VERSION 5.8 ;
BUSBITCHARS "[]" ;
DIVIDERCHAR "/" ;
UNITS
    DATABASE MICRONS 1000 ;
END UNITS

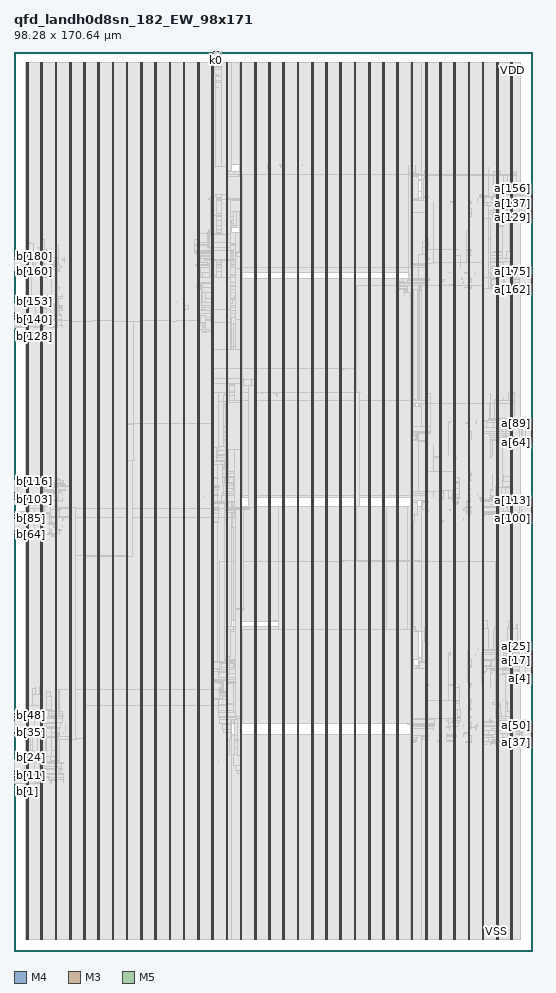
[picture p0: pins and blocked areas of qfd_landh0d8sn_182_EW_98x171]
MACRO qfd_landh0d8sn_182_EW_98x171
  FOREIGN qfd_landh0d8sn_182_EW_98x171 0 0 ;
  CLASS BLOCK ;
  SIZE 98.28 BY 170.64 ;
  PIN a[0]
    DIRECTION INPUT ;
    USE SIGNAL ;
    PORT
      LAYER M4 ;
        RECT  98.196 52.56 98.28 52.584 ;
    END
  END a[0]
  PIN a[100]
    DIRECTION INPUT ;
    USE SIGNAL ;
    PORT
      LAYER M4 ;
        RECT  98.196 81.936 98.28 81.96 ;
    END
  END a[100]
  PIN a[101]
    DIRECTION INPUT ;
    USE SIGNAL ;
    PORT
      LAYER M4 ;
        RECT  98.196 82.08 98.28 82.104 ;
    END
  END a[101]
  PIN a[102]
    DIRECTION INPUT ;
    USE SIGNAL ;
    PORT
      LAYER M4 ;
        RECT  98.196 82.224 98.28 82.248 ;
    END
  END a[102]
  PIN a[103]
    DIRECTION INPUT ;
    USE SIGNAL ;
    PORT
      LAYER M4 ;
        RECT  98.196 82.368 98.28 82.392 ;
    END
  END a[103]
  PIN a[104]
    DIRECTION INPUT ;
    USE SIGNAL ;
    PORT
      LAYER M4 ;
        RECT  98.196 82.512 98.28 82.536 ;
    END
  END a[104]
  PIN a[105]
    DIRECTION INPUT ;
    USE SIGNAL ;
    PORT
      LAYER M4 ;
        RECT  98.196 82.656 98.28 82.68 ;
    END
  END a[105]
  PIN a[106]
    DIRECTION INPUT ;
    USE SIGNAL ;
    PORT
      LAYER M4 ;
        RECT  98.196 82.8 98.28 82.824 ;
    END
  END a[106]
  PIN a[107]
    DIRECTION INPUT ;
    USE SIGNAL ;
    PORT
      LAYER M4 ;
        RECT  98.196 82.944 98.28 82.968 ;
    END
  END a[107]
  PIN a[108]
    DIRECTION INPUT ;
    USE SIGNAL ;
    PORT
      LAYER M4 ;
        RECT  98.196 83.088 98.28 83.112 ;
    END
  END a[108]
  PIN a[109]
    DIRECTION INPUT ;
    USE SIGNAL ;
    PORT
      LAYER M4 ;
        RECT  98.196 83.232 98.28 83.256 ;
    END
  END a[109]
  PIN a[10]
    DIRECTION INPUT ;
    USE SIGNAL ;
    PORT
      LAYER M4 ;
        RECT  98.196 54 98.28 54.024 ;
    END
  END a[10]
  PIN a[110]
    DIRECTION INPUT ;
    USE SIGNAL ;
    PORT
      LAYER M4 ;
        RECT  98.196 83.376 98.28 83.4 ;
    END
  END a[110]
  PIN a[111]
    DIRECTION INPUT ;
    USE SIGNAL ;
    PORT
      LAYER M4 ;
        RECT  98.196 83.52 98.28 83.544 ;
    END
  END a[111]
  PIN a[112]
    DIRECTION INPUT ;
    USE SIGNAL ;
    PORT
      LAYER M4 ;
        RECT  98.196 83.664 98.28 83.688 ;
    END
  END a[112]
  PIN a[113]
    DIRECTION INPUT ;
    USE SIGNAL ;
    PORT
      LAYER M4 ;
        RECT  98.196 83.808 98.28 83.832 ;
    END
  END a[113]
  PIN a[114]
    DIRECTION INPUT ;
    USE SIGNAL ;
    PORT
      LAYER M4 ;
        RECT  98.196 83.952 98.28 83.976 ;
    END
  END a[114]
  PIN a[115]
    DIRECTION INPUT ;
    USE SIGNAL ;
    PORT
      LAYER M4 ;
        RECT  98.196 84.096 98.28 84.12 ;
    END
  END a[115]
  PIN a[116]
    DIRECTION INPUT ;
    USE SIGNAL ;
    PORT
      LAYER M4 ;
        RECT  98.196 84.24 98.28 84.264 ;
    END
  END a[116]
  PIN a[117]
    DIRECTION INPUT ;
    USE SIGNAL ;
    PORT
      LAYER M4 ;
        RECT  98.196 84.384 98.28 84.408 ;
    END
  END a[117]
  PIN a[118]
    DIRECTION INPUT ;
    USE SIGNAL ;
    PORT
      LAYER M4 ;
        RECT  98.196 84.528 98.28 84.552 ;
    END
  END a[118]
  PIN a[119]
    DIRECTION INPUT ;
    USE SIGNAL ;
    PORT
      LAYER M4 ;
        RECT  98.196 84.672 98.28 84.696 ;
    END
  END a[119]
  PIN a[11]
    DIRECTION INPUT ;
    USE SIGNAL ;
    PORT
      LAYER M4 ;
        RECT  98.196 54.144 98.28 54.168 ;
    END
  END a[11]
  PIN a[120]
    DIRECTION INPUT ;
    USE SIGNAL ;
    PORT
      LAYER M4 ;
        RECT  98.196 84.816 98.28 84.84 ;
    END
  END a[120]
  PIN a[121]
    DIRECTION INPUT ;
    USE SIGNAL ;
    PORT
      LAYER M4 ;
        RECT  98.196 84.96 98.28 84.984 ;
    END
  END a[121]
  PIN a[122]
    DIRECTION INPUT ;
    USE SIGNAL ;
    PORT
      LAYER M4 ;
        RECT  98.196 85.104 98.28 85.128 ;
    END
  END a[122]
  PIN a[123]
    DIRECTION INPUT ;
    USE SIGNAL ;
    PORT
      LAYER M4 ;
        RECT  98.196 85.248 98.28 85.272 ;
    END
  END a[123]
  PIN a[124]
    DIRECTION INPUT ;
    USE SIGNAL ;
    PORT
      LAYER M4 ;
        RECT  98.196 85.392 98.28 85.416 ;
    END
  END a[124]
  PIN a[125]
    DIRECTION INPUT ;
    USE SIGNAL ;
    PORT
      LAYER M4 ;
        RECT  98.196 85.536 98.28 85.56 ;
    END
  END a[125]
  PIN a[126]
    DIRECTION INPUT ;
    USE SIGNAL ;
    PORT
      LAYER M4 ;
        RECT  98.196 85.68 98.28 85.704 ;
    END
  END a[126]
  PIN a[127]
    DIRECTION INPUT ;
    USE SIGNAL ;
    PORT
      LAYER M4 ;
        RECT  98.196 85.824 98.28 85.848 ;
    END
  END a[127]
  PIN a[128]
    DIRECTION INPUT ;
    USE SIGNAL ;
    PORT
      LAYER M4 ;
        RECT  98.196 138.96 98.28 138.984 ;
    END
  END a[128]
  PIN a[129]
    DIRECTION INPUT ;
    USE SIGNAL ;
    PORT
      LAYER M4 ;
        RECT  98.196 139.104 98.28 139.128 ;
    END
  END a[129]
  PIN a[12]
    DIRECTION INPUT ;
    USE SIGNAL ;
    PORT
      LAYER M4 ;
        RECT  98.196 54.288 98.28 54.312 ;
    END
  END a[12]
  PIN a[130]
    DIRECTION INPUT ;
    USE SIGNAL ;
    PORT
      LAYER M4 ;
        RECT  98.196 139.248 98.28 139.272 ;
    END
  END a[130]
  PIN a[131]
    DIRECTION INPUT ;
    USE SIGNAL ;
    PORT
      LAYER M4 ;
        RECT  98.196 139.392 98.28 139.416 ;
    END
  END a[131]
  PIN a[132]
    DIRECTION INPUT ;
    USE SIGNAL ;
    PORT
      LAYER M4 ;
        RECT  98.196 139.536 98.28 139.56 ;
    END
  END a[132]
  PIN a[133]
    DIRECTION INPUT ;
    USE SIGNAL ;
    PORT
      LAYER M4 ;
        RECT  98.196 139.68 98.28 139.704 ;
    END
  END a[133]
  PIN a[134]
    DIRECTION INPUT ;
    USE SIGNAL ;
    PORT
      LAYER M4 ;
        RECT  98.196 139.824 98.28 139.848 ;
    END
  END a[134]
  PIN a[135]
    DIRECTION INPUT ;
    USE SIGNAL ;
    PORT
      LAYER M4 ;
        RECT  98.196 139.968 98.28 139.992 ;
    END
  END a[135]
  PIN a[136]
    DIRECTION INPUT ;
    USE SIGNAL ;
    PORT
      LAYER M4 ;
        RECT  98.196 140.112 98.28 140.136 ;
    END
  END a[136]
  PIN a[137]
    DIRECTION INPUT ;
    USE SIGNAL ;
    PORT
      LAYER M4 ;
        RECT  98.196 140.256 98.28 140.28 ;
    END
  END a[137]
  PIN a[138]
    DIRECTION INPUT ;
    USE SIGNAL ;
    PORT
      LAYER M4 ;
        RECT  98.196 140.4 98.28 140.424 ;
    END
  END a[138]
  PIN a[139]
    DIRECTION INPUT ;
    USE SIGNAL ;
    PORT
      LAYER M4 ;
        RECT  98.196 140.544 98.28 140.568 ;
    END
  END a[139]
  PIN a[13]
    DIRECTION INPUT ;
    USE SIGNAL ;
    PORT
      LAYER M4 ;
        RECT  98.196 54.432 98.28 54.456 ;
    END
  END a[13]
  PIN a[140]
    DIRECTION INPUT ;
    USE SIGNAL ;
    PORT
      LAYER M4 ;
        RECT  98.196 140.688 98.28 140.712 ;
    END
  END a[140]
  PIN a[141]
    DIRECTION INPUT ;
    USE SIGNAL ;
    PORT
      LAYER M4 ;
        RECT  98.196 140.832 98.28 140.856 ;
    END
  END a[141]
  PIN a[142]
    DIRECTION INPUT ;
    USE SIGNAL ;
    PORT
      LAYER M4 ;
        RECT  98.196 140.976 98.28 141 ;
    END
  END a[142]
  PIN a[143]
    DIRECTION INPUT ;
    USE SIGNAL ;
    PORT
      LAYER M4 ;
        RECT  98.196 141.12 98.28 141.144 ;
    END
  END a[143]
  PIN a[144]
    DIRECTION INPUT ;
    USE SIGNAL ;
    PORT
      LAYER M4 ;
        RECT  98.196 141.264 98.28 141.288 ;
    END
  END a[144]
  PIN a[145]
    DIRECTION INPUT ;
    USE SIGNAL ;
    PORT
      LAYER M4 ;
        RECT  98.196 141.408 98.28 141.432 ;
    END
  END a[145]
  PIN a[146]
    DIRECTION INPUT ;
    USE SIGNAL ;
    PORT
      LAYER M4 ;
        RECT  98.196 141.552 98.28 141.576 ;
    END
  END a[146]
  PIN a[147]
    DIRECTION INPUT ;
    USE SIGNAL ;
    PORT
      LAYER M4 ;
        RECT  98.196 141.696 98.28 141.72 ;
    END
  END a[147]
  PIN a[148]
    DIRECTION INPUT ;
    USE SIGNAL ;
    PORT
      LAYER M4 ;
        RECT  98.196 141.84 98.28 141.864 ;
    END
  END a[148]
  PIN a[149]
    DIRECTION INPUT ;
    USE SIGNAL ;
    PORT
      LAYER M4 ;
        RECT  98.196 141.984 98.28 142.008 ;
    END
  END a[149]
  PIN a[14]
    DIRECTION INPUT ;
    USE SIGNAL ;
    PORT
      LAYER M4 ;
        RECT  98.196 54.576 98.28 54.6 ;
    END
  END a[14]
  PIN a[150]
    DIRECTION INPUT ;
    USE SIGNAL ;
    PORT
      LAYER M4 ;
        RECT  98.196 142.128 98.28 142.152 ;
    END
  END a[150]
  PIN a[151]
    DIRECTION INPUT ;
    USE SIGNAL ;
    PORT
      LAYER M4 ;
        RECT  98.196 142.272 98.28 142.296 ;
    END
  END a[151]
  PIN a[152]
    DIRECTION INPUT ;
    USE SIGNAL ;
    PORT
      LAYER M4 ;
        RECT  98.196 142.416 98.28 142.44 ;
    END
  END a[152]
  PIN a[153]
    DIRECTION INPUT ;
    USE SIGNAL ;
    PORT
      LAYER M4 ;
        RECT  98.196 142.56 98.28 142.584 ;
    END
  END a[153]
  PIN a[154]
    DIRECTION INPUT ;
    USE SIGNAL ;
    PORT
      LAYER M4 ;
        RECT  98.196 142.704 98.28 142.728 ;
    END
  END a[154]
  PIN a[155]
    DIRECTION INPUT ;
    USE SIGNAL ;
    PORT
      LAYER M4 ;
        RECT  98.196 142.848 98.28 142.872 ;
    END
  END a[155]
  PIN a[156]
    DIRECTION INPUT ;
    USE SIGNAL ;
    PORT
      LAYER M4 ;
        RECT  98.196 142.992 98.28 143.016 ;
    END
  END a[156]
  PIN a[157]
    DIRECTION INPUT ;
    USE SIGNAL ;
    PORT
      LAYER M4 ;
        RECT  98.196 143.136 98.28 143.16 ;
    END
  END a[157]
  PIN a[158]
    DIRECTION INPUT ;
    USE SIGNAL ;
    PORT
      LAYER M4 ;
        RECT  98.196 143.28 98.28 143.304 ;
    END
  END a[158]
  PIN a[159]
    DIRECTION INPUT ;
    USE SIGNAL ;
    PORT
      LAYER M4 ;
        RECT  98.196 143.424 98.28 143.448 ;
    END
  END a[159]
  PIN a[15]
    DIRECTION INPUT ;
    USE SIGNAL ;
    PORT
      LAYER M4 ;
        RECT  98.196 54.72 98.28 54.744 ;
    END
  END a[15]
  PIN a[160]
    DIRECTION INPUT ;
    USE SIGNAL ;
    PORT
      LAYER M4 ;
        RECT  98.196 125.136 98.28 125.16 ;
    END
  END a[160]
  PIN a[161]
    DIRECTION INPUT ;
    USE SIGNAL ;
    PORT
      LAYER M4 ;
        RECT  98.196 125.28 98.28 125.304 ;
    END
  END a[161]
  PIN a[162]
    DIRECTION INPUT ;
    USE SIGNAL ;
    PORT
      LAYER M4 ;
        RECT  98.196 125.424 98.28 125.448 ;
    END
  END a[162]
  PIN a[163]
    DIRECTION INPUT ;
    USE SIGNAL ;
    PORT
      LAYER M4 ;
        RECT  98.196 125.568 98.28 125.592 ;
    END
  END a[163]
  PIN a[164]
    DIRECTION INPUT ;
    USE SIGNAL ;
    PORT
      LAYER M4 ;
        RECT  98.196 125.712 98.28 125.736 ;
    END
  END a[164]
  PIN a[165]
    DIRECTION INPUT ;
    USE SIGNAL ;
    PORT
      LAYER M4 ;
        RECT  98.196 125.856 98.28 125.88 ;
    END
  END a[165]
  PIN a[166]
    DIRECTION INPUT ;
    USE SIGNAL ;
    PORT
      LAYER M4 ;
        RECT  98.196 126 98.28 126.024 ;
    END
  END a[166]
  PIN a[167]
    DIRECTION INPUT ;
    USE SIGNAL ;
    PORT
      LAYER M4 ;
        RECT  98.196 126.144 98.28 126.168 ;
    END
  END a[167]
  PIN a[168]
    DIRECTION INPUT ;
    USE SIGNAL ;
    PORT
      LAYER M4 ;
        RECT  98.196 126.288 98.28 126.312 ;
    END
  END a[168]
  PIN a[169]
    DIRECTION INPUT ;
    USE SIGNAL ;
    PORT
      LAYER M4 ;
        RECT  98.196 126.432 98.28 126.456 ;
    END
  END a[169]
  PIN a[16]
    DIRECTION INPUT ;
    USE SIGNAL ;
    PORT
      LAYER M4 ;
        RECT  98.196 54.864 98.28 54.888 ;
    END
  END a[16]
  PIN a[170]
    DIRECTION INPUT ;
    USE SIGNAL ;
    PORT
      LAYER M4 ;
        RECT  98.196 126.576 98.28 126.6 ;
    END
  END a[170]
  PIN a[171]
    DIRECTION INPUT ;
    USE SIGNAL ;
    PORT
      LAYER M4 ;
        RECT  98.196 126.72 98.28 126.744 ;
    END
  END a[171]
  PIN a[172]
    DIRECTION INPUT ;
    USE SIGNAL ;
    PORT
      LAYER M4 ;
        RECT  98.196 126.864 98.28 126.888 ;
    END
  END a[172]
  PIN a[173]
    DIRECTION INPUT ;
    USE SIGNAL ;
    PORT
      LAYER M4 ;
        RECT  98.196 127.008 98.28 127.032 ;
    END
  END a[173]
  PIN a[174]
    DIRECTION INPUT ;
    USE SIGNAL ;
    PORT
      LAYER M4 ;
        RECT  98.196 127.152 98.28 127.176 ;
    END
  END a[174]
  PIN a[175]
    DIRECTION INPUT ;
    USE SIGNAL ;
    PORT
      LAYER M4 ;
        RECT  98.196 127.296 98.28 127.32 ;
    END
  END a[175]
  PIN a[176]
    DIRECTION INPUT ;
    USE SIGNAL ;
    PORT
      LAYER M4 ;
        RECT  98.196 127.44 98.28 127.464 ;
    END
  END a[176]
  PIN a[177]
    DIRECTION INPUT ;
    USE SIGNAL ;
    PORT
      LAYER M4 ;
        RECT  98.196 127.584 98.28 127.608 ;
    END
  END a[177]
  PIN a[178]
    DIRECTION INPUT ;
    USE SIGNAL ;
    PORT
      LAYER M4 ;
        RECT  98.196 127.728 98.28 127.752 ;
    END
  END a[178]
  PIN a[179]
    DIRECTION INPUT ;
    USE SIGNAL ;
    PORT
      LAYER M4 ;
        RECT  98.196 127.872 98.28 127.896 ;
    END
  END a[179]
  PIN a[17]
    DIRECTION INPUT ;
    USE SIGNAL ;
    PORT
      LAYER M4 ;
        RECT  98.196 55.008 98.28 55.032 ;
    END
  END a[17]
  PIN a[180]
    DIRECTION INPUT ;
    USE SIGNAL ;
    PORT
      LAYER M4 ;
        RECT  98.196 128.016 98.28 128.04 ;
    END
  END a[180]
  PIN a[181]
    DIRECTION INPUT ;
    USE SIGNAL ;
    PORT
      LAYER M4 ;
        RECT  98.196 128.16 98.28 128.184 ;
    END
  END a[181]
  PIN a[18]
    DIRECTION INPUT ;
    USE SIGNAL ;
    PORT
      LAYER M4 ;
        RECT  98.196 55.152 98.28 55.176 ;
    END
  END a[18]
  PIN a[19]
    DIRECTION INPUT ;
    USE SIGNAL ;
    PORT
      LAYER M4 ;
        RECT  98.196 55.296 98.28 55.32 ;
    END
  END a[19]
  PIN a[1]
    DIRECTION INPUT ;
    USE SIGNAL ;
    PORT
      LAYER M4 ;
        RECT  98.196 52.704 98.28 52.728 ;
    END
  END a[1]
  PIN a[20]
    DIRECTION INPUT ;
    USE SIGNAL ;
    PORT
      LAYER M4 ;
        RECT  98.196 55.44 98.28 55.464 ;
    END
  END a[20]
  PIN a[21]
    DIRECTION INPUT ;
    USE SIGNAL ;
    PORT
      LAYER M4 ;
        RECT  98.196 55.584 98.28 55.608 ;
    END
  END a[21]
  PIN a[22]
    DIRECTION INPUT ;
    USE SIGNAL ;
    PORT
      LAYER M4 ;
        RECT  98.196 55.728 98.28 55.752 ;
    END
  END a[22]
  PIN a[23]
    DIRECTION INPUT ;
    USE SIGNAL ;
    PORT
      LAYER M4 ;
        RECT  98.196 55.872 98.28 55.896 ;
    END
  END a[23]
  PIN a[24]
    DIRECTION INPUT ;
    USE SIGNAL ;
    PORT
      LAYER M4 ;
        RECT  98.196 56.016 98.28 56.04 ;
    END
  END a[24]
  PIN a[25]
    DIRECTION INPUT ;
    USE SIGNAL ;
    PORT
      LAYER M4 ;
        RECT  98.196 56.16 98.28 56.184 ;
    END
  END a[25]
  PIN a[26]
    DIRECTION INPUT ;
    USE SIGNAL ;
    PORT
      LAYER M4 ;
        RECT  98.196 56.304 98.28 56.328 ;
    END
  END a[26]
  PIN a[27]
    DIRECTION INPUT ;
    USE SIGNAL ;
    PORT
      LAYER M4 ;
        RECT  98.196 56.448 98.28 56.472 ;
    END
  END a[27]
  PIN a[28]
    DIRECTION INPUT ;
    USE SIGNAL ;
    PORT
      LAYER M4 ;
        RECT  98.196 56.592 98.28 56.616 ;
    END
  END a[28]
  PIN a[29]
    DIRECTION INPUT ;
    USE SIGNAL ;
    PORT
      LAYER M4 ;
        RECT  98.196 56.736 98.28 56.76 ;
    END
  END a[29]
  PIN a[2]
    DIRECTION INPUT ;
    USE SIGNAL ;
    PORT
      LAYER M4 ;
        RECT  98.196 52.848 98.28 52.872 ;
    END
  END a[2]
  PIN a[30]
    DIRECTION INPUT ;
    USE SIGNAL ;
    PORT
      LAYER M4 ;
        RECT  98.196 56.88 98.28 56.904 ;
    END
  END a[30]
  PIN a[31]
    DIRECTION INPUT ;
    USE SIGNAL ;
    PORT
      LAYER M4 ;
        RECT  98.196 57.024 98.28 57.048 ;
    END
  END a[31]
  PIN a[32]
    DIRECTION INPUT ;
    USE SIGNAL ;
    PORT
      LAYER M4 ;
        RECT  98.196 38.736 98.28 38.76 ;
    END
  END a[32]
  PIN a[33]
    DIRECTION INPUT ;
    USE SIGNAL ;
    PORT
      LAYER M4 ;
        RECT  98.196 38.88 98.28 38.904 ;
    END
  END a[33]
  PIN a[34]
    DIRECTION INPUT ;
    USE SIGNAL ;
    PORT
      LAYER M4 ;
        RECT  98.196 39.024 98.28 39.048 ;
    END
  END a[34]
  PIN a[35]
    DIRECTION INPUT ;
    USE SIGNAL ;
    PORT
      LAYER M4 ;
        RECT  98.196 39.168 98.28 39.192 ;
    END
  END a[35]
  PIN a[36]
    DIRECTION INPUT ;
    USE SIGNAL ;
    PORT
      LAYER M4 ;
        RECT  98.196 39.312 98.28 39.336 ;
    END
  END a[36]
  PIN a[37]
    DIRECTION INPUT ;
    USE SIGNAL ;
    PORT
      LAYER M4 ;
        RECT  98.196 39.456 98.28 39.48 ;
    END
  END a[37]
  PIN a[38]
    DIRECTION INPUT ;
    USE SIGNAL ;
    PORT
      LAYER M4 ;
        RECT  98.196 39.6 98.28 39.624 ;
    END
  END a[38]
  PIN a[39]
    DIRECTION INPUT ;
    USE SIGNAL ;
    PORT
      LAYER M4 ;
        RECT  98.196 39.744 98.28 39.768 ;
    END
  END a[39]
  PIN a[3]
    DIRECTION INPUT ;
    USE SIGNAL ;
    PORT
      LAYER M4 ;
        RECT  98.196 52.992 98.28 53.016 ;
    END
  END a[3]
  PIN a[40]
    DIRECTION INPUT ;
    USE SIGNAL ;
    PORT
      LAYER M4 ;
        RECT  98.196 39.888 98.28 39.912 ;
    END
  END a[40]
  PIN a[41]
    DIRECTION INPUT ;
    USE SIGNAL ;
    PORT
      LAYER M4 ;
        RECT  98.196 40.032 98.28 40.056 ;
    END
  END a[41]
  PIN a[42]
    DIRECTION INPUT ;
    USE SIGNAL ;
    PORT
      LAYER M4 ;
        RECT  98.196 40.176 98.28 40.2 ;
    END
  END a[42]
  PIN a[43]
    DIRECTION INPUT ;
    USE SIGNAL ;
    PORT
      LAYER M4 ;
        RECT  98.196 40.32 98.28 40.344 ;
    END
  END a[43]
  PIN a[44]
    DIRECTION INPUT ;
    USE SIGNAL ;
    PORT
      LAYER M4 ;
        RECT  98.196 40.464 98.28 40.488 ;
    END
  END a[44]
  PIN a[45]
    DIRECTION INPUT ;
    USE SIGNAL ;
    PORT
      LAYER M4 ;
        RECT  98.196 40.608 98.28 40.632 ;
    END
  END a[45]
  PIN a[46]
    DIRECTION INPUT ;
    USE SIGNAL ;
    PORT
      LAYER M4 ;
        RECT  98.196 40.752 98.28 40.776 ;
    END
  END a[46]
  PIN a[47]
    DIRECTION INPUT ;
    USE SIGNAL ;
    PORT
      LAYER M4 ;
        RECT  98.196 40.896 98.28 40.92 ;
    END
  END a[47]
  PIN a[48]
    DIRECTION INPUT ;
    USE SIGNAL ;
    PORT
      LAYER M4 ;
        RECT  98.196 41.04 98.28 41.064 ;
    END
  END a[48]
  PIN a[49]
    DIRECTION INPUT ;
    USE SIGNAL ;
    PORT
      LAYER M4 ;
        RECT  98.196 41.184 98.28 41.208 ;
    END
  END a[49]
  PIN a[4]
    DIRECTION INPUT ;
    USE SIGNAL ;
    PORT
      LAYER M4 ;
        RECT  98.196 53.136 98.28 53.16 ;
    END
  END a[4]
  PIN a[50]
    DIRECTION INPUT ;
    USE SIGNAL ;
    PORT
      LAYER M4 ;
        RECT  98.196 41.328 98.28 41.352 ;
    END
  END a[50]
  PIN a[51]
    DIRECTION INPUT ;
    USE SIGNAL ;
    PORT
      LAYER M4 ;
        RECT  98.196 41.472 98.28 41.496 ;
    END
  END a[51]
  PIN a[52]
    DIRECTION INPUT ;
    USE SIGNAL ;
    PORT
      LAYER M4 ;
        RECT  98.196 41.616 98.28 41.64 ;
    END
  END a[52]
  PIN a[53]
    DIRECTION INPUT ;
    USE SIGNAL ;
    PORT
      LAYER M4 ;
        RECT  98.196 41.76 98.28 41.784 ;
    END
  END a[53]
  PIN a[54]
    DIRECTION INPUT ;
    USE SIGNAL ;
    PORT
      LAYER M4 ;
        RECT  98.196 41.904 98.28 41.928 ;
    END
  END a[54]
  PIN a[55]
    DIRECTION INPUT ;
    USE SIGNAL ;
    PORT
      LAYER M4 ;
        RECT  98.196 42.048 98.28 42.072 ;
    END
  END a[55]
  PIN a[56]
    DIRECTION INPUT ;
    USE SIGNAL ;
    PORT
      LAYER M4 ;
        RECT  98.196 42.192 98.28 42.216 ;
    END
  END a[56]
  PIN a[57]
    DIRECTION INPUT ;
    USE SIGNAL ;
    PORT
      LAYER M4 ;
        RECT  98.196 42.336 98.28 42.36 ;
    END
  END a[57]
  PIN a[58]
    DIRECTION INPUT ;
    USE SIGNAL ;
    PORT
      LAYER M4 ;
        RECT  98.196 42.48 98.28 42.504 ;
    END
  END a[58]
  PIN a[59]
    DIRECTION INPUT ;
    USE SIGNAL ;
    PORT
      LAYER M4 ;
        RECT  98.196 42.624 98.28 42.648 ;
    END
  END a[59]
  PIN a[5]
    DIRECTION INPUT ;
    USE SIGNAL ;
    PORT
      LAYER M4 ;
        RECT  98.196 53.28 98.28 53.304 ;
    END
  END a[5]
  PIN a[60]
    DIRECTION INPUT ;
    USE SIGNAL ;
    PORT
      LAYER M4 ;
        RECT  98.196 42.768 98.28 42.792 ;
    END
  END a[60]
  PIN a[61]
    DIRECTION INPUT ;
    USE SIGNAL ;
    PORT
      LAYER M4 ;
        RECT  98.196 42.912 98.28 42.936 ;
    END
  END a[61]
  PIN a[62]
    DIRECTION INPUT ;
    USE SIGNAL ;
    PORT
      LAYER M4 ;
        RECT  98.196 43.056 98.28 43.08 ;
    END
  END a[62]
  PIN a[63]
    DIRECTION INPUT ;
    USE SIGNAL ;
    PORT
      LAYER M4 ;
        RECT  98.196 43.2 98.28 43.224 ;
    END
  END a[63]
  PIN a[64]
    DIRECTION INPUT ;
    USE SIGNAL ;
    PORT
      LAYER M4 ;
        RECT  98.196 96.336 98.28 96.36 ;
    END
  END a[64]
  PIN a[65]
    DIRECTION INPUT ;
    USE SIGNAL ;
    PORT
      LAYER M4 ;
        RECT  98.196 96.48 98.28 96.504 ;
    END
  END a[65]
  PIN a[66]
    DIRECTION INPUT ;
    USE SIGNAL ;
    PORT
      LAYER M4 ;
        RECT  98.196 96.624 98.28 96.648 ;
    END
  END a[66]
  PIN a[67]
    DIRECTION INPUT ;
    USE SIGNAL ;
    PORT
      LAYER M4 ;
        RECT  98.196 96.768 98.28 96.792 ;
    END
  END a[67]
  PIN a[68]
    DIRECTION INPUT ;
    USE SIGNAL ;
    PORT
      LAYER M4 ;
        RECT  98.196 96.912 98.28 96.936 ;
    END
  END a[68]
  PIN a[69]
    DIRECTION INPUT ;
    USE SIGNAL ;
    PORT
      LAYER M4 ;
        RECT  98.196 97.056 98.28 97.08 ;
    END
  END a[69]
  PIN a[6]
    DIRECTION INPUT ;
    USE SIGNAL ;
    PORT
      LAYER M4 ;
        RECT  98.196 53.424 98.28 53.448 ;
    END
  END a[6]
  PIN a[70]
    DIRECTION INPUT ;
    USE SIGNAL ;
    PORT
      LAYER M4 ;
        RECT  98.196 97.2 98.28 97.224 ;
    END
  END a[70]
  PIN a[71]
    DIRECTION INPUT ;
    USE SIGNAL ;
    PORT
      LAYER M4 ;
        RECT  98.196 97.344 98.28 97.368 ;
    END
  END a[71]
  PIN a[72]
    DIRECTION INPUT ;
    USE SIGNAL ;
    PORT
      LAYER M4 ;
        RECT  98.196 97.488 98.28 97.512 ;
    END
  END a[72]
  PIN a[73]
    DIRECTION INPUT ;
    USE SIGNAL ;
    PORT
      LAYER M4 ;
        RECT  98.196 97.632 98.28 97.656 ;
    END
  END a[73]
  PIN a[74]
    DIRECTION INPUT ;
    USE SIGNAL ;
    PORT
      LAYER M4 ;
        RECT  98.196 97.776 98.28 97.8 ;
    END
  END a[74]
  PIN a[75]
    DIRECTION INPUT ;
    USE SIGNAL ;
    PORT
      LAYER M4 ;
        RECT  98.196 97.92 98.28 97.944 ;
    END
  END a[75]
  PIN a[76]
    DIRECTION INPUT ;
    USE SIGNAL ;
    PORT
      LAYER M4 ;
        RECT  98.196 98.064 98.28 98.088 ;
    END
  END a[76]
  PIN a[77]
    DIRECTION INPUT ;
    USE SIGNAL ;
    PORT
      LAYER M4 ;
        RECT  98.196 98.208 98.28 98.232 ;
    END
  END a[77]
  PIN a[78]
    DIRECTION INPUT ;
    USE SIGNAL ;
    PORT
      LAYER M4 ;
        RECT  98.196 98.352 98.28 98.376 ;
    END
  END a[78]
  PIN a[79]
    DIRECTION INPUT ;
    USE SIGNAL ;
    PORT
      LAYER M4 ;
        RECT  98.196 98.496 98.28 98.52 ;
    END
  END a[79]
  PIN a[7]
    DIRECTION INPUT ;
    USE SIGNAL ;
    PORT
      LAYER M4 ;
        RECT  98.196 53.568 98.28 53.592 ;
    END
  END a[7]
  PIN a[80]
    DIRECTION INPUT ;
    USE SIGNAL ;
    PORT
      LAYER M4 ;
        RECT  98.196 98.64 98.28 98.664 ;
    END
  END a[80]
  PIN a[81]
    DIRECTION INPUT ;
    USE SIGNAL ;
    PORT
      LAYER M4 ;
        RECT  98.196 98.784 98.28 98.808 ;
    END
  END a[81]
  PIN a[82]
    DIRECTION INPUT ;
    USE SIGNAL ;
    PORT
      LAYER M4 ;
        RECT  98.196 98.928 98.28 98.952 ;
    END
  END a[82]
  PIN a[83]
    DIRECTION INPUT ;
    USE SIGNAL ;
    PORT
      LAYER M4 ;
        RECT  98.196 99.072 98.28 99.096 ;
    END
  END a[83]
  PIN a[84]
    DIRECTION INPUT ;
    USE SIGNAL ;
    PORT
      LAYER M4 ;
        RECT  98.196 99.216 98.28 99.24 ;
    END
  END a[84]
  PIN a[85]
    DIRECTION INPUT ;
    USE SIGNAL ;
    PORT
      LAYER M4 ;
        RECT  98.196 99.36 98.28 99.384 ;
    END
  END a[85]
  PIN a[86]
    DIRECTION INPUT ;
    USE SIGNAL ;
    PORT
      LAYER M4 ;
        RECT  98.196 99.504 98.28 99.528 ;
    END
  END a[86]
  PIN a[87]
    DIRECTION INPUT ;
    USE SIGNAL ;
    PORT
      LAYER M4 ;
        RECT  98.196 99.648 98.28 99.672 ;
    END
  END a[87]
  PIN a[88]
    DIRECTION INPUT ;
    USE SIGNAL ;
    PORT
      LAYER M4 ;
        RECT  98.196 99.792 98.28 99.816 ;
    END
  END a[88]
  PIN a[89]
    DIRECTION INPUT ;
    USE SIGNAL ;
    PORT
      LAYER M4 ;
        RECT  98.196 99.936 98.28 99.96 ;
    END
  END a[89]
  PIN a[8]
    DIRECTION INPUT ;
    USE SIGNAL ;
    PORT
      LAYER M4 ;
        RECT  98.196 53.712 98.28 53.736 ;
    END
  END a[8]
  PIN a[90]
    DIRECTION INPUT ;
    USE SIGNAL ;
    PORT
      LAYER M4 ;
        RECT  98.196 100.08 98.28 100.104 ;
    END
  END a[90]
  PIN a[91]
    DIRECTION INPUT ;
    USE SIGNAL ;
    PORT
      LAYER M4 ;
        RECT  98.196 100.224 98.28 100.248 ;
    END
  END a[91]
  PIN a[92]
    DIRECTION INPUT ;
    USE SIGNAL ;
    PORT
      LAYER M4 ;
        RECT  98.196 100.368 98.28 100.392 ;
    END
  END a[92]
  PIN a[93]
    DIRECTION INPUT ;
    USE SIGNAL ;
    PORT
      LAYER M4 ;
        RECT  98.196 100.512 98.28 100.536 ;
    END
  END a[93]
  PIN a[94]
    DIRECTION INPUT ;
    USE SIGNAL ;
    PORT
      LAYER M4 ;
        RECT  98.196 100.656 98.28 100.68 ;
    END
  END a[94]
  PIN a[95]
    DIRECTION INPUT ;
    USE SIGNAL ;
    PORT
      LAYER M4 ;
        RECT  98.196 100.8 98.28 100.824 ;
    END
  END a[95]
  PIN a[96]
    DIRECTION INPUT ;
    USE SIGNAL ;
    PORT
      LAYER M4 ;
        RECT  98.196 81.36 98.28 81.384 ;
    END
  END a[96]
  PIN a[97]
    DIRECTION INPUT ;
    USE SIGNAL ;
    PORT
      LAYER M4 ;
        RECT  98.196 81.504 98.28 81.528 ;
    END
  END a[97]
  PIN a[98]
    DIRECTION INPUT ;
    USE SIGNAL ;
    PORT
      LAYER M4 ;
        RECT  98.196 81.648 98.28 81.672 ;
    END
  END a[98]
  PIN a[99]
    DIRECTION INPUT ;
    USE SIGNAL ;
    PORT
      LAYER M4 ;
        RECT  98.196 81.792 98.28 81.816 ;
    END
  END a[99]
  PIN a[9]
    DIRECTION INPUT ;
    USE SIGNAL ;
    PORT
      LAYER M4 ;
        RECT  98.196 53.856 98.28 53.88 ;
    END
  END a[9]
  PIN b[0]
    DIRECTION OUTPUT ;
    USE SIGNAL ;
    PORT
      LAYER M4 ;
        RECT  0 31.68 0.084 31.704 ;
    END
  END b[0]
  PIN b[100]
    DIRECTION OUTPUT ;
    USE SIGNAL ;
    PORT
      LAYER M4 ;
        RECT  0 85.248 0.084 85.272 ;
    END
  END b[100]
  PIN b[101]
    DIRECTION OUTPUT ;
    USE SIGNAL ;
    PORT
      LAYER M4 ;
        RECT  0 85.392 0.084 85.416 ;
    END
  END b[101]
  PIN b[102]
    DIRECTION OUTPUT ;
    USE SIGNAL ;
    PORT
      LAYER M4 ;
        RECT  0 85.536 0.084 85.56 ;
    END
  END b[102]
  PIN b[103]
    DIRECTION OUTPUT ;
    USE SIGNAL ;
    PORT
      LAYER M4 ;
        RECT  0 85.68 0.084 85.704 ;
    END
  END b[103]
  PIN b[104]
    DIRECTION OUTPUT ;
    USE SIGNAL ;
    PORT
      LAYER M4 ;
        RECT  0 85.824 0.084 85.848 ;
    END
  END b[104]
  PIN b[105]
    DIRECTION OUTPUT ;
    USE SIGNAL ;
    PORT
      LAYER M4 ;
        RECT  0 85.968 0.084 85.992 ;
    END
  END b[105]
  PIN b[106]
    DIRECTION OUTPUT ;
    USE SIGNAL ;
    PORT
      LAYER M4 ;
        RECT  0 86.112 0.084 86.136 ;
    END
  END b[106]
  PIN b[107]
    DIRECTION OUTPUT ;
    USE SIGNAL ;
    PORT
      LAYER M4 ;
        RECT  0 86.256 0.084 86.28 ;
    END
  END b[107]
  PIN b[108]
    DIRECTION OUTPUT ;
    USE SIGNAL ;
    PORT
      LAYER M4 ;
        RECT  0 86.4 0.084 86.424 ;
    END
  END b[108]
  PIN b[109]
    DIRECTION OUTPUT ;
    USE SIGNAL ;
    PORT
      LAYER M4 ;
        RECT  0 86.544 0.084 86.568 ;
    END
  END b[109]
  PIN b[10]
    DIRECTION OUTPUT ;
    USE SIGNAL ;
    PORT
      LAYER M4 ;
        RECT  0 33.12 0.084 33.144 ;
    END
  END b[10]
  PIN b[110]
    DIRECTION OUTPUT ;
    USE SIGNAL ;
    PORT
      LAYER M4 ;
        RECT  0 86.688 0.084 86.712 ;
    END
  END b[110]
  PIN b[111]
    DIRECTION OUTPUT ;
    USE SIGNAL ;
    PORT
      LAYER M4 ;
        RECT  0 86.832 0.084 86.856 ;
    END
  END b[111]
  PIN b[112]
    DIRECTION OUTPUT ;
    USE SIGNAL ;
    PORT
      LAYER M4 ;
        RECT  0 86.976 0.084 87 ;
    END
  END b[112]
  PIN b[113]
    DIRECTION OUTPUT ;
    USE SIGNAL ;
    PORT
      LAYER M4 ;
        RECT  0 87.12 0.084 87.144 ;
    END
  END b[113]
  PIN b[114]
    DIRECTION OUTPUT ;
    USE SIGNAL ;
    PORT
      LAYER M4 ;
        RECT  0 87.264 0.084 87.288 ;
    END
  END b[114]
  PIN b[115]
    DIRECTION OUTPUT ;
    USE SIGNAL ;
    PORT
      LAYER M4 ;
        RECT  0 87.408 0.084 87.432 ;
    END
  END b[115]
  PIN b[116]
    DIRECTION OUTPUT ;
    USE SIGNAL ;
    PORT
      LAYER M4 ;
        RECT  0 87.552 0.084 87.576 ;
    END
  END b[116]
  PIN b[117]
    DIRECTION OUTPUT ;
    USE SIGNAL ;
    PORT
      LAYER M4 ;
        RECT  0 87.696 0.084 87.72 ;
    END
  END b[117]
  PIN b[118]
    DIRECTION OUTPUT ;
    USE SIGNAL ;
    PORT
      LAYER M4 ;
        RECT  0 87.84 0.084 87.864 ;
    END
  END b[118]
  PIN b[119]
    DIRECTION OUTPUT ;
    USE SIGNAL ;
    PORT
      LAYER M4 ;
        RECT  0 87.984 0.084 88.008 ;
    END
  END b[119]
  PIN b[11]
    DIRECTION OUTPUT ;
    USE SIGNAL ;
    PORT
      LAYER M4 ;
        RECT  0 33.264 0.084 33.288 ;
    END
  END b[11]
  PIN b[120]
    DIRECTION OUTPUT ;
    USE SIGNAL ;
    PORT
      LAYER M4 ;
        RECT  0 88.128 0.084 88.152 ;
    END
  END b[120]
  PIN b[121]
    DIRECTION OUTPUT ;
    USE SIGNAL ;
    PORT
      LAYER M4 ;
        RECT  0 88.272 0.084 88.296 ;
    END
  END b[121]
  PIN b[122]
    DIRECTION OUTPUT ;
    USE SIGNAL ;
    PORT
      LAYER M4 ;
        RECT  0 88.416 0.084 88.44 ;
    END
  END b[122]
  PIN b[123]
    DIRECTION OUTPUT ;
    USE SIGNAL ;
    PORT
      LAYER M4 ;
        RECT  0 88.56 0.084 88.584 ;
    END
  END b[123]
  PIN b[124]
    DIRECTION OUTPUT ;
    USE SIGNAL ;
    PORT
      LAYER M4 ;
        RECT  0 88.704 0.084 88.728 ;
    END
  END b[124]
  PIN b[125]
    DIRECTION OUTPUT ;
    USE SIGNAL ;
    PORT
      LAYER M4 ;
        RECT  0 88.848 0.084 88.872 ;
    END
  END b[125]
  PIN b[126]
    DIRECTION OUTPUT ;
    USE SIGNAL ;
    PORT
      LAYER M4 ;
        RECT  0 88.992 0.084 89.016 ;
    END
  END b[126]
  PIN b[127]
    DIRECTION OUTPUT ;
    USE SIGNAL ;
    PORT
      LAYER M4 ;
        RECT  0 89.136 0.084 89.16 ;
    END
  END b[127]
  PIN b[128]
    DIRECTION OUTPUT ;
    USE SIGNAL ;
    PORT
      LAYER M4 ;
        RECT  0 118.08 0.084 118.104 ;
    END
  END b[128]
  PIN b[129]
    DIRECTION OUTPUT ;
    USE SIGNAL ;
    PORT
      LAYER M4 ;
        RECT  0 118.224 0.084 118.248 ;
    END
  END b[129]
  PIN b[12]
    DIRECTION OUTPUT ;
    USE SIGNAL ;
    PORT
      LAYER M4 ;
        RECT  0 33.408 0.084 33.432 ;
    END
  END b[12]
  PIN b[130]
    DIRECTION OUTPUT ;
    USE SIGNAL ;
    PORT
      LAYER M4 ;
        RECT  0 118.368 0.084 118.392 ;
    END
  END b[130]
  PIN b[131]
    DIRECTION OUTPUT ;
    USE SIGNAL ;
    PORT
      LAYER M4 ;
        RECT  0 118.512 0.084 118.536 ;
    END
  END b[131]
  PIN b[132]
    DIRECTION OUTPUT ;
    USE SIGNAL ;
    PORT
      LAYER M4 ;
        RECT  0 118.656 0.084 118.68 ;
    END
  END b[132]
  PIN b[133]
    DIRECTION OUTPUT ;
    USE SIGNAL ;
    PORT
      LAYER M4 ;
        RECT  0 118.8 0.084 118.824 ;
    END
  END b[133]
  PIN b[134]
    DIRECTION OUTPUT ;
    USE SIGNAL ;
    PORT
      LAYER M4 ;
        RECT  0 118.944 0.084 118.968 ;
    END
  END b[134]
  PIN b[135]
    DIRECTION OUTPUT ;
    USE SIGNAL ;
    PORT
      LAYER M4 ;
        RECT  0 119.088 0.084 119.112 ;
    END
  END b[135]
  PIN b[136]
    DIRECTION OUTPUT ;
    USE SIGNAL ;
    PORT
      LAYER M4 ;
        RECT  0 119.232 0.084 119.256 ;
    END
  END b[136]
  PIN b[137]
    DIRECTION OUTPUT ;
    USE SIGNAL ;
    PORT
      LAYER M4 ;
        RECT  0 119.376 0.084 119.4 ;
    END
  END b[137]
  PIN b[138]
    DIRECTION OUTPUT ;
    USE SIGNAL ;
    PORT
      LAYER M4 ;
        RECT  0 119.52 0.084 119.544 ;
    END
  END b[138]
  PIN b[139]
    DIRECTION OUTPUT ;
    USE SIGNAL ;
    PORT
      LAYER M4 ;
        RECT  0 119.664 0.084 119.688 ;
    END
  END b[139]
  PIN b[13]
    DIRECTION OUTPUT ;
    USE SIGNAL ;
    PORT
      LAYER M4 ;
        RECT  0 33.552 0.084 33.576 ;
    END
  END b[13]
  PIN b[140]
    DIRECTION OUTPUT ;
    USE SIGNAL ;
    PORT
      LAYER M4 ;
        RECT  0 119.808 0.084 119.832 ;
    END
  END b[140]
  PIN b[141]
    DIRECTION OUTPUT ;
    USE SIGNAL ;
    PORT
      LAYER M4 ;
        RECT  0 119.952 0.084 119.976 ;
    END
  END b[141]
  PIN b[142]
    DIRECTION OUTPUT ;
    USE SIGNAL ;
    PORT
      LAYER M4 ;
        RECT  0 120.096 0.084 120.12 ;
    END
  END b[142]
  PIN b[143]
    DIRECTION OUTPUT ;
    USE SIGNAL ;
    PORT
      LAYER M4 ;
        RECT  0 120.24 0.084 120.264 ;
    END
  END b[143]
  PIN b[144]
    DIRECTION OUTPUT ;
    USE SIGNAL ;
    PORT
      LAYER M4 ;
        RECT  0 120.384 0.084 120.408 ;
    END
  END b[144]
  PIN b[145]
    DIRECTION OUTPUT ;
    USE SIGNAL ;
    PORT
      LAYER M4 ;
        RECT  0 120.528 0.084 120.552 ;
    END
  END b[145]
  PIN b[146]
    DIRECTION OUTPUT ;
    USE SIGNAL ;
    PORT
      LAYER M4 ;
        RECT  0 120.672 0.084 120.696 ;
    END
  END b[146]
  PIN b[147]
    DIRECTION OUTPUT ;
    USE SIGNAL ;
    PORT
      LAYER M4 ;
        RECT  0 120.816 0.084 120.84 ;
    END
  END b[147]
  PIN b[148]
    DIRECTION OUTPUT ;
    USE SIGNAL ;
    PORT
      LAYER M4 ;
        RECT  0 120.96 0.084 120.984 ;
    END
  END b[148]
  PIN b[149]
    DIRECTION OUTPUT ;
    USE SIGNAL ;
    PORT
      LAYER M4 ;
        RECT  0 121.104 0.084 121.128 ;
    END
  END b[149]
  PIN b[14]
    DIRECTION OUTPUT ;
    USE SIGNAL ;
    PORT
      LAYER M4 ;
        RECT  0 33.696 0.084 33.72 ;
    END
  END b[14]
  PIN b[150]
    DIRECTION OUTPUT ;
    USE SIGNAL ;
    PORT
      LAYER M4 ;
        RECT  0 121.248 0.084 121.272 ;
    END
  END b[150]
  PIN b[151]
    DIRECTION OUTPUT ;
    USE SIGNAL ;
    PORT
      LAYER M4 ;
        RECT  0 121.392 0.084 121.416 ;
    END
  END b[151]
  PIN b[152]
    DIRECTION OUTPUT ;
    USE SIGNAL ;
    PORT
      LAYER M4 ;
        RECT  0 121.536 0.084 121.56 ;
    END
  END b[152]
  PIN b[153]
    DIRECTION OUTPUT ;
    USE SIGNAL ;
    PORT
      LAYER M4 ;
        RECT  0 121.68 0.084 121.704 ;
    END
  END b[153]
  PIN b[154]
    DIRECTION OUTPUT ;
    USE SIGNAL ;
    PORT
      LAYER M4 ;
        RECT  0 121.824 0.084 121.848 ;
    END
  END b[154]
  PIN b[155]
    DIRECTION OUTPUT ;
    USE SIGNAL ;
    PORT
      LAYER M4 ;
        RECT  0 121.968 0.084 121.992 ;
    END
  END b[155]
  PIN b[156]
    DIRECTION OUTPUT ;
    USE SIGNAL ;
    PORT
      LAYER M4 ;
        RECT  0 122.112 0.084 122.136 ;
    END
  END b[156]
  PIN b[157]
    DIRECTION OUTPUT ;
    USE SIGNAL ;
    PORT
      LAYER M4 ;
        RECT  0 122.256 0.084 122.28 ;
    END
  END b[157]
  PIN b[158]
    DIRECTION OUTPUT ;
    USE SIGNAL ;
    PORT
      LAYER M4 ;
        RECT  0 122.4 0.084 122.424 ;
    END
  END b[158]
  PIN b[159]
    DIRECTION OUTPUT ;
    USE SIGNAL ;
    PORT
      LAYER M4 ;
        RECT  0 122.544 0.084 122.568 ;
    END
  END b[159]
  PIN b[15]
    DIRECTION OUTPUT ;
    USE SIGNAL ;
    PORT
      LAYER M4 ;
        RECT  0 33.84 0.084 33.864 ;
    END
  END b[15]
  PIN b[160]
    DIRECTION OUTPUT ;
    USE SIGNAL ;
    PORT
      LAYER M4 ;
        RECT  0 128.736 0.084 128.76 ;
    END
  END b[160]
  PIN b[161]
    DIRECTION OUTPUT ;
    USE SIGNAL ;
    PORT
      LAYER M4 ;
        RECT  0 128.88 0.084 128.904 ;
    END
  END b[161]
  PIN b[162]
    DIRECTION OUTPUT ;
    USE SIGNAL ;
    PORT
      LAYER M4 ;
        RECT  0 129.024 0.084 129.048 ;
    END
  END b[162]
  PIN b[163]
    DIRECTION OUTPUT ;
    USE SIGNAL ;
    PORT
      LAYER M4 ;
        RECT  0 129.168 0.084 129.192 ;
    END
  END b[163]
  PIN b[164]
    DIRECTION OUTPUT ;
    USE SIGNAL ;
    PORT
      LAYER M4 ;
        RECT  0 129.312 0.084 129.336 ;
    END
  END b[164]
  PIN b[165]
    DIRECTION OUTPUT ;
    USE SIGNAL ;
    PORT
      LAYER M4 ;
        RECT  0 129.456 0.084 129.48 ;
    END
  END b[165]
  PIN b[166]
    DIRECTION OUTPUT ;
    USE SIGNAL ;
    PORT
      LAYER M4 ;
        RECT  0 129.6 0.084 129.624 ;
    END
  END b[166]
  PIN b[167]
    DIRECTION OUTPUT ;
    USE SIGNAL ;
    PORT
      LAYER M4 ;
        RECT  0 129.744 0.084 129.768 ;
    END
  END b[167]
  PIN b[168]
    DIRECTION OUTPUT ;
    USE SIGNAL ;
    PORT
      LAYER M4 ;
        RECT  0 129.888 0.084 129.912 ;
    END
  END b[168]
  PIN b[169]
    DIRECTION OUTPUT ;
    USE SIGNAL ;
    PORT
      LAYER M4 ;
        RECT  0 130.032 0.084 130.056 ;
    END
  END b[169]
  PIN b[16]
    DIRECTION OUTPUT ;
    USE SIGNAL ;
    PORT
      LAYER M4 ;
        RECT  0 33.984 0.084 34.008 ;
    END
  END b[16]
  PIN b[170]
    DIRECTION OUTPUT ;
    USE SIGNAL ;
    PORT
      LAYER M4 ;
        RECT  0 130.176 0.084 130.2 ;
    END
  END b[170]
  PIN b[171]
    DIRECTION OUTPUT ;
    USE SIGNAL ;
    PORT
      LAYER M4 ;
        RECT  0 130.32 0.084 130.344 ;
    END
  END b[171]
  PIN b[172]
    DIRECTION OUTPUT ;
    USE SIGNAL ;
    PORT
      LAYER M4 ;
        RECT  0 130.464 0.084 130.488 ;
    END
  END b[172]
  PIN b[173]
    DIRECTION OUTPUT ;
    USE SIGNAL ;
    PORT
      LAYER M4 ;
        RECT  0 130.608 0.084 130.632 ;
    END
  END b[173]
  PIN b[174]
    DIRECTION OUTPUT ;
    USE SIGNAL ;
    PORT
      LAYER M4 ;
        RECT  0 130.752 0.084 130.776 ;
    END
  END b[174]
  PIN b[175]
    DIRECTION OUTPUT ;
    USE SIGNAL ;
    PORT
      LAYER M4 ;
        RECT  0 130.896 0.084 130.92 ;
    END
  END b[175]
  PIN b[176]
    DIRECTION OUTPUT ;
    USE SIGNAL ;
    PORT
      LAYER M4 ;
        RECT  0 131.04 0.084 131.064 ;
    END
  END b[176]
  PIN b[177]
    DIRECTION OUTPUT ;
    USE SIGNAL ;
    PORT
      LAYER M4 ;
        RECT  0 131.184 0.084 131.208 ;
    END
  END b[177]
  PIN b[178]
    DIRECTION OUTPUT ;
    USE SIGNAL ;
    PORT
      LAYER M4 ;
        RECT  0 131.328 0.084 131.352 ;
    END
  END b[178]
  PIN b[179]
    DIRECTION OUTPUT ;
    USE SIGNAL ;
    PORT
      LAYER M4 ;
        RECT  0 131.472 0.084 131.496 ;
    END
  END b[179]
  PIN b[17]
    DIRECTION OUTPUT ;
    USE SIGNAL ;
    PORT
      LAYER M4 ;
        RECT  0 34.128 0.084 34.152 ;
    END
  END b[17]
  PIN b[180]
    DIRECTION OUTPUT ;
    USE SIGNAL ;
    PORT
      LAYER M4 ;
        RECT  0 131.616 0.084 131.64 ;
    END
  END b[180]
  PIN b[181]
    DIRECTION OUTPUT ;
    USE SIGNAL ;
    PORT
      LAYER M4 ;
        RECT  0 131.76 0.084 131.784 ;
    END
  END b[181]
  PIN b[18]
    DIRECTION OUTPUT ;
    USE SIGNAL ;
    PORT
      LAYER M4 ;
        RECT  0 34.272 0.084 34.296 ;
    END
  END b[18]
  PIN b[19]
    DIRECTION OUTPUT ;
    USE SIGNAL ;
    PORT
      LAYER M4 ;
        RECT  0 34.416 0.084 34.44 ;
    END
  END b[19]
  PIN b[1]
    DIRECTION OUTPUT ;
    USE SIGNAL ;
    PORT
      LAYER M4 ;
        RECT  0 31.824 0.084 31.848 ;
    END
  END b[1]
  PIN b[20]
    DIRECTION OUTPUT ;
    USE SIGNAL ;
    PORT
      LAYER M4 ;
        RECT  0 34.56 0.084 34.584 ;
    END
  END b[20]
  PIN b[21]
    DIRECTION OUTPUT ;
    USE SIGNAL ;
    PORT
      LAYER M4 ;
        RECT  0 34.704 0.084 34.728 ;
    END
  END b[21]
  PIN b[22]
    DIRECTION OUTPUT ;
    USE SIGNAL ;
    PORT
      LAYER M4 ;
        RECT  0 34.848 0.084 34.872 ;
    END
  END b[22]
  PIN b[23]
    DIRECTION OUTPUT ;
    USE SIGNAL ;
    PORT
      LAYER M4 ;
        RECT  0 34.992 0.084 35.016 ;
    END
  END b[23]
  PIN b[24]
    DIRECTION OUTPUT ;
    USE SIGNAL ;
    PORT
      LAYER M4 ;
        RECT  0 35.136 0.084 35.16 ;
    END
  END b[24]
  PIN b[25]
    DIRECTION OUTPUT ;
    USE SIGNAL ;
    PORT
      LAYER M4 ;
        RECT  0 35.28 0.084 35.304 ;
    END
  END b[25]
  PIN b[26]
    DIRECTION OUTPUT ;
    USE SIGNAL ;
    PORT
      LAYER M4 ;
        RECT  0 35.424 0.084 35.448 ;
    END
  END b[26]
  PIN b[27]
    DIRECTION OUTPUT ;
    USE SIGNAL ;
    PORT
      LAYER M4 ;
        RECT  0 35.568 0.084 35.592 ;
    END
  END b[27]
  PIN b[28]
    DIRECTION OUTPUT ;
    USE SIGNAL ;
    PORT
      LAYER M4 ;
        RECT  0 35.712 0.084 35.736 ;
    END
  END b[28]
  PIN b[29]
    DIRECTION OUTPUT ;
    USE SIGNAL ;
    PORT
      LAYER M4 ;
        RECT  0 35.856 0.084 35.88 ;
    END
  END b[29]
  PIN b[2]
    DIRECTION OUTPUT ;
    USE SIGNAL ;
    PORT
      LAYER M4 ;
        RECT  0 31.968 0.084 31.992 ;
    END
  END b[2]
  PIN b[30]
    DIRECTION OUTPUT ;
    USE SIGNAL ;
    PORT
      LAYER M4 ;
        RECT  0 36 0.084 36.024 ;
    END
  END b[30]
  PIN b[31]
    DIRECTION OUTPUT ;
    USE SIGNAL ;
    PORT
      LAYER M4 ;
        RECT  0 36.144 0.084 36.168 ;
    END
  END b[31]
  PIN b[32]
    DIRECTION OUTPUT ;
    USE SIGNAL ;
    PORT
      LAYER M4 ;
        RECT  0 40.896 0.084 40.92 ;
    END
  END b[32]
  PIN b[33]
    DIRECTION OUTPUT ;
    USE SIGNAL ;
    PORT
      LAYER M4 ;
        RECT  0 41.04 0.084 41.064 ;
    END
  END b[33]
  PIN b[34]
    DIRECTION OUTPUT ;
    USE SIGNAL ;
    PORT
      LAYER M4 ;
        RECT  0 41.184 0.084 41.208 ;
    END
  END b[34]
  PIN b[35]
    DIRECTION OUTPUT ;
    USE SIGNAL ;
    PORT
      LAYER M4 ;
        RECT  0 41.328 0.084 41.352 ;
    END
  END b[35]
  PIN b[36]
    DIRECTION OUTPUT ;
    USE SIGNAL ;
    PORT
      LAYER M4 ;
        RECT  0 41.472 0.084 41.496 ;
    END
  END b[36]
  PIN b[37]
    DIRECTION OUTPUT ;
    USE SIGNAL ;
    PORT
      LAYER M4 ;
        RECT  0 41.616 0.084 41.64 ;
    END
  END b[37]
  PIN b[38]
    DIRECTION OUTPUT ;
    USE SIGNAL ;
    PORT
      LAYER M4 ;
        RECT  0 41.76 0.084 41.784 ;
    END
  END b[38]
  PIN b[39]
    DIRECTION OUTPUT ;
    USE SIGNAL ;
    PORT
      LAYER M4 ;
        RECT  0 41.904 0.084 41.928 ;
    END
  END b[39]
  PIN b[3]
    DIRECTION OUTPUT ;
    USE SIGNAL ;
    PORT
      LAYER M4 ;
        RECT  0 32.112 0.084 32.136 ;
    END
  END b[3]
  PIN b[40]
    DIRECTION OUTPUT ;
    USE SIGNAL ;
    PORT
      LAYER M4 ;
        RECT  0 42.048 0.084 42.072 ;
    END
  END b[40]
  PIN b[41]
    DIRECTION OUTPUT ;
    USE SIGNAL ;
    PORT
      LAYER M4 ;
        RECT  0 42.192 0.084 42.216 ;
    END
  END b[41]
  PIN b[42]
    DIRECTION OUTPUT ;
    USE SIGNAL ;
    PORT
      LAYER M4 ;
        RECT  0 42.336 0.084 42.36 ;
    END
  END b[42]
  PIN b[43]
    DIRECTION OUTPUT ;
    USE SIGNAL ;
    PORT
      LAYER M4 ;
        RECT  0 42.48 0.084 42.504 ;
    END
  END b[43]
  PIN b[44]
    DIRECTION OUTPUT ;
    USE SIGNAL ;
    PORT
      LAYER M4 ;
        RECT  0 42.624 0.084 42.648 ;
    END
  END b[44]
  PIN b[45]
    DIRECTION OUTPUT ;
    USE SIGNAL ;
    PORT
      LAYER M4 ;
        RECT  0 42.768 0.084 42.792 ;
    END
  END b[45]
  PIN b[46]
    DIRECTION OUTPUT ;
    USE SIGNAL ;
    PORT
      LAYER M4 ;
        RECT  0 42.912 0.084 42.936 ;
    END
  END b[46]
  PIN b[47]
    DIRECTION OUTPUT ;
    USE SIGNAL ;
    PORT
      LAYER M4 ;
        RECT  0 43.056 0.084 43.08 ;
    END
  END b[47]
  PIN b[48]
    DIRECTION OUTPUT ;
    USE SIGNAL ;
    PORT
      LAYER M4 ;
        RECT  0 43.2 0.084 43.224 ;
    END
  END b[48]
  PIN b[49]
    DIRECTION OUTPUT ;
    USE SIGNAL ;
    PORT
      LAYER M4 ;
        RECT  0 43.344 0.084 43.368 ;
    END
  END b[49]
  PIN b[4]
    DIRECTION OUTPUT ;
    USE SIGNAL ;
    PORT
      LAYER M4 ;
        RECT  0 32.256 0.084 32.28 ;
    END
  END b[4]
  PIN b[50]
    DIRECTION OUTPUT ;
    USE SIGNAL ;
    PORT
      LAYER M4 ;
        RECT  0 43.488 0.084 43.512 ;
    END
  END b[50]
  PIN b[51]
    DIRECTION OUTPUT ;
    USE SIGNAL ;
    PORT
      LAYER M4 ;
        RECT  0 43.632 0.084 43.656 ;
    END
  END b[51]
  PIN b[52]
    DIRECTION OUTPUT ;
    USE SIGNAL ;
    PORT
      LAYER M4 ;
        RECT  0 43.776 0.084 43.8 ;
    END
  END b[52]
  PIN b[53]
    DIRECTION OUTPUT ;
    USE SIGNAL ;
    PORT
      LAYER M4 ;
        RECT  0 43.92 0.084 43.944 ;
    END
  END b[53]
  PIN b[54]
    DIRECTION OUTPUT ;
    USE SIGNAL ;
    PORT
      LAYER M4 ;
        RECT  0 44.064 0.084 44.088 ;
    END
  END b[54]
  PIN b[55]
    DIRECTION OUTPUT ;
    USE SIGNAL ;
    PORT
      LAYER M4 ;
        RECT  0 44.208 0.084 44.232 ;
    END
  END b[55]
  PIN b[56]
    DIRECTION OUTPUT ;
    USE SIGNAL ;
    PORT
      LAYER M4 ;
        RECT  0 44.352 0.084 44.376 ;
    END
  END b[56]
  PIN b[57]
    DIRECTION OUTPUT ;
    USE SIGNAL ;
    PORT
      LAYER M4 ;
        RECT  0 44.496 0.084 44.52 ;
    END
  END b[57]
  PIN b[58]
    DIRECTION OUTPUT ;
    USE SIGNAL ;
    PORT
      LAYER M4 ;
        RECT  0 44.64 0.084 44.664 ;
    END
  END b[58]
  PIN b[59]
    DIRECTION OUTPUT ;
    USE SIGNAL ;
    PORT
      LAYER M4 ;
        RECT  0 44.784 0.084 44.808 ;
    END
  END b[59]
  PIN b[5]
    DIRECTION OUTPUT ;
    USE SIGNAL ;
    PORT
      LAYER M4 ;
        RECT  0 32.4 0.084 32.424 ;
    END
  END b[5]
  PIN b[60]
    DIRECTION OUTPUT ;
    USE SIGNAL ;
    PORT
      LAYER M4 ;
        RECT  0 44.928 0.084 44.952 ;
    END
  END b[60]
  PIN b[61]
    DIRECTION OUTPUT ;
    USE SIGNAL ;
    PORT
      LAYER M4 ;
        RECT  0 45.072 0.084 45.096 ;
    END
  END b[61]
  PIN b[62]
    DIRECTION OUTPUT ;
    USE SIGNAL ;
    PORT
      LAYER M4 ;
        RECT  0 45.216 0.084 45.24 ;
    END
  END b[62]
  PIN b[63]
    DIRECTION OUTPUT ;
    USE SIGNAL ;
    PORT
      LAYER M4 ;
        RECT  0 45.36 0.084 45.384 ;
    END
  END b[63]
  PIN b[64]
    DIRECTION OUTPUT ;
    USE SIGNAL ;
    PORT
      LAYER M4 ;
        RECT  0 78.912 0.084 78.936 ;
    END
  END b[64]
  PIN b[65]
    DIRECTION OUTPUT ;
    USE SIGNAL ;
    PORT
      LAYER M4 ;
        RECT  0 79.056 0.084 79.08 ;
    END
  END b[65]
  PIN b[66]
    DIRECTION OUTPUT ;
    USE SIGNAL ;
    PORT
      LAYER M4 ;
        RECT  0 79.2 0.084 79.224 ;
    END
  END b[66]
  PIN b[67]
    DIRECTION OUTPUT ;
    USE SIGNAL ;
    PORT
      LAYER M4 ;
        RECT  0 79.344 0.084 79.368 ;
    END
  END b[67]
  PIN b[68]
    DIRECTION OUTPUT ;
    USE SIGNAL ;
    PORT
      LAYER M4 ;
        RECT  0 79.488 0.084 79.512 ;
    END
  END b[68]
  PIN b[69]
    DIRECTION OUTPUT ;
    USE SIGNAL ;
    PORT
      LAYER M4 ;
        RECT  0 79.632 0.084 79.656 ;
    END
  END b[69]
  PIN b[6]
    DIRECTION OUTPUT ;
    USE SIGNAL ;
    PORT
      LAYER M4 ;
        RECT  0 32.544 0.084 32.568 ;
    END
  END b[6]
  PIN b[70]
    DIRECTION OUTPUT ;
    USE SIGNAL ;
    PORT
      LAYER M4 ;
        RECT  0 79.776 0.084 79.8 ;
    END
  END b[70]
  PIN b[71]
    DIRECTION OUTPUT ;
    USE SIGNAL ;
    PORT
      LAYER M4 ;
        RECT  0 79.92 0.084 79.944 ;
    END
  END b[71]
  PIN b[72]
    DIRECTION OUTPUT ;
    USE SIGNAL ;
    PORT
      LAYER M4 ;
        RECT  0 80.064 0.084 80.088 ;
    END
  END b[72]
  PIN b[73]
    DIRECTION OUTPUT ;
    USE SIGNAL ;
    PORT
      LAYER M4 ;
        RECT  0 80.208 0.084 80.232 ;
    END
  END b[73]
  PIN b[74]
    DIRECTION OUTPUT ;
    USE SIGNAL ;
    PORT
      LAYER M4 ;
        RECT  0 80.352 0.084 80.376 ;
    END
  END b[74]
  PIN b[75]
    DIRECTION OUTPUT ;
    USE SIGNAL ;
    PORT
      LAYER M4 ;
        RECT  0 80.496 0.084 80.52 ;
    END
  END b[75]
  PIN b[76]
    DIRECTION OUTPUT ;
    USE SIGNAL ;
    PORT
      LAYER M4 ;
        RECT  0 80.64 0.084 80.664 ;
    END
  END b[76]
  PIN b[77]
    DIRECTION OUTPUT ;
    USE SIGNAL ;
    PORT
      LAYER M4 ;
        RECT  0 80.784 0.084 80.808 ;
    END
  END b[77]
  PIN b[78]
    DIRECTION OUTPUT ;
    USE SIGNAL ;
    PORT
      LAYER M4 ;
        RECT  0 80.928 0.084 80.952 ;
    END
  END b[78]
  PIN b[79]
    DIRECTION OUTPUT ;
    USE SIGNAL ;
    PORT
      LAYER M4 ;
        RECT  0 81.072 0.084 81.096 ;
    END
  END b[79]
  PIN b[7]
    DIRECTION OUTPUT ;
    USE SIGNAL ;
    PORT
      LAYER M4 ;
        RECT  0 32.688 0.084 32.712 ;
    END
  END b[7]
  PIN b[80]
    DIRECTION OUTPUT ;
    USE SIGNAL ;
    PORT
      LAYER M4 ;
        RECT  0 81.216 0.084 81.24 ;
    END
  END b[80]
  PIN b[81]
    DIRECTION OUTPUT ;
    USE SIGNAL ;
    PORT
      LAYER M4 ;
        RECT  0 81.36 0.084 81.384 ;
    END
  END b[81]
  PIN b[82]
    DIRECTION OUTPUT ;
    USE SIGNAL ;
    PORT
      LAYER M4 ;
        RECT  0 81.504 0.084 81.528 ;
    END
  END b[82]
  PIN b[83]
    DIRECTION OUTPUT ;
    USE SIGNAL ;
    PORT
      LAYER M4 ;
        RECT  0 81.648 0.084 81.672 ;
    END
  END b[83]
  PIN b[84]
    DIRECTION OUTPUT ;
    USE SIGNAL ;
    PORT
      LAYER M4 ;
        RECT  0 81.792 0.084 81.816 ;
    END
  END b[84]
  PIN b[85]
    DIRECTION OUTPUT ;
    USE SIGNAL ;
    PORT
      LAYER M4 ;
        RECT  0 81.936 0.084 81.96 ;
    END
  END b[85]
  PIN b[86]
    DIRECTION OUTPUT ;
    USE SIGNAL ;
    PORT
      LAYER M4 ;
        RECT  0 82.08 0.084 82.104 ;
    END
  END b[86]
  PIN b[87]
    DIRECTION OUTPUT ;
    USE SIGNAL ;
    PORT
      LAYER M4 ;
        RECT  0 82.224 0.084 82.248 ;
    END
  END b[87]
  PIN b[88]
    DIRECTION OUTPUT ;
    USE SIGNAL ;
    PORT
      LAYER M4 ;
        RECT  0 82.368 0.084 82.392 ;
    END
  END b[88]
  PIN b[89]
    DIRECTION OUTPUT ;
    USE SIGNAL ;
    PORT
      LAYER M4 ;
        RECT  0 82.512 0.084 82.536 ;
    END
  END b[89]
  PIN b[8]
    DIRECTION OUTPUT ;
    USE SIGNAL ;
    PORT
      LAYER M4 ;
        RECT  0 32.832 0.084 32.856 ;
    END
  END b[8]
  PIN b[90]
    DIRECTION OUTPUT ;
    USE SIGNAL ;
    PORT
      LAYER M4 ;
        RECT  0 82.656 0.084 82.68 ;
    END
  END b[90]
  PIN b[91]
    DIRECTION OUTPUT ;
    USE SIGNAL ;
    PORT
      LAYER M4 ;
        RECT  0 82.8 0.084 82.824 ;
    END
  END b[91]
  PIN b[92]
    DIRECTION OUTPUT ;
    USE SIGNAL ;
    PORT
      LAYER M4 ;
        RECT  0 82.944 0.084 82.968 ;
    END
  END b[92]
  PIN b[93]
    DIRECTION OUTPUT ;
    USE SIGNAL ;
    PORT
      LAYER M4 ;
        RECT  0 83.088 0.084 83.112 ;
    END
  END b[93]
  PIN b[94]
    DIRECTION OUTPUT ;
    USE SIGNAL ;
    PORT
      LAYER M4 ;
        RECT  0 83.232 0.084 83.256 ;
    END
  END b[94]
  PIN b[95]
    DIRECTION OUTPUT ;
    USE SIGNAL ;
    PORT
      LAYER M4 ;
        RECT  0 83.376 0.084 83.4 ;
    END
  END b[95]
  PIN b[96]
    DIRECTION OUTPUT ;
    USE SIGNAL ;
    PORT
      LAYER M4 ;
        RECT  0 84.672 0.084 84.696 ;
    END
  END b[96]
  PIN b[97]
    DIRECTION OUTPUT ;
    USE SIGNAL ;
    PORT
      LAYER M4 ;
        RECT  0 84.816 0.084 84.84 ;
    END
  END b[97]
  PIN b[98]
    DIRECTION OUTPUT ;
    USE SIGNAL ;
    PORT
      LAYER M4 ;
        RECT  0 84.96 0.084 84.984 ;
    END
  END b[98]
  PIN b[99]
    DIRECTION OUTPUT ;
    USE SIGNAL ;
    PORT
      LAYER M4 ;
        RECT  0 85.104 0.084 85.128 ;
    END
  END b[99]
  PIN b[9]
    DIRECTION OUTPUT ;
    USE SIGNAL ;
    PORT
      LAYER M4 ;
        RECT  0 32.976 0.084 33 ;
    END
  END b[9]
  PIN ck
    DIRECTION INPUT ;
    USE SIGNAL ;
    PORT
      LAYER M3 ;
        RECT  37.908 170.603 37.926 170.64 ;
    END
  END ck
  PIN ck_s
    DIRECTION INPUT ;
    USE SIGNAL ;
    PORT
      LAYER M3 ;
        RECT  38.016 170.603 38.034 170.64 ;
    END
  END ck_s
  PIN en
    DIRECTION INPUT ;
    USE SIGNAL ;
    PORT
      LAYER M3 ;
        RECT  38.124 170.603 38.142 170.64 ;
    END
  END en
  PIN fault
    DIRECTION OUTPUT ;
    USE SIGNAL ;
    PORT
      LAYER M3 ;
        RECT  38.232 170.603 38.25 170.64 ;
    END
  END fault
  PIN k0
    DIRECTION INPUT ;
    USE SIGNAL ;
    PORT
      LAYER M3 ;
        RECT  38.34 170.603 38.358 170.64 ;
    END
  END k0
  PIN k1
    DIRECTION INPUT ;
    USE SIGNAL ;
    PORT
      LAYER M3 ;
        RECT  38.448 170.603 38.466 170.64 ;
    END
  END k1
  PIN k2
    DIRECTION INPUT ;
    USE SIGNAL ;
    PORT
      LAYER M3 ;
        RECT  38.556 170.603 38.574 170.64 ;
    END
  END k2
  PIN k3
    DIRECTION INPUT ;
    USE SIGNAL ;
    PORT
      LAYER M3 ;
        RECT  38.664 170.603 38.682 170.64 ;
    END
  END k3
  PIN rs
    DIRECTION INPUT ;
    USE SIGNAL ;
    PORT
      LAYER M3 ;
        RECT  38.772 170.603 38.79 170.64 ;
    END
  END rs
  PIN tie_hi
    DIRECTION OUTPUT ;
    USE SIGNAL ;
    PORT
      LAYER M3 ;
        RECT  38.88 170.603 38.898 170.64 ;
    END
  END tie_hi
  PIN tie_lo
    DIRECTION OUTPUT ;
    USE SIGNAL ;
    PORT
      LAYER M3 ;
        RECT  38.988 170.603 39.006 170.64 ;
    END
  END tie_lo
  PIN VDD
    DIRECTION INOUT ;
    USE POWER ;
    PORT
      LAYER M5 ;
        RECT  94.392 2.151 94.512 168.489 ;
        RECT  91.692 2.151 91.812 168.489 ;
        RECT  88.992 2.151 89.112 168.489 ;
        RECT  86.292 2.151 86.412 168.489 ;
        RECT  83.592 2.151 83.712 168.489 ;
        RECT  80.892 2.151 81.012 168.489 ;
        RECT  78.192 2.151 78.312 168.489 ;
        RECT  75.492 2.151 75.612 168.489 ;
        RECT  72.792 2.151 72.912 168.489 ;
        RECT  70.092 2.151 70.212 168.489 ;
        RECT  67.392 2.151 67.512 168.489 ;
        RECT  64.692 2.151 64.812 168.489 ;
        RECT  61.992 2.151 62.112 168.489 ;
        RECT  59.292 2.151 59.412 168.489 ;
        RECT  56.592 2.151 56.712 168.489 ;
        RECT  53.892 2.151 54.012 168.489 ;
        RECT  51.192 2.151 51.312 168.489 ;
        RECT  48.492 2.151 48.612 168.489 ;
        RECT  45.792 2.151 45.912 168.489 ;
        RECT  43.092 2.151 43.212 168.489 ;
        RECT  40.392 2.151 40.512 168.489 ;
        RECT  37.692 2.151 37.812 168.489 ;
        RECT  34.992 2.151 35.112 168.489 ;
        RECT  32.292 2.151 32.412 168.489 ;
        RECT  29.592 2.151 29.712 168.489 ;
        RECT  26.892 2.151 27.012 168.489 ;
        RECT  24.192 2.151 24.312 168.489 ;
        RECT  21.492 2.151 21.612 168.489 ;
        RECT  18.792 2.151 18.912 168.489 ;
        RECT  16.092 2.151 16.212 168.489 ;
        RECT  13.392 2.151 13.512 168.489 ;
        RECT  10.692 2.151 10.812 168.489 ;
        RECT  7.992 2.151 8.112 168.489 ;
        RECT  5.292 2.151 5.412 168.489 ;
        RECT  2.592 2.151 2.712 168.489 ;
    END
  END VDD
  PIN VSS
    DIRECTION INOUT ;
    USE GROUND ;
    PORT
      LAYER M5 ;
        RECT  94.2 2.137 94.32 168.503 ;
        RECT  91.5 2.137 91.62 168.503 ;
        RECT  88.8 2.137 88.92 168.503 ;
        RECT  86.1 2.137 86.22 168.503 ;
        RECT  83.4 2.137 83.52 168.503 ;
        RECT  80.7 2.137 80.82 168.503 ;
        RECT  78 2.137 78.12 168.503 ;
        RECT  75.3 2.137 75.42 168.503 ;
        RECT  72.6 2.137 72.72 168.503 ;
        RECT  69.9 2.137 70.02 168.503 ;
        RECT  67.2 2.137 67.32 168.503 ;
        RECT  64.5 2.137 64.62 168.503 ;
        RECT  61.8 2.137 61.92 168.503 ;
        RECT  59.1 2.137 59.22 168.503 ;
        RECT  56.4 2.137 56.52 168.503 ;
        RECT  53.7 2.137 53.82 168.503 ;
        RECT  51 2.137 51.12 168.503 ;
        RECT  48.3 2.137 48.42 168.503 ;
        RECT  45.6 2.137 45.72 168.503 ;
        RECT  42.9 2.137 43.02 168.503 ;
        RECT  40.2 2.137 40.32 168.503 ;
        RECT  37.5 2.137 37.62 168.503 ;
        RECT  34.8 2.137 34.92 168.503 ;
        RECT  32.1 2.137 32.22 168.503 ;
        RECT  29.4 2.137 29.52 168.503 ;
        RECT  26.7 2.137 26.82 168.503 ;
        RECT  24 2.137 24.12 168.503 ;
        RECT  21.3 2.137 21.42 168.503 ;
        RECT  18.6 2.137 18.72 168.503 ;
        RECT  15.9 2.137 16.02 168.503 ;
        RECT  13.2 2.137 13.32 168.503 ;
        RECT  10.5 2.137 10.62 168.503 ;
        RECT  7.8 2.137 7.92 168.503 ;
        RECT  5.1 2.137 5.22 168.503 ;
        RECT  2.4 2.137 2.52 168.503 ;
    END
  END VSS
  OBS
    LAYER RVTN ;
     RECT  2.16 2.16 96.12 2.295 ;
     RECT  2.16 2.565 96.12 2.835 ;
     RECT  2.16 3.105 96.12 3.375 ;
     RECT  2.16 3.645 96.12 3.915 ;
     RECT  2.16 4.185 96.12 4.455 ;
     RECT  2.16 4.725 96.12 4.995 ;
     RECT  2.16 5.265 96.12 5.535 ;
     RECT  2.16 5.805 96.12 6.075 ;
     RECT  2.16 6.345 96.12 6.615 ;
     RECT  2.16 6.885 96.12 7.155 ;
     RECT  2.16 7.425 96.12 7.695 ;
     RECT  2.16 7.965 96.12 8.235 ;
     RECT  2.16 8.505 96.12 8.775 ;
     RECT  2.16 9.045 96.12 9.315 ;
     RECT  2.16 9.585 96.12 9.855 ;
     RECT  2.16 10.125 96.12 10.395 ;
     RECT  2.16 10.665 96.12 10.935 ;
     RECT  2.16 11.205 96.12 11.475 ;
     RECT  2.16 11.745 96.12 12.015 ;
     RECT  2.16 12.285 96.12 12.555 ;
     RECT  2.16 12.825 96.12 13.095 ;
     RECT  2.16 13.365 96.12 13.635 ;
     RECT  2.16 13.905 96.12 14.175 ;
     RECT  2.16 14.445 96.12 14.715 ;
     RECT  2.16 14.985 96.12 15.255 ;
     RECT  2.16 15.525 96.12 15.795 ;
     RECT  2.16 16.065 96.12 16.335 ;
     RECT  2.16 16.605 96.12 16.875 ;
     RECT  2.16 17.145 96.12 17.415 ;
     RECT  2.16 17.685 96.12 17.955 ;
     RECT  2.16 18.225 96.12 18.495 ;
     RECT  2.16 18.765 96.12 19.035 ;
     RECT  2.16 19.305 96.12 19.575 ;
     RECT  2.16 19.845 96.12 20.115 ;
     RECT  2.16 20.385 96.12 20.655 ;
     RECT  2.16 20.925 96.12 21.195 ;
     RECT  2.16 21.465 96.12 21.735 ;
     RECT  2.16 22.005 96.12 22.275 ;
     RECT  2.16 22.545 96.12 22.815 ;
     RECT  2.16 23.085 96.12 23.355 ;
     RECT  2.16 23.625 96.12 23.895 ;
     RECT  2.16 24.165 96.12 24.435 ;
     RECT  2.16 24.705 96.12 24.975 ;
     RECT  2.16 25.245 96.12 25.515 ;
     RECT  2.16 25.785 96.12 26.055 ;
     RECT  2.16 26.325 96.12 26.595 ;
     RECT  2.16 26.865 96.12 27.135 ;
     RECT  2.16 27.405 96.12 27.675 ;
     RECT  2.16 27.945 96.12 28.215 ;
     RECT  2.16 28.485 96.12 28.755 ;
     RECT  2.16 29.025 96.12 29.295 ;
     RECT  2.16 29.565 96.12 29.835 ;
     RECT  2.16 30.105 96.12 30.375 ;
     RECT  2.16 30.645 96.12 30.915 ;
     RECT  2.16 31.185 96.12 31.455 ;
     RECT  2.16 31.725 96.12 31.995 ;
     RECT  2.16 32.265 96.12 32.535 ;
     RECT  2.16 32.805 96.12 33.075 ;
     RECT  2.16 33.345 96.12 33.615 ;
     RECT  2.16 33.885 96.12 34.155 ;
     RECT  2.16 34.425 96.12 34.695 ;
     RECT  2.16 34.965 96.12 35.235 ;
     RECT  2.16 35.505 96.12 35.775 ;
     RECT  2.16 36.045 96.12 36.315 ;
     RECT  2.16 36.585 96.12 36.855 ;
     RECT  2.16 37.125 96.12 37.395 ;
     RECT  2.16 37.665 96.12 37.935 ;
     RECT  2.16 38.205 96.12 38.475 ;
     RECT  2.16 38.745 96.12 39.015 ;
     RECT  2.16 39.285 96.12 39.555 ;
     RECT  2.16 39.825 96.12 40.095 ;
     RECT  2.16 40.365 96.12 40.635 ;
     RECT  2.16 40.905 96.12 41.04 ;
     RECT  2.16 41.04 41.148 41.175 ;
     RECT  77.22 41.04 96.12 41.175 ;
     RECT  2.16 41.445 41.148 41.715 ;
     RECT  77.22 41.445 96.12 41.715 ;
     RECT  2.16 41.985 41.148 42.255 ;
     RECT  77.22 41.985 96.12 42.255 ;
     RECT  2.16 42.525 41.148 42.795 ;
     RECT  77.22 42.525 96.12 42.795 ;
     RECT  2.16 43.065 41.148 43.335 ;
     RECT  77.22 43.065 96.12 43.335 ;
     RECT  2.16 43.605 41.148 43.875 ;
     RECT  77.22 43.605 96.12 43.875 ;
     RECT  2.16 44.145 41.148 44.415 ;
     RECT  77.22 44.145 96.12 44.415 ;
     RECT  2.16 44.685 41.148 44.955 ;
     RECT  77.22 44.685 96.12 44.955 ;
     RECT  2.16 45.225 41.148 45.495 ;
     RECT  77.22 45.225 96.12 45.495 ;
     RECT  2.16 45.765 41.148 46.035 ;
     RECT  77.22 45.765 96.12 46.035 ;
     RECT  2.16 46.305 41.148 46.575 ;
     RECT  77.22 46.305 96.12 46.575 ;
     RECT  2.16 46.845 41.148 47.115 ;
     RECT  77.22 46.845 96.12 47.115 ;
     RECT  2.16 47.385 41.148 47.655 ;
     RECT  77.22 47.385 96.12 47.655 ;
     RECT  2.16 47.925 41.148 48.195 ;
     RECT  77.22 47.925 96.12 48.195 ;
     RECT  2.16 48.465 41.148 48.735 ;
     RECT  77.22 48.465 96.12 48.735 ;
     RECT  2.16 49.005 41.148 49.275 ;
     RECT  77.22 49.005 96.12 49.275 ;
     RECT  2.16 49.545 41.148 49.815 ;
     RECT  77.22 49.545 96.12 49.815 ;
     RECT  2.16 50.085 41.148 50.355 ;
     RECT  77.22 50.085 96.12 50.355 ;
     RECT  2.16 50.625 41.148 50.895 ;
     RECT  77.22 50.625 96.12 50.895 ;
     RECT  2.16 51.165 41.148 51.435 ;
     RECT  77.22 51.165 96.12 51.435 ;
     RECT  2.16 51.705 41.148 51.975 ;
     RECT  77.22 51.705 96.12 51.975 ;
     RECT  2.16 52.245 41.148 52.515 ;
     RECT  77.22 52.245 96.12 52.515 ;
     RECT  2.16 52.785 41.148 53.055 ;
     RECT  77.22 52.785 96.12 53.055 ;
     RECT  2.16 53.325 41.148 53.595 ;
     RECT  77.22 53.325 96.12 53.595 ;
     RECT  2.16 53.865 41.148 54.135 ;
     RECT  77.22 53.865 96.12 54.135 ;
     RECT  2.16 54.405 41.148 54.675 ;
     RECT  77.22 54.405 96.12 54.675 ;
     RECT  2.16 54.945 41.148 55.215 ;
     RECT  77.22 54.945 96.12 55.215 ;
     RECT  2.16 55.485 41.148 55.755 ;
     RECT  77.22 55.485 96.12 55.755 ;
     RECT  2.16 56.025 41.148 56.295 ;
     RECT  77.22 56.025 96.12 56.295 ;
     RECT  2.16 56.565 41.148 56.835 ;
     RECT  77.22 56.565 96.12 56.835 ;
     RECT  2.16 57.105 41.148 57.375 ;
     RECT  77.22 57.105 96.12 57.375 ;
     RECT  2.16 57.645 41.148 57.915 ;
     RECT  77.22 57.645 96.12 57.915 ;
     RECT  2.16 58.185 41.148 58.455 ;
     RECT  77.22 58.185 96.12 58.455 ;
     RECT  2.16 58.725 41.148 58.995 ;
     RECT  77.22 58.725 96.12 58.995 ;
     RECT  2.16 59.265 41.148 59.535 ;
     RECT  77.22 59.265 96.12 59.535 ;
     RECT  2.16 59.805 41.148 60.075 ;
     RECT  77.22 59.805 96.12 60.075 ;
     RECT  2.16 60.345 41.148 60.615 ;
     RECT  77.22 60.345 96.12 60.615 ;
     RECT  2.16 60.885 41.148 61.155 ;
     RECT  77.22 60.885 96.12 61.155 ;
     RECT  2.16 61.425 41.148 61.695 ;
     RECT  77.22 61.425 96.12 61.695 ;
     RECT  2.16 61.965 41.148 62.235 ;
     RECT  77.22 61.965 96.12 62.235 ;
     RECT  2.16 62.505 41.148 62.64 ;
     RECT  77.22 62.505 96.12 62.64 ;
     RECT  2.16 62.64 96.12 62.775 ;
     RECT  2.16 63.045 96.12 63.315 ;
     RECT  2.16 63.585 96.12 63.855 ;
     RECT  2.16 64.125 96.12 64.395 ;
     RECT  2.16 64.665 96.12 64.935 ;
     RECT  2.16 65.205 96.12 65.475 ;
     RECT  2.16 65.745 96.12 66.015 ;
     RECT  2.16 66.285 96.12 66.555 ;
     RECT  2.16 66.825 96.12 67.095 ;
     RECT  2.16 67.365 96.12 67.635 ;
     RECT  2.16 67.905 96.12 68.175 ;
     RECT  2.16 68.445 96.12 68.715 ;
     RECT  2.16 68.985 96.12 69.255 ;
     RECT  2.16 69.525 96.12 69.795 ;
     RECT  2.16 70.065 96.12 70.335 ;
     RECT  2.16 70.605 96.12 70.875 ;
     RECT  2.16 71.145 96.12 71.415 ;
     RECT  2.16 71.685 96.12 71.955 ;
     RECT  2.16 72.225 96.12 72.495 ;
     RECT  2.16 72.765 96.12 73.035 ;
     RECT  2.16 73.305 96.12 73.575 ;
     RECT  2.16 73.845 96.12 74.115 ;
     RECT  2.16 74.385 96.12 74.655 ;
     RECT  2.16 74.925 96.12 75.195 ;
     RECT  2.16 75.465 96.12 75.735 ;
     RECT  2.16 76.005 96.12 76.275 ;
     RECT  2.16 76.545 96.12 76.815 ;
     RECT  2.16 77.085 96.12 77.355 ;
     RECT  2.16 77.625 96.12 77.895 ;
     RECT  2.16 78.165 96.12 78.435 ;
     RECT  2.16 78.705 96.12 78.975 ;
     RECT  2.16 79.245 96.12 79.515 ;
     RECT  2.16 79.785 96.12 80.055 ;
     RECT  2.16 80.325 96.12 80.595 ;
     RECT  2.16 80.865 96.12 81.135 ;
     RECT  2.16 81.405 96.12 81.675 ;
     RECT  2.16 81.945 96.12 82.215 ;
     RECT  2.16 82.485 96.12 82.755 ;
     RECT  2.16 83.025 96.12 83.295 ;
     RECT  2.16 83.565 96.12 83.835 ;
     RECT  2.16 84.105 96.12 84.24 ;
     RECT  2.16 84.24 41.148 84.375 ;
     RECT  77.22 84.24 96.12 84.375 ;
     RECT  2.16 84.645 41.148 84.915 ;
     RECT  77.22 84.645 96.12 84.915 ;
     RECT  2.16 85.185 41.148 85.455 ;
     RECT  77.22 85.185 96.12 85.455 ;
     RECT  2.16 85.725 41.148 85.995 ;
     RECT  77.22 85.725 96.12 85.995 ;
     RECT  2.16 86.265 41.148 86.535 ;
     RECT  77.22 86.265 96.12 86.535 ;
     RECT  2.16 86.805 41.148 87.075 ;
     RECT  77.22 86.805 96.12 87.075 ;
     RECT  2.16 87.345 41.148 87.615 ;
     RECT  77.22 87.345 96.12 87.615 ;
     RECT  2.16 87.885 41.148 88.155 ;
     RECT  77.22 87.885 96.12 88.155 ;
     RECT  2.16 88.425 41.148 88.695 ;
     RECT  77.22 88.425 96.12 88.695 ;
     RECT  2.16 88.965 41.148 89.235 ;
     RECT  77.22 88.965 96.12 89.235 ;
     RECT  2.16 89.505 41.148 89.775 ;
     RECT  77.22 89.505 96.12 89.775 ;
     RECT  2.16 90.045 41.148 90.315 ;
     RECT  77.22 90.045 96.12 90.315 ;
     RECT  2.16 90.585 41.148 90.855 ;
     RECT  77.22 90.585 96.12 90.855 ;
     RECT  2.16 91.125 41.148 91.395 ;
     RECT  77.22 91.125 96.12 91.395 ;
     RECT  2.16 91.665 41.148 91.935 ;
     RECT  77.22 91.665 96.12 91.935 ;
     RECT  2.16 92.205 41.148 92.475 ;
     RECT  77.22 92.205 96.12 92.475 ;
     RECT  2.16 92.745 41.148 93.015 ;
     RECT  77.22 92.745 96.12 93.015 ;
     RECT  2.16 93.285 41.148 93.555 ;
     RECT  77.22 93.285 96.12 93.555 ;
     RECT  2.16 93.825 41.148 94.095 ;
     RECT  77.22 93.825 96.12 94.095 ;
     RECT  2.16 94.365 41.148 94.635 ;
     RECT  77.22 94.365 96.12 94.635 ;
     RECT  2.16 94.905 41.148 95.175 ;
     RECT  77.22 94.905 96.12 95.175 ;
     RECT  2.16 95.445 41.148 95.715 ;
     RECT  77.22 95.445 96.12 95.715 ;
     RECT  2.16 95.985 41.148 96.255 ;
     RECT  77.22 95.985 96.12 96.255 ;
     RECT  2.16 96.525 41.148 96.795 ;
     RECT  77.22 96.525 96.12 96.795 ;
     RECT  2.16 97.065 41.148 97.335 ;
     RECT  77.22 97.065 96.12 97.335 ;
     RECT  2.16 97.605 41.148 97.875 ;
     RECT  77.22 97.605 96.12 97.875 ;
     RECT  2.16 98.145 41.148 98.415 ;
     RECT  77.22 98.145 96.12 98.415 ;
     RECT  2.16 98.685 41.148 98.955 ;
     RECT  77.22 98.685 96.12 98.955 ;
     RECT  2.16 99.225 41.148 99.495 ;
     RECT  77.22 99.225 96.12 99.495 ;
     RECT  2.16 99.765 41.148 100.035 ;
     RECT  77.22 99.765 96.12 100.035 ;
     RECT  2.16 100.305 41.148 100.575 ;
     RECT  77.22 100.305 96.12 100.575 ;
     RECT  2.16 100.845 41.148 101.115 ;
     RECT  77.22 100.845 96.12 101.115 ;
     RECT  2.16 101.385 41.148 101.655 ;
     RECT  77.22 101.385 96.12 101.655 ;
     RECT  2.16 101.925 41.148 102.195 ;
     RECT  77.22 101.925 96.12 102.195 ;
     RECT  2.16 102.465 41.148 102.735 ;
     RECT  77.22 102.465 96.12 102.735 ;
     RECT  2.16 103.005 41.148 103.275 ;
     RECT  77.22 103.005 96.12 103.275 ;
     RECT  2.16 103.545 41.148 103.815 ;
     RECT  77.22 103.545 96.12 103.815 ;
     RECT  2.16 104.085 41.148 104.355 ;
     RECT  77.22 104.085 96.12 104.355 ;
     RECT  2.16 104.625 41.148 104.895 ;
     RECT  77.22 104.625 96.12 104.895 ;
     RECT  2.16 105.165 41.148 105.435 ;
     RECT  77.22 105.165 96.12 105.435 ;
     RECT  2.16 105.705 41.148 105.84 ;
     RECT  77.22 105.705 96.12 105.84 ;
     RECT  2.16 105.84 96.12 105.975 ;
     RECT  2.16 106.245 96.12 106.515 ;
     RECT  2.16 106.785 96.12 107.055 ;
     RECT  2.16 107.325 96.12 107.595 ;
     RECT  2.16 107.865 96.12 108.135 ;
     RECT  2.16 108.405 96.12 108.675 ;
     RECT  2.16 108.945 96.12 109.215 ;
     RECT  2.16 109.485 96.12 109.755 ;
     RECT  2.16 110.025 96.12 110.295 ;
     RECT  2.16 110.565 96.12 110.835 ;
     RECT  2.16 111.105 96.12 111.375 ;
     RECT  2.16 111.645 96.12 111.915 ;
     RECT  2.16 112.185 96.12 112.455 ;
     RECT  2.16 112.725 96.12 112.995 ;
     RECT  2.16 113.265 96.12 113.535 ;
     RECT  2.16 113.805 96.12 114.075 ;
     RECT  2.16 114.345 96.12 114.615 ;
     RECT  2.16 114.885 96.12 115.155 ;
     RECT  2.16 115.425 96.12 115.695 ;
     RECT  2.16 115.965 96.12 116.235 ;
     RECT  2.16 116.505 96.12 116.775 ;
     RECT  2.16 117.045 96.12 117.315 ;
     RECT  2.16 117.585 96.12 117.855 ;
     RECT  2.16 118.125 96.12 118.395 ;
     RECT  2.16 118.665 96.12 118.935 ;
     RECT  2.16 119.205 96.12 119.475 ;
     RECT  2.16 119.745 96.12 120.015 ;
     RECT  2.16 120.285 96.12 120.555 ;
     RECT  2.16 120.825 96.12 121.095 ;
     RECT  2.16 121.365 96.12 121.635 ;
     RECT  2.16 121.905 96.12 122.175 ;
     RECT  2.16 122.445 96.12 122.715 ;
     RECT  2.16 122.985 96.12 123.255 ;
     RECT  2.16 123.525 96.12 123.795 ;
     RECT  2.16 124.065 96.12 124.335 ;
     RECT  2.16 124.605 96.12 124.875 ;
     RECT  2.16 125.145 96.12 125.415 ;
     RECT  2.16 125.685 96.12 125.955 ;
     RECT  2.16 126.225 96.12 126.495 ;
     RECT  2.16 126.765 96.12 127.035 ;
     RECT  2.16 127.305 96.12 127.44 ;
     RECT  2.16 127.44 41.148 127.575 ;
     RECT  77.22 127.44 96.12 127.575 ;
     RECT  2.16 127.845 41.148 128.115 ;
     RECT  77.22 127.845 96.12 128.115 ;
     RECT  2.16 128.385 41.148 128.655 ;
     RECT  77.22 128.385 96.12 128.655 ;
     RECT  2.16 128.925 41.148 129.195 ;
     RECT  77.22 128.925 96.12 129.195 ;
     RECT  2.16 129.465 41.148 129.735 ;
     RECT  77.22 129.465 96.12 129.735 ;
     RECT  2.16 130.005 41.148 130.275 ;
     RECT  77.22 130.005 96.12 130.275 ;
     RECT  2.16 130.545 41.148 130.815 ;
     RECT  77.22 130.545 96.12 130.815 ;
     RECT  2.16 131.085 41.148 131.355 ;
     RECT  77.22 131.085 96.12 131.355 ;
     RECT  2.16 131.625 41.148 131.895 ;
     RECT  77.22 131.625 96.12 131.895 ;
     RECT  2.16 132.165 41.148 132.435 ;
     RECT  77.22 132.165 96.12 132.435 ;
     RECT  2.16 132.705 41.148 132.975 ;
     RECT  77.22 132.705 96.12 132.975 ;
     RECT  2.16 133.245 41.148 133.515 ;
     RECT  77.22 133.245 96.12 133.515 ;
     RECT  2.16 133.785 41.148 134.055 ;
     RECT  77.22 133.785 96.12 134.055 ;
     RECT  2.16 134.325 41.148 134.595 ;
     RECT  77.22 134.325 96.12 134.595 ;
     RECT  2.16 134.865 41.148 135.135 ;
     RECT  77.22 134.865 96.12 135.135 ;
     RECT  2.16 135.405 41.148 135.675 ;
     RECT  77.22 135.405 96.12 135.675 ;
     RECT  2.16 135.945 41.148 136.215 ;
     RECT  77.22 135.945 96.12 136.215 ;
     RECT  2.16 136.485 41.148 136.755 ;
     RECT  77.22 136.485 96.12 136.755 ;
     RECT  2.16 137.025 41.148 137.295 ;
     RECT  77.22 137.025 96.12 137.295 ;
     RECT  2.16 137.565 41.148 137.835 ;
     RECT  77.22 137.565 96.12 137.835 ;
     RECT  2.16 138.105 41.148 138.375 ;
     RECT  77.22 138.105 96.12 138.375 ;
     RECT  2.16 138.645 41.148 138.915 ;
     RECT  77.22 138.645 96.12 138.915 ;
     RECT  2.16 139.185 41.148 139.455 ;
     RECT  77.22 139.185 96.12 139.455 ;
     RECT  2.16 139.725 41.148 139.995 ;
     RECT  77.22 139.725 96.12 139.995 ;
     RECT  2.16 140.265 41.148 140.535 ;
     RECT  77.22 140.265 96.12 140.535 ;
     RECT  2.16 140.805 41.148 141.075 ;
     RECT  77.22 140.805 96.12 141.075 ;
     RECT  2.16 141.345 41.148 141.615 ;
     RECT  77.22 141.345 96.12 141.615 ;
     RECT  2.16 141.885 41.148 142.155 ;
     RECT  77.22 141.885 96.12 142.155 ;
     RECT  2.16 142.425 41.148 142.695 ;
     RECT  77.22 142.425 96.12 142.695 ;
     RECT  2.16 142.965 41.148 143.235 ;
     RECT  77.22 142.965 96.12 143.235 ;
     RECT  2.16 143.505 41.148 143.775 ;
     RECT  77.22 143.505 96.12 143.775 ;
     RECT  2.16 144.045 41.148 144.315 ;
     RECT  77.22 144.045 96.12 144.315 ;
     RECT  2.16 144.585 41.148 144.855 ;
     RECT  77.22 144.585 96.12 144.855 ;
     RECT  2.16 145.125 41.148 145.395 ;
     RECT  77.22 145.125 96.12 145.395 ;
     RECT  2.16 145.665 41.148 145.935 ;
     RECT  77.22 145.665 96.12 145.935 ;
     RECT  2.16 146.205 41.148 146.475 ;
     RECT  77.22 146.205 96.12 146.475 ;
     RECT  2.16 146.745 41.148 147.015 ;
     RECT  77.22 146.745 96.12 147.015 ;
     RECT  2.16 147.285 41.148 147.555 ;
     RECT  77.22 147.285 96.12 147.555 ;
     RECT  2.16 147.825 41.148 148.095 ;
     RECT  77.22 147.825 96.12 148.095 ;
     RECT  2.16 148.365 41.148 148.635 ;
     RECT  77.22 148.365 96.12 148.635 ;
     RECT  2.16 148.905 41.148 149.04 ;
     RECT  77.22 148.905 96.12 149.04 ;
     RECT  2.16 149.04 96.12 149.175 ;
     RECT  2.16 149.445 96.12 149.715 ;
     RECT  2.16 149.985 96.12 150.255 ;
     RECT  2.16 150.525 96.12 150.795 ;
     RECT  2.16 151.065 96.12 151.335 ;
     RECT  2.16 151.605 96.12 151.875 ;
     RECT  2.16 152.145 96.12 152.415 ;
     RECT  2.16 152.685 96.12 152.955 ;
     RECT  2.16 153.225 96.12 153.495 ;
     RECT  2.16 153.765 96.12 154.035 ;
     RECT  2.16 154.305 96.12 154.575 ;
     RECT  2.16 154.845 96.12 155.115 ;
     RECT  2.16 155.385 96.12 155.655 ;
     RECT  2.16 155.925 96.12 156.195 ;
     RECT  2.16 156.465 96.12 156.735 ;
     RECT  2.16 157.005 96.12 157.275 ;
     RECT  2.16 157.545 96.12 157.815 ;
     RECT  2.16 158.085 96.12 158.355 ;
     RECT  2.16 158.625 96.12 158.895 ;
     RECT  2.16 159.165 96.12 159.435 ;
     RECT  2.16 159.705 96.12 159.975 ;
     RECT  2.16 160.245 96.12 160.515 ;
     RECT  2.16 160.785 96.12 161.055 ;
     RECT  2.16 161.325 96.12 161.595 ;
     RECT  2.16 161.865 96.12 162.135 ;
     RECT  2.16 162.405 96.12 162.675 ;
     RECT  2.16 162.945 96.12 163.215 ;
     RECT  2.16 163.485 96.12 163.755 ;
     RECT  2.16 164.025 96.12 164.295 ;
     RECT  2.16 164.565 96.12 164.835 ;
     RECT  2.16 165.105 96.12 165.375 ;
     RECT  2.16 165.645 96.12 165.915 ;
     RECT  2.16 166.185 96.12 166.455 ;
     RECT  2.16 166.725 96.12 166.995 ;
     RECT  2.16 167.265 96.12 167.535 ;
     RECT  2.16 167.805 96.12 168.075 ;
     RECT  2.16 168.345 96.12 168.48 ;
    LAYER RVTP ;
     RECT  2.16 2.295 96.12 2.565 ;
     RECT  2.16 2.835 96.12 3.105 ;
     RECT  2.16 3.375 96.12 3.645 ;
     RECT  2.16 3.915 96.12 4.185 ;
     RECT  2.16 4.455 96.12 4.725 ;
     RECT  2.16 4.995 96.12 5.265 ;
     RECT  2.16 5.535 96.12 5.805 ;
     RECT  2.16 6.075 96.12 6.345 ;
     RECT  2.16 6.615 96.12 6.885 ;
     RECT  2.16 7.155 96.12 7.425 ;
     RECT  2.16 7.695 96.12 7.965 ;
     RECT  2.16 8.235 96.12 8.505 ;
     RECT  2.16 8.775 96.12 9.045 ;
     RECT  2.16 9.315 96.12 9.585 ;
     RECT  2.16 9.855 96.12 10.125 ;
     RECT  2.16 10.395 96.12 10.665 ;
     RECT  2.16 10.935 96.12 11.205 ;
     RECT  2.16 11.475 96.12 11.745 ;
     RECT  2.16 12.015 96.12 12.285 ;
     RECT  2.16 12.555 96.12 12.825 ;
     RECT  2.16 13.095 96.12 13.365 ;
     RECT  2.16 13.635 96.12 13.905 ;
     RECT  2.16 14.175 96.12 14.445 ;
     RECT  2.16 14.715 96.12 14.985 ;
     RECT  2.16 15.255 96.12 15.525 ;
     RECT  2.16 15.795 96.12 16.065 ;
     RECT  2.16 16.335 96.12 16.605 ;
     RECT  2.16 16.875 96.12 17.145 ;
     RECT  2.16 17.415 96.12 17.685 ;
     RECT  2.16 17.955 96.12 18.225 ;
     RECT  2.16 18.495 96.12 18.765 ;
     RECT  2.16 19.035 96.12 19.305 ;
     RECT  2.16 19.575 96.12 19.845 ;
     RECT  2.16 20.115 96.12 20.385 ;
     RECT  2.16 20.655 96.12 20.925 ;
     RECT  2.16 21.195 96.12 21.465 ;
     RECT  2.16 21.735 96.12 22.005 ;
     RECT  2.16 22.275 96.12 22.545 ;
     RECT  2.16 22.815 96.12 23.085 ;
     RECT  2.16 23.355 96.12 23.625 ;
     RECT  2.16 23.895 96.12 24.165 ;
     RECT  2.16 24.435 96.12 24.705 ;
     RECT  2.16 24.975 96.12 25.245 ;
     RECT  2.16 25.515 96.12 25.785 ;
     RECT  2.16 26.055 96.12 26.325 ;
     RECT  2.16 26.595 96.12 26.865 ;
     RECT  2.16 27.135 96.12 27.405 ;
     RECT  2.16 27.675 96.12 27.945 ;
     RECT  2.16 28.215 96.12 28.485 ;
     RECT  2.16 28.755 96.12 29.025 ;
     RECT  2.16 29.295 96.12 29.565 ;
     RECT  2.16 29.835 96.12 30.105 ;
     RECT  2.16 30.375 96.12 30.645 ;
     RECT  2.16 30.915 96.12 31.185 ;
     RECT  2.16 31.455 96.12 31.725 ;
     RECT  2.16 31.995 96.12 32.265 ;
     RECT  2.16 32.535 96.12 32.805 ;
     RECT  2.16 33.075 96.12 33.345 ;
     RECT  2.16 33.615 96.12 33.885 ;
     RECT  2.16 34.155 96.12 34.425 ;
     RECT  2.16 34.695 96.12 34.965 ;
     RECT  2.16 35.235 96.12 35.505 ;
     RECT  2.16 35.775 96.12 36.045 ;
     RECT  2.16 36.315 96.12 36.585 ;
     RECT  2.16 36.855 96.12 37.125 ;
     RECT  2.16 37.395 96.12 37.665 ;
     RECT  2.16 37.935 96.12 38.205 ;
     RECT  2.16 38.475 96.12 38.745 ;
     RECT  2.16 39.015 96.12 39.285 ;
     RECT  2.16 39.555 96.12 39.825 ;
     RECT  2.16 40.095 96.12 40.365 ;
     RECT  2.16 40.635 96.12 40.905 ;
     RECT  2.16 41.175 41.148 41.445 ;
     RECT  77.22 41.175 96.12 41.445 ;
     RECT  2.16 41.715 41.148 41.985 ;
     RECT  77.22 41.715 96.12 41.985 ;
     RECT  2.16 42.255 41.148 42.525 ;
     RECT  77.22 42.255 96.12 42.525 ;
     RECT  2.16 42.795 41.148 43.065 ;
     RECT  77.22 42.795 96.12 43.065 ;
     RECT  2.16 43.335 41.148 43.605 ;
     RECT  77.22 43.335 96.12 43.605 ;
     RECT  2.16 43.875 41.148 44.145 ;
     RECT  77.22 43.875 96.12 44.145 ;
     RECT  2.16 44.415 41.148 44.685 ;
     RECT  77.22 44.415 96.12 44.685 ;
     RECT  2.16 44.955 41.148 45.225 ;
     RECT  77.22 44.955 96.12 45.225 ;
     RECT  2.16 45.495 41.148 45.765 ;
     RECT  77.22 45.495 96.12 45.765 ;
     RECT  2.16 46.035 41.148 46.305 ;
     RECT  77.22 46.035 96.12 46.305 ;
     RECT  2.16 46.575 41.148 46.845 ;
     RECT  77.22 46.575 96.12 46.845 ;
     RECT  2.16 47.115 41.148 47.385 ;
     RECT  77.22 47.115 96.12 47.385 ;
     RECT  2.16 47.655 41.148 47.925 ;
     RECT  77.22 47.655 96.12 47.925 ;
     RECT  2.16 48.195 41.148 48.465 ;
     RECT  77.22 48.195 96.12 48.465 ;
     RECT  2.16 48.735 41.148 49.005 ;
     RECT  77.22 48.735 96.12 49.005 ;
     RECT  2.16 49.275 41.148 49.545 ;
     RECT  77.22 49.275 96.12 49.545 ;
     RECT  2.16 49.815 41.148 50.085 ;
     RECT  77.22 49.815 96.12 50.085 ;
     RECT  2.16 50.355 41.148 50.625 ;
     RECT  77.22 50.355 96.12 50.625 ;
     RECT  2.16 50.895 41.148 51.165 ;
     RECT  77.22 50.895 96.12 51.165 ;
     RECT  2.16 51.435 41.148 51.705 ;
     RECT  77.22 51.435 96.12 51.705 ;
     RECT  2.16 51.975 41.148 52.245 ;
     RECT  77.22 51.975 96.12 52.245 ;
     RECT  2.16 52.515 41.148 52.785 ;
     RECT  77.22 52.515 96.12 52.785 ;
     RECT  2.16 53.055 41.148 53.325 ;
     RECT  77.22 53.055 96.12 53.325 ;
     RECT  2.16 53.595 41.148 53.865 ;
     RECT  77.22 53.595 96.12 53.865 ;
     RECT  2.16 54.135 41.148 54.405 ;
     RECT  77.22 54.135 96.12 54.405 ;
     RECT  2.16 54.675 41.148 54.945 ;
     RECT  77.22 54.675 96.12 54.945 ;
     RECT  2.16 55.215 41.148 55.485 ;
     RECT  77.22 55.215 96.12 55.485 ;
     RECT  2.16 55.755 41.148 56.025 ;
     RECT  77.22 55.755 96.12 56.025 ;
     RECT  2.16 56.295 41.148 56.565 ;
     RECT  77.22 56.295 96.12 56.565 ;
     RECT  2.16 56.835 41.148 57.105 ;
     RECT  77.22 56.835 96.12 57.105 ;
     RECT  2.16 57.375 41.148 57.645 ;
     RECT  77.22 57.375 96.12 57.645 ;
     RECT  2.16 57.915 41.148 58.185 ;
     RECT  77.22 57.915 96.12 58.185 ;
     RECT  2.16 58.455 41.148 58.725 ;
     RECT  77.22 58.455 96.12 58.725 ;
     RECT  2.16 58.995 41.148 59.265 ;
     RECT  77.22 58.995 96.12 59.265 ;
     RECT  2.16 59.535 41.148 59.805 ;
     RECT  77.22 59.535 96.12 59.805 ;
     RECT  2.16 60.075 41.148 60.345 ;
     RECT  77.22 60.075 96.12 60.345 ;
     RECT  2.16 60.615 41.148 60.885 ;
     RECT  77.22 60.615 96.12 60.885 ;
     RECT  2.16 61.155 41.148 61.425 ;
     RECT  77.22 61.155 96.12 61.425 ;
     RECT  2.16 61.695 41.148 61.965 ;
     RECT  77.22 61.695 96.12 61.965 ;
     RECT  2.16 62.235 41.148 62.505 ;
     RECT  77.22 62.235 96.12 62.505 ;
     RECT  2.16 62.775 96.12 63.045 ;
     RECT  2.16 63.315 96.12 63.585 ;
     RECT  2.16 63.855 96.12 64.125 ;
     RECT  2.16 64.395 96.12 64.665 ;
     RECT  2.16 64.935 96.12 65.205 ;
     RECT  2.16 65.475 96.12 65.745 ;
     RECT  2.16 66.015 96.12 66.285 ;
     RECT  2.16 66.555 96.12 66.825 ;
     RECT  2.16 67.095 96.12 67.365 ;
     RECT  2.16 67.635 96.12 67.905 ;
     RECT  2.16 68.175 96.12 68.445 ;
     RECT  2.16 68.715 96.12 68.985 ;
     RECT  2.16 69.255 96.12 69.525 ;
     RECT  2.16 69.795 96.12 70.065 ;
     RECT  2.16 70.335 96.12 70.605 ;
     RECT  2.16 70.875 96.12 71.145 ;
     RECT  2.16 71.415 96.12 71.685 ;
     RECT  2.16 71.955 96.12 72.225 ;
     RECT  2.16 72.495 96.12 72.765 ;
     RECT  2.16 73.035 96.12 73.305 ;
     RECT  2.16 73.575 96.12 73.845 ;
     RECT  2.16 74.115 96.12 74.385 ;
     RECT  2.16 74.655 96.12 74.925 ;
     RECT  2.16 75.195 96.12 75.465 ;
     RECT  2.16 75.735 96.12 76.005 ;
     RECT  2.16 76.275 96.12 76.545 ;
     RECT  2.16 76.815 96.12 77.085 ;
     RECT  2.16 77.355 96.12 77.625 ;
     RECT  2.16 77.895 96.12 78.165 ;
     RECT  2.16 78.435 96.12 78.705 ;
     RECT  2.16 78.975 96.12 79.245 ;
     RECT  2.16 79.515 96.12 79.785 ;
     RECT  2.16 80.055 96.12 80.325 ;
     RECT  2.16 80.595 96.12 80.865 ;
     RECT  2.16 81.135 96.12 81.405 ;
     RECT  2.16 81.675 96.12 81.945 ;
     RECT  2.16 82.215 96.12 82.485 ;
     RECT  2.16 82.755 96.12 83.025 ;
     RECT  2.16 83.295 96.12 83.565 ;
     RECT  2.16 83.835 96.12 84.105 ;
     RECT  2.16 84.375 41.148 84.645 ;
     RECT  77.22 84.375 96.12 84.645 ;
     RECT  2.16 84.915 41.148 85.185 ;
     RECT  77.22 84.915 96.12 85.185 ;
     RECT  2.16 85.455 41.148 85.725 ;
     RECT  77.22 85.455 96.12 85.725 ;
     RECT  2.16 85.995 41.148 86.265 ;
     RECT  77.22 85.995 96.12 86.265 ;
     RECT  2.16 86.535 41.148 86.805 ;
     RECT  77.22 86.535 96.12 86.805 ;
     RECT  2.16 87.075 41.148 87.345 ;
     RECT  77.22 87.075 96.12 87.345 ;
     RECT  2.16 87.615 41.148 87.885 ;
     RECT  77.22 87.615 96.12 87.885 ;
     RECT  2.16 88.155 41.148 88.425 ;
     RECT  77.22 88.155 96.12 88.425 ;
     RECT  2.16 88.695 41.148 88.965 ;
     RECT  77.22 88.695 96.12 88.965 ;
     RECT  2.16 89.235 41.148 89.505 ;
     RECT  77.22 89.235 96.12 89.505 ;
     RECT  2.16 89.775 41.148 90.045 ;
     RECT  77.22 89.775 96.12 90.045 ;
     RECT  2.16 90.315 41.148 90.585 ;
     RECT  77.22 90.315 96.12 90.585 ;
     RECT  2.16 90.855 41.148 91.125 ;
     RECT  77.22 90.855 96.12 91.125 ;
     RECT  2.16 91.395 41.148 91.665 ;
     RECT  77.22 91.395 96.12 91.665 ;
     RECT  2.16 91.935 41.148 92.205 ;
     RECT  77.22 91.935 96.12 92.205 ;
     RECT  2.16 92.475 41.148 92.745 ;
     RECT  77.22 92.475 96.12 92.745 ;
     RECT  2.16 93.015 41.148 93.285 ;
     RECT  77.22 93.015 96.12 93.285 ;
     RECT  2.16 93.555 41.148 93.825 ;
     RECT  77.22 93.555 96.12 93.825 ;
     RECT  2.16 94.095 41.148 94.365 ;
     RECT  77.22 94.095 96.12 94.365 ;
     RECT  2.16 94.635 41.148 94.905 ;
     RECT  77.22 94.635 96.12 94.905 ;
     RECT  2.16 95.175 41.148 95.445 ;
     RECT  77.22 95.175 96.12 95.445 ;
     RECT  2.16 95.715 41.148 95.985 ;
     RECT  77.22 95.715 96.12 95.985 ;
     RECT  2.16 96.255 41.148 96.525 ;
     RECT  77.22 96.255 96.12 96.525 ;
     RECT  2.16 96.795 41.148 97.065 ;
     RECT  77.22 96.795 96.12 97.065 ;
     RECT  2.16 97.335 41.148 97.605 ;
     RECT  77.22 97.335 96.12 97.605 ;
     RECT  2.16 97.875 41.148 98.145 ;
     RECT  77.22 97.875 96.12 98.145 ;
     RECT  2.16 98.415 41.148 98.685 ;
     RECT  77.22 98.415 96.12 98.685 ;
     RECT  2.16 98.955 41.148 99.225 ;
     RECT  77.22 98.955 96.12 99.225 ;
     RECT  2.16 99.495 41.148 99.765 ;
     RECT  77.22 99.495 96.12 99.765 ;
     RECT  2.16 100.035 41.148 100.305 ;
     RECT  77.22 100.035 96.12 100.305 ;
     RECT  2.16 100.575 41.148 100.845 ;
     RECT  77.22 100.575 96.12 100.845 ;
     RECT  2.16 101.115 41.148 101.385 ;
     RECT  77.22 101.115 96.12 101.385 ;
     RECT  2.16 101.655 41.148 101.925 ;
     RECT  77.22 101.655 96.12 101.925 ;
     RECT  2.16 102.195 41.148 102.465 ;
     RECT  77.22 102.195 96.12 102.465 ;
     RECT  2.16 102.735 41.148 103.005 ;
     RECT  77.22 102.735 96.12 103.005 ;
     RECT  2.16 103.275 41.148 103.545 ;
     RECT  77.22 103.275 96.12 103.545 ;
     RECT  2.16 103.815 41.148 104.085 ;
     RECT  77.22 103.815 96.12 104.085 ;
     RECT  2.16 104.355 41.148 104.625 ;
     RECT  77.22 104.355 96.12 104.625 ;
     RECT  2.16 104.895 41.148 105.165 ;
     RECT  77.22 104.895 96.12 105.165 ;
     RECT  2.16 105.435 41.148 105.705 ;
     RECT  77.22 105.435 96.12 105.705 ;
     RECT  2.16 105.975 96.12 106.245 ;
     RECT  2.16 106.515 96.12 106.785 ;
     RECT  2.16 107.055 96.12 107.325 ;
     RECT  2.16 107.595 96.12 107.865 ;
     RECT  2.16 108.135 96.12 108.405 ;
     RECT  2.16 108.675 96.12 108.945 ;
     RECT  2.16 109.215 96.12 109.485 ;
     RECT  2.16 109.755 96.12 110.025 ;
     RECT  2.16 110.295 96.12 110.565 ;
     RECT  2.16 110.835 96.12 111.105 ;
     RECT  2.16 111.375 96.12 111.645 ;
     RECT  2.16 111.915 96.12 112.185 ;
     RECT  2.16 112.455 96.12 112.725 ;
     RECT  2.16 112.995 96.12 113.265 ;
     RECT  2.16 113.535 96.12 113.805 ;
     RECT  2.16 114.075 96.12 114.345 ;
     RECT  2.16 114.615 96.12 114.885 ;
     RECT  2.16 115.155 96.12 115.425 ;
     RECT  2.16 115.695 96.12 115.965 ;
     RECT  2.16 116.235 96.12 116.505 ;
     RECT  2.16 116.775 96.12 117.045 ;
     RECT  2.16 117.315 96.12 117.585 ;
     RECT  2.16 117.855 96.12 118.125 ;
     RECT  2.16 118.395 96.12 118.665 ;
     RECT  2.16 118.935 96.12 119.205 ;
     RECT  2.16 119.475 96.12 119.745 ;
     RECT  2.16 120.015 96.12 120.285 ;
     RECT  2.16 120.555 96.12 120.825 ;
     RECT  2.16 121.095 96.12 121.365 ;
     RECT  2.16 121.635 96.12 121.905 ;
     RECT  2.16 122.175 96.12 122.445 ;
     RECT  2.16 122.715 96.12 122.985 ;
     RECT  2.16 123.255 96.12 123.525 ;
     RECT  2.16 123.795 96.12 124.065 ;
     RECT  2.16 124.335 96.12 124.605 ;
     RECT  2.16 124.875 96.12 125.145 ;
     RECT  2.16 125.415 96.12 125.685 ;
     RECT  2.16 125.955 96.12 126.225 ;
     RECT  2.16 126.495 96.12 126.765 ;
     RECT  2.16 127.035 96.12 127.305 ;
     RECT  2.16 127.575 41.148 127.845 ;
     RECT  77.22 127.575 96.12 127.845 ;
     RECT  2.16 128.115 41.148 128.385 ;
     RECT  77.22 128.115 96.12 128.385 ;
     RECT  2.16 128.655 41.148 128.925 ;
     RECT  77.22 128.655 96.12 128.925 ;
     RECT  2.16 129.195 41.148 129.465 ;
     RECT  77.22 129.195 96.12 129.465 ;
     RECT  2.16 129.735 41.148 130.005 ;
     RECT  77.22 129.735 96.12 130.005 ;
     RECT  2.16 130.275 41.148 130.545 ;
     RECT  77.22 130.275 96.12 130.545 ;
     RECT  2.16 130.815 41.148 131.085 ;
     RECT  77.22 130.815 96.12 131.085 ;
     RECT  2.16 131.355 41.148 131.625 ;
     RECT  77.22 131.355 96.12 131.625 ;
     RECT  2.16 131.895 41.148 132.165 ;
     RECT  77.22 131.895 96.12 132.165 ;
     RECT  2.16 132.435 41.148 132.705 ;
     RECT  77.22 132.435 96.12 132.705 ;
     RECT  2.16 132.975 41.148 133.245 ;
     RECT  77.22 132.975 96.12 133.245 ;
     RECT  2.16 133.515 41.148 133.785 ;
     RECT  77.22 133.515 96.12 133.785 ;
     RECT  2.16 134.055 41.148 134.325 ;
     RECT  77.22 134.055 96.12 134.325 ;
     RECT  2.16 134.595 41.148 134.865 ;
     RECT  77.22 134.595 96.12 134.865 ;
     RECT  2.16 135.135 41.148 135.405 ;
     RECT  77.22 135.135 96.12 135.405 ;
     RECT  2.16 135.675 41.148 135.945 ;
     RECT  77.22 135.675 96.12 135.945 ;
     RECT  2.16 136.215 41.148 136.485 ;
     RECT  77.22 136.215 96.12 136.485 ;
     RECT  2.16 136.755 41.148 137.025 ;
     RECT  77.22 136.755 96.12 137.025 ;
     RECT  2.16 137.295 41.148 137.565 ;
     RECT  77.22 137.295 96.12 137.565 ;
     RECT  2.16 137.835 41.148 138.105 ;
     RECT  77.22 137.835 96.12 138.105 ;
     RECT  2.16 138.375 41.148 138.645 ;
     RECT  77.22 138.375 96.12 138.645 ;
     RECT  2.16 138.915 41.148 139.185 ;
     RECT  77.22 138.915 96.12 139.185 ;
     RECT  2.16 139.455 41.148 139.725 ;
     RECT  77.22 139.455 96.12 139.725 ;
     RECT  2.16 139.995 41.148 140.265 ;
     RECT  77.22 139.995 96.12 140.265 ;
     RECT  2.16 140.535 41.148 140.805 ;
     RECT  77.22 140.535 96.12 140.805 ;
     RECT  2.16 141.075 41.148 141.345 ;
     RECT  77.22 141.075 96.12 141.345 ;
     RECT  2.16 141.615 41.148 141.885 ;
     RECT  77.22 141.615 96.12 141.885 ;
     RECT  2.16 142.155 41.148 142.425 ;
     RECT  77.22 142.155 96.12 142.425 ;
     RECT  2.16 142.695 41.148 142.965 ;
     RECT  77.22 142.695 96.12 142.965 ;
     RECT  2.16 143.235 41.148 143.505 ;
     RECT  77.22 143.235 96.12 143.505 ;
     RECT  2.16 143.775 41.148 144.045 ;
     RECT  77.22 143.775 96.12 144.045 ;
     RECT  2.16 144.315 41.148 144.585 ;
     RECT  77.22 144.315 96.12 144.585 ;
     RECT  2.16 144.855 41.148 145.125 ;
     RECT  77.22 144.855 96.12 145.125 ;
     RECT  2.16 145.395 41.148 145.665 ;
     RECT  77.22 145.395 96.12 145.665 ;
     RECT  2.16 145.935 41.148 146.205 ;
     RECT  77.22 145.935 96.12 146.205 ;
     RECT  2.16 146.475 41.148 146.745 ;
     RECT  77.22 146.475 96.12 146.745 ;
     RECT  2.16 147.015 41.148 147.285 ;
     RECT  77.22 147.015 96.12 147.285 ;
     RECT  2.16 147.555 41.148 147.825 ;
     RECT  77.22 147.555 96.12 147.825 ;
     RECT  2.16 148.095 41.148 148.365 ;
     RECT  77.22 148.095 96.12 148.365 ;
     RECT  2.16 148.635 41.148 148.905 ;
     RECT  77.22 148.635 96.12 148.905 ;
     RECT  2.16 149.175 96.12 149.445 ;
     RECT  2.16 149.715 96.12 149.985 ;
     RECT  2.16 150.255 96.12 150.525 ;
     RECT  2.16 150.795 96.12 151.065 ;
     RECT  2.16 151.335 96.12 151.605 ;
     RECT  2.16 151.875 96.12 152.145 ;
     RECT  2.16 152.415 96.12 152.685 ;
     RECT  2.16 152.955 96.12 153.225 ;
     RECT  2.16 153.495 96.12 153.765 ;
     RECT  2.16 154.035 96.12 154.305 ;
     RECT  2.16 154.575 96.12 154.845 ;
     RECT  2.16 155.115 96.12 155.385 ;
     RECT  2.16 155.655 96.12 155.925 ;
     RECT  2.16 156.195 96.12 156.465 ;
     RECT  2.16 156.735 96.12 157.005 ;
     RECT  2.16 157.275 96.12 157.545 ;
     RECT  2.16 157.815 96.12 158.085 ;
     RECT  2.16 158.355 96.12 158.625 ;
     RECT  2.16 158.895 96.12 159.165 ;
     RECT  2.16 159.435 96.12 159.705 ;
     RECT  2.16 159.975 96.12 160.245 ;
     RECT  2.16 160.515 96.12 160.785 ;
     RECT  2.16 161.055 96.12 161.325 ;
     RECT  2.16 161.595 96.12 161.865 ;
     RECT  2.16 162.135 96.12 162.405 ;
     RECT  2.16 162.675 96.12 162.945 ;
     RECT  2.16 163.215 96.12 163.485 ;
     RECT  2.16 163.755 96.12 164.025 ;
     RECT  2.16 164.295 96.12 164.565 ;
     RECT  2.16 164.835 96.12 165.105 ;
     RECT  2.16 165.375 96.12 165.645 ;
     RECT  2.16 165.915 96.12 166.185 ;
     RECT  2.16 166.455 96.12 166.725 ;
     RECT  2.16 166.995 96.12 167.265 ;
     RECT  2.16 167.535 96.12 167.805 ;
     RECT  2.16 168.075 96.12 168.345 ;
    LAYER M1 ;
     RECT  2.16 2.151 96.12 41.049 ;
     RECT  43.2 43.2 75.192 60.504 ;
     RECT  2.16 41.049 41.148 62.631 ;
     RECT  77.22 41.049 96.12 62.631 ;
     RECT  2.16 62.631 96.12 84.249 ;
     RECT  43.2 86.4 75.192 103.704 ;
     RECT  2.16 84.249 41.148 105.831 ;
     RECT  77.22 84.249 96.12 105.831 ;
     RECT  2.16 105.831 96.12 127.449 ;
     RECT  43.2 129.6 75.192 146.904 ;
     RECT  2.16 127.449 41.148 149.031 ;
     RECT  77.22 127.449 96.12 149.031 ;
     RECT  2.16 149.031 96.12 168.489 ;
    LAYER M2 ;
     RECT  0.103 82.566 0.175 82.584 ;
     RECT  0.103 83.376 0.175 83.394 ;
     RECT  0.175 82.566 0.203 83.394 ;
     RECT  0.103 31.806 0.211 31.824 ;
     RECT  0.103 32.886 0.211 33.444 ;
     RECT  0.203 82.566 0.275 83.286 ;
     RECT  0.103 42.066 0.535 42.084 ;
     RECT  0.103 43.308 0.535 43.866 ;
     RECT  0.103 80.838 0.535 81.504 ;
     RECT  0.275 82.566 0.535 82.584 ;
     RECT  0.103 85.266 0.535 85.554 ;
     RECT  0.103 86.706 0.535 87.714 ;
     RECT  0.103 129.366 0.535 130.536 ;
     RECT  0.535 129.366 2.155 131.004 ;
     RECT  0.211 31.806 2.16 33.444 ;
     RECT  0.535 34.506 2.16 35.064 ;
     RECT  0.103 35.856 2.16 36.306 ;
     RECT  0.103 40.986 2.16 41.004 ;
     RECT  0.535 42.066 2.16 44.946 ;
     RECT  0.103 79.056 2.16 79.614 ;
     RECT  0.535 80.838 2.16 82.584 ;
     RECT  0.535 84.726 2.16 87.714 ;
     RECT  2.083 88.776 2.16 88.794 ;
     RECT  0.103 118.206 2.16 118.224 ;
     RECT  0.103 119.016 2.16 120.204 ;
     RECT  0.103 121.176 2.16 122.274 ;
     RECT  2.155 129.366 2.16 131.616 ;
     RECT  37.831 170.586 37.903 170.604 ;
     RECT  37.903 170.514 38.219 170.604 ;
     RECT  2.16 2.151 41.148 168.489 ;
     RECT  41.148 94.032 41.243 98.874 ;
     RECT  41.148 57.276 41.351 57.474 ;
     RECT  41.148 85.464 41.351 90.072 ;
     RECT  41.243 94.032 41.387 98.64 ;
     RECT  41.148 102.636 41.387 102.654 ;
     RECT  41.148 128.628 41.423 129.384 ;
     RECT  41.351 85.698 41.495 90.072 ;
     RECT  41.495 85.698 41.531 88.92 ;
     RECT  41.387 94.032 41.531 98.514 ;
     RECT  41.531 94.032 41.567 97.524 ;
     RECT  41.148 141.318 41.567 142.344 ;
     RECT  41.148 47.052 41.603 56.214 ;
     RECT  41.148 43.146 41.639 45.828 ;
     RECT  41.603 47.052 41.639 55.044 ;
     RECT  41.148 133.29 41.639 134.01 ;
     RECT  41.639 44.352 41.675 45.756 ;
     RECT  41.639 47.052 41.675 47.07 ;
     RECT  41.148 130.32 41.819 132.426 ;
     RECT  41.639 47.862 41.891 55.044 ;
     RECT  41.819 130.32 41.891 130.878 ;
     RECT  41.148 137.106 41.891 140.454 ;
     RECT  41.148 147.222 41.899 147.888 ;
     RECT  41.639 133.29 41.927 133.74 ;
     RECT  41.567 141.318 41.927 142.254 ;
     RECT  41.423 128.628 41.963 129.294 ;
     RECT  41.148 143.406 41.999 143.604 ;
     RECT  41.567 94.032 42.143 97.164 ;
     RECT  41.891 47.862 42.179 54.504 ;
     RECT  41.531 85.698 42.179 87.606 ;
     RECT  41.531 88.398 42.179 88.92 ;
     RECT  41.999 143.406 42.179 143.424 ;
     RECT  41.675 45.234 42.215 45.252 ;
     RECT  42.179 47.862 42.215 53.244 ;
     RECT  41.891 137.106 42.215 139.176 ;
     RECT  42.215 48.636 42.251 48.654 ;
     RECT  42.215 50.022 42.251 50.454 ;
     RECT  42.143 94.032 42.251 95.004 ;
     RECT  41.819 131.832 42.251 132.426 ;
     RECT  42.215 137.106 42.251 137.664 ;
     RECT  42.179 85.698 42.359 86.634 ;
     RECT  41.495 89.748 42.359 90.072 ;
     RECT  41.603 55.926 42.431 56.214 ;
     RECT  42.359 86.04 42.467 86.634 ;
     RECT  42.251 94.986 42.467 95.004 ;
     RECT  41.639 43.146 42.511 43.164 ;
     RECT  42.511 42.732 42.647 43.164 ;
     RECT  41.148 103.752 42.655 104.922 ;
     RECT  41.148 105.831 42.655 127.449 ;
     RECT  41.963 128.736 42.655 129.294 ;
     RECT  41.899 147.06 42.691 147.888 ;
     RECT  41.148 149.031 42.691 168.489 ;
     RECT  41.148 62.631 42.727 84.249 ;
     RECT  41.148 135.072 42.763 135.666 ;
     RECT  42.179 54.486 43.015 54.504 ;
     RECT  42.655 103.752 43.015 127.449 ;
     RECT  43.015 54.486 43.051 54.738 ;
     RECT  42.647 43.146 43.2 43.164 ;
     RECT  41.675 44.352 43.2 44.37 ;
     RECT  42.215 47.862 43.2 47.88 ;
     RECT  42.251 50.436 43.2 50.454 ;
     RECT  42.215 51.444 43.2 53.244 ;
     RECT  43.051 54.486 43.2 54.819 ;
     RECT  42.431 55.998 43.2 56.214 ;
     RECT  41.351 57.276 43.2 57.294 ;
     RECT  41.148 60.552 43.2 61.614 ;
     RECT  42.467 86.04 43.2 86.058 ;
     RECT  42.179 88.902 43.2 88.92 ;
     RECT  42.359 89.748 43.2 89.838 ;
     RECT  43.015 90.63 43.2 90.648 ;
     RECT  41.148 92.826 43.2 92.844 ;
     RECT  42.251 94.032 43.2 94.05 ;
     RECT  42.143 96.156 43.2 97.164 ;
     RECT  41.531 98.496 43.2 98.514 ;
     RECT  41.148 99.738 43.2 100.494 ;
     RECT  43.015 103.752 43.2 127.674 ;
     RECT  42.655 128.736 43.2 129.384 ;
     RECT  41.891 130.32 43.2 130.536 ;
     RECT  42.251 132.408 43.2 132.426 ;
     RECT  41.927 133.29 43.2 133.308 ;
     RECT  42.763 134.532 43.2 135.666 ;
     RECT  42.251 137.106 43.2 137.124 ;
     RECT  42.215 138.618 43.2 139.176 ;
     RECT  41.891 140.166 43.2 140.454 ;
     RECT  41.927 141.318 43.2 141.912 ;
     RECT  42.691 147.06 43.2 168.489 ;
     RECT  43.2 86.04 43.259 127.674 ;
     RECT  43.2 43.146 50.071 61.614 ;
     RECT  42.727 62.478 50.071 84.249 ;
     RECT  50.071 43.146 70.699 84.249 ;
     RECT  70.699 43.074 74.659 84.249 ;
     RECT  74.659 43.002 75.192 84.249 ;
     RECT  43.259 86.04 75.192 127.449 ;
     RECT  43.2 128.736 75.192 168.489 ;
     RECT  41.148 2.151 75.235 41.049 ;
     RECT  75.192 103.752 75.235 127.449 ;
     RECT  75.235 103.752 75.271 127.53 ;
     RECT  75.235 2.151 75.335 41.13 ;
     RECT  75.192 47.898 75.335 50.004 ;
     RECT  75.192 96.876 75.335 97.866 ;
     RECT  75.192 43.002 75.407 43.164 ;
     RECT  75.192 58.698 75.407 58.716 ;
     RECT  75.192 146.448 75.407 168.489 ;
     RECT  75.192 60.552 75.451 84.249 ;
     RECT  75.451 60.552 75.487 84.294 ;
     RECT  75.192 86.04 75.515 88.686 ;
     RECT  75.192 131.94 75.515 131.958 ;
     RECT  75.192 130.788 75.551 130.806 ;
     RECT  75.192 45.198 75.587 45.828 ;
     RECT  75.192 128.736 75.631 129.42 ;
     RECT  75.271 103.752 75.667 127.602 ;
     RECT  75.631 128.592 75.667 129.42 ;
     RECT  75.487 60.552 75.703 84.942 ;
     RECT  75.703 60.552 75.803 85.014 ;
     RECT  75.335 97.074 76.063 97.866 ;
     RECT  76.063 55.188 76.099 55.206 ;
     RECT  76.063 97.074 76.099 98.406 ;
     RECT  75.515 86.04 76.135 87.84 ;
     RECT  76.099 141.894 76.135 141.912 ;
     RECT  76.063 142.866 76.135 142.884 ;
     RECT  76.135 85.932 76.315 87.84 ;
     RECT  75.407 43.146 76.351 43.164 ;
     RECT  75.192 44.19 76.387 44.208 ;
     RECT  75.335 48.276 76.387 50.004 ;
     RECT  75.192 52.83 76.387 54.126 ;
     RECT  76.315 85.392 76.387 87.84 ;
     RECT  75.515 88.668 76.387 88.686 ;
     RECT  76.351 92.25 76.387 92.268 ;
     RECT  75.192 93.564 76.387 94.59 ;
     RECT  76.099 97.074 76.387 98.874 ;
     RECT  76.099 131.292 76.387 131.31 ;
     RECT  75.192 133.956 76.387 137.358 ;
     RECT  76.387 92.25 76.423 95.904 ;
     RECT  76.387 96.732 76.423 98.874 ;
     RECT  75.667 103.752 76.423 129.42 ;
     RECT  76.351 89.856 76.531 89.874 ;
     RECT  76.387 48.276 76.639 54.126 ;
     RECT  76.099 55.188 76.639 55.71 ;
     RECT  76.423 103.752 76.639 129.762 ;
     RECT  76.351 42.462 76.747 43.164 ;
     RECT  76.639 103.212 76.819 129.924 ;
     RECT  76.063 46.512 76.891 46.53 ;
     RECT  76.387 85.392 76.891 88.686 ;
     RECT  76.747 42.462 76.927 43.29 ;
     RECT  76.387 44.19 76.927 44.784 ;
     RECT  76.315 91.476 76.927 91.494 ;
     RECT  76.423 92.25 76.927 98.874 ;
     RECT  76.819 103.212 76.927 130.464 ;
     RECT  76.387 131.292 76.927 131.544 ;
     RECT  76.387 133.056 76.963 133.074 ;
     RECT  75.335 2.151 77.22 41.049 ;
     RECT  76.927 42.462 77.22 44.784 ;
     RECT  76.891 46.512 77.22 46.674 ;
     RECT  76.639 48.276 77.22 55.71 ;
     RECT  75.803 60.552 77.22 84.249 ;
     RECT  76.891 85.356 77.22 88.686 ;
     RECT  76.531 89.82 77.22 89.874 ;
     RECT  76.927 91.476 77.22 98.874 ;
     RECT  76.711 100.746 77.22 100.764 ;
     RECT  76.927 103.212 77.22 131.544 ;
     RECT  76.963 132.516 77.22 133.074 ;
     RECT  76.387 133.956 77.22 138.87 ;
     RECT  75.192 139.932 77.22 141.066 ;
     RECT  76.135 141.894 77.22 142.884 ;
     RECT  75.192 143.946 77.22 143.964 ;
     RECT  76.063 146.178 77.22 146.196 ;
     RECT  75.407 146.952 77.22 168.489 ;
     RECT  77.22 2.151 96.12 168.489 ;
     RECT  96.12 38.556 96.323 43.866 ;
     RECT  96.12 138.996 96.323 143.802 ;
     RECT  96.323 38.556 96.359 40.662 ;
     RECT  96.12 81.216 96.359 85.752 ;
     RECT  96.323 138.996 96.359 141.138 ;
     RECT  96.359 139.158 96.395 139.554 ;
     RECT  96.359 39.024 96.935 40.662 ;
     RECT  96.323 41.418 96.935 43.866 ;
     RECT  96.12 52.596 96.935 57.132 ;
     RECT  96.359 81.648 96.935 85.752 ;
     RECT  96.12 97.038 96.935 100.836 ;
     RECT  96.12 126.468 96.935 128.646 ;
     RECT  96.395 139.158 96.935 139.482 ;
     RECT  96.359 140.472 96.935 141.138 ;
     RECT  96.323 141.894 96.935 143.802 ;
     RECT  96.935 41.418 96.971 43.596 ;
     RECT  96.935 52.596 96.971 54.702 ;
     RECT  96.935 97.038 96.971 97.326 ;
     RECT  96.935 127.818 96.971 128.646 ;
     RECT  96.935 39.024 97.511 39.042 ;
     RECT  96.935 39.906 97.511 40.662 ;
     RECT  96.971 41.454 97.511 43.596 ;
     RECT  96.971 52.596 97.511 53.154 ;
     RECT  96.971 54.216 97.511 54.702 ;
     RECT  96.935 55.458 97.511 56.898 ;
     RECT  96.935 81.648 97.511 83.052 ;
     RECT  96.935 84.114 97.511 84.474 ;
     RECT  96.935 85.734 97.511 85.752 ;
     RECT  96.971 97.038 97.511 97.056 ;
     RECT  96.935 98.226 97.511 100.836 ;
     RECT  96.12 125.154 97.511 125.676 ;
     RECT  96.935 126.468 97.511 127.026 ;
     RECT  96.971 127.818 97.511 128.484 ;
     RECT  96.935 139.464 97.511 139.482 ;
     RECT  96.935 140.616 97.511 141.138 ;
     RECT  96.935 141.894 97.511 142.992 ;
     RECT  96.935 143.784 97.511 143.802 ;
     RECT  97.511 42.03 97.547 42.516 ;
     RECT  97.511 43.578 97.547 43.596 ;
     RECT  97.511 82.296 97.547 82.314 ;
     RECT  97.511 84.456 97.547 84.474 ;
     RECT  97.511 99.036 97.547 100.134 ;
     RECT  97.511 127.818 97.547 127.944 ;
     RECT  97.511 140.886 97.547 140.904 ;
     RECT  97.511 141.966 97.547 141.984 ;
     RECT  97.511 142.776 97.547 142.794 ;
     RECT  97.547 127.818 98.195 127.836 ;
     RECT  98.167 83.502 98.267 83.52 ;
     RECT  97.547 99.036 98.267 99.054 ;
    LAYER M3 ;
     RECT  2.415 2.143 2.505 2.413 ;
     RECT  5.115 2.143 5.205 2.413 ;
     RECT  7.815 2.143 7.905 2.413 ;
     RECT  10.515 2.143 10.605 2.413 ;
     RECT  13.215 2.143 13.305 2.413 ;
     RECT  15.915 2.143 16.005 2.413 ;
     RECT  18.615 2.143 18.705 2.413 ;
     RECT  21.315 2.143 21.405 2.413 ;
     RECT  24.015 2.143 24.105 2.413 ;
     RECT  26.715 2.143 26.805 2.413 ;
     RECT  29.415 2.143 29.505 2.413 ;
     RECT  32.115 2.143 32.205 2.413 ;
     RECT  34.815 2.143 34.905 2.413 ;
     RECT  37.515 2.143 37.605 2.413 ;
     RECT  40.215 2.143 40.305 2.413 ;
     RECT  42.915 2.143 43.005 2.413 ;
     RECT  45.615 2.143 45.705 2.413 ;
     RECT  48.315 2.143 48.405 2.413 ;
     RECT  51.015 2.143 51.105 2.413 ;
     RECT  53.715 2.143 53.805 2.413 ;
     RECT  56.415 2.143 56.505 2.413 ;
     RECT  59.115 2.143 59.205 2.413 ;
     RECT  61.815 2.143 61.905 2.413 ;
     RECT  64.515 2.143 64.605 2.413 ;
     RECT  67.215 2.143 67.305 2.413 ;
     RECT  69.915 2.143 70.005 2.413 ;
     RECT  72.615 2.143 72.705 2.413 ;
     RECT  75.315 2.143 75.405 2.413 ;
     RECT  78.015 2.143 78.105 2.413 ;
     RECT  80.715 2.143 80.805 2.413 ;
     RECT  83.415 2.143 83.505 2.413 ;
     RECT  86.115 2.143 86.205 2.413 ;
     RECT  88.815 2.143 88.905 2.413 ;
     RECT  91.515 2.143 91.605 2.413 ;
     RECT  94.215 2.143 94.305 2.413 ;
     RECT  2.415 2.413 2.697 31.723 ;
     RECT  3.888 31.723 3.906 31.801 ;
     RECT  5.115 2.413 5.397 31.801 ;
     RECT  0.108 31.675 0.126 31.829 ;
     RECT  2.088 31.723 2.697 31.853 ;
     RECT  2.304 31.853 2.697 31.891 ;
     RECT  3.636 31.801 5.397 31.891 ;
     RECT  7.02 31.801 7.038 31.891 ;
     RECT  0.144 32.107 0.162 32.251 ;
     RECT  6.948 31.891 7.038 32.305 ;
     RECT  6.768 32.305 7.038 32.341 ;
     RECT  7.815 2.413 8.097 32.341 ;
     RECT  0.144 32.251 0.234 32.369 ;
     RECT  3.636 31.891 5.454 32.431 ;
     RECT  2.304 31.891 2.862 32.459 ;
     RECT  6.768 32.341 8.097 32.467 ;
     RECT  9.396 31.891 9.414 32.467 ;
     RECT  2.415 32.459 2.862 32.491 ;
     RECT  3.636 32.431 5.598 32.491 ;
     RECT  6.768 32.467 9.414 32.611 ;
     RECT  0.144 32.369 0.162 32.717 ;
     RECT  2.415 32.491 5.598 32.809 ;
     RECT  6.552 32.611 9.414 32.809 ;
     RECT  2.415 32.809 9.414 33.421 ;
     RECT  0.108 32.827 0.126 33.449 ;
     RECT  42.915 2.413 43.197 33.583 ;
     RECT  2.415 33.421 9.45 33.611 ;
     RECT  0.144 33.691 0.198 34.109 ;
     RECT  42.336 33.583 43.197 34.159 ;
     RECT  2.415 33.611 8.73 34.501 ;
     RECT  2.415 34.501 9.126 34.619 ;
     RECT  0.54 34.501 0.558 34.843 ;
     RECT  0.144 34.843 0.558 34.973 ;
     RECT  0.54 34.973 0.558 35.165 ;
     RECT  42.012 34.159 43.197 35.203 ;
     RECT  10.515 2.413 10.797 35.509 ;
     RECT  2.415 34.619 9.09 35.545 ;
     RECT  2.415 35.545 9.342 35.563 ;
     RECT  2.304 35.563 9.342 35.609 ;
     RECT  10.515 35.509 10.854 35.609 ;
     RECT  2.415 35.609 9.342 35.735 ;
     RECT  2.415 35.735 8.874 35.771 ;
     RECT  38.772 35.707 38.79 35.843 ;
     RECT  2.415 35.771 8.694 35.879 ;
     RECT  0.108 35.707 0.162 35.969 ;
     RECT  6.84 35.879 8.694 36.113 ;
     RECT  2.415 35.879 6.102 36.239 ;
     RECT  10.515 35.609 10.818 36.275 ;
     RECT  0.108 35.969 0.126 36.311 ;
     RECT  38.808 36.283 38.826 36.383 ;
     RECT  4.536 36.239 6.102 36.907 ;
     RECT  6.948 36.113 8.694 36.941 ;
     RECT  4.536 36.907 6.174 37.193 ;
     RECT  41.616 35.203 43.197 37.193 ;
     RECT  40.215 2.413 40.497 37.327 ;
     RECT  2.415 36.239 3.726 38.003 ;
     RECT  7.02 36.941 8.694 38.039 ;
     RECT  41.724 37.193 43.197 38.309 ;
     RECT  95.796 38.371 95.814 38.551 ;
     RECT  95.796 38.551 96.354 38.713 ;
     RECT  94.215 2.413 94.497 38.821 ;
     RECT  91.515 2.413 91.797 38.947 ;
     RECT  88.815 2.413 89.097 39.091 ;
     RECT  91.515 38.947 91.89 39.091 ;
     RECT  94.215 38.821 94.698 39.091 ;
     RECT  2.415 38.003 3.51 39.119 ;
     RECT  75.315 2.413 75.597 39.181 ;
     RECT  92.664 39.181 92.682 39.307 ;
     RECT  93.636 39.091 94.698 39.307 ;
     RECT  95.76 38.713 96.354 39.307 ;
     RECT  97.488 38.875 97.506 39.307 ;
     RECT  90.396 39.019 90.414 39.325 ;
     RECT  91.224 39.091 91.89 39.325 ;
     RECT  95.76 39.307 97.506 39.389 ;
     RECT  90.396 39.325 91.89 39.451 ;
     RECT  92.664 39.307 94.698 39.451 ;
     RECT  86.115 2.413 86.397 39.523 ;
     RECT  85.572 39.523 86.397 39.559 ;
     RECT  75.276 39.181 75.597 39.595 ;
     RECT  83.415 2.413 83.697 39.631 ;
     RECT  88.815 39.091 89.622 39.631 ;
     RECT  90.396 39.451 94.698 39.631 ;
     RECT  85.572 39.559 86.706 39.659 ;
     RECT  75.276 39.595 76.194 39.721 ;
     RECT  88.815 39.631 94.698 39.749 ;
     RECT  80.715 2.413 80.997 39.757 ;
     RECT  82.764 39.631 83.697 39.757 ;
     RECT  85.572 39.659 86.67 39.785 ;
     RECT  82.152 39.757 83.697 39.829 ;
     RECT  90.648 39.749 94.698 39.829 ;
     RECT  41.832 38.309 43.197 39.901 ;
     RECT  75.276 39.721 76.374 39.901 ;
     RECT  90.648 39.829 95.202 39.917 ;
     RECT  80.352 39.757 80.997 39.929 ;
     RECT  41.724 39.901 43.197 40.019 ;
     RECT  75.132 39.901 76.374 40.019 ;
     RECT  10.515 36.275 10.797 40.099 ;
     RECT  13.215 2.413 13.497 40.099 ;
     RECT  10.515 40.099 10.854 40.123 ;
     RECT  40.215 37.327 40.878 40.135 ;
     RECT  90.648 39.917 94.698 40.163 ;
     RECT  10.515 40.123 11.43 40.165 ;
     RECT  78.015 2.413 78.297 40.171 ;
     RECT  13.215 40.099 13.554 40.199 ;
     RECT  10.515 40.165 11.826 40.289 ;
     RECT  11.808 40.289 11.826 40.349 ;
     RECT  96.3 39.389 97.506 40.441 ;
     RECT  75.204 40.019 76.374 40.531 ;
     RECT  3.492 39.119 3.51 40.555 ;
     RECT  4.536 37.193 6.102 40.555 ;
     RECT  88.815 39.749 89.91 40.603 ;
     RECT  90.648 40.163 94.554 40.603 ;
     RECT  77.364 40.171 78.297 40.711 ;
     RECT  82.08 39.829 83.697 40.711 ;
     RECT  7.02 38.039 8.658 40.739 ;
     RECT  41.832 40.019 43.197 40.787 ;
     RECT  45.615 2.413 45.897 40.787 ;
     RECT  48.315 2.413 48.597 40.787 ;
     RECT  51.015 2.413 51.297 40.787 ;
     RECT  53.715 2.413 53.997 40.787 ;
     RECT  56.415 2.413 56.697 40.787 ;
     RECT  59.115 2.413 59.397 40.787 ;
     RECT  61.815 2.413 62.097 40.787 ;
     RECT  64.515 2.413 64.797 40.787 ;
     RECT  67.215 2.413 67.497 40.787 ;
     RECT  69.915 2.413 70.197 40.787 ;
     RECT  72.615 2.413 72.897 40.787 ;
     RECT  75.204 40.531 76.41 40.801 ;
     RECT  77.364 40.711 78.678 40.829 ;
     RECT  82.08 40.711 83.826 40.829 ;
     RECT  85.248 40.711 85.266 40.865 ;
     RECT  75.132 40.801 76.41 40.909 ;
     RECT  77.364 40.829 78.297 40.909 ;
     RECT  75.132 40.909 78.297 40.937 ;
     RECT  86.115 39.785 86.67 40.937 ;
     RECT  2.415 39.119 2.697 40.945 ;
     RECT  3.492 40.555 6.102 40.945 ;
     RECT  88.815 40.603 94.554 40.973 ;
     RECT  95.76 40.441 97.506 40.981 ;
     RECT  0.108 40.891 0.126 41.009 ;
     RECT  82.08 40.829 83.697 41.009 ;
     RECT  88.815 40.973 94.497 41.009 ;
     RECT  2.415 40.945 6.102 41.035 ;
     RECT  45.615 40.787 45.705 41.057 ;
     RECT  48.315 40.787 48.405 41.057 ;
     RECT  51.015 40.787 51.105 41.057 ;
     RECT  53.715 40.787 53.805 41.057 ;
     RECT  56.415 40.787 56.505 41.057 ;
     RECT  59.115 40.787 59.205 41.057 ;
     RECT  61.815 40.787 61.905 41.057 ;
     RECT  64.515 40.787 64.605 41.057 ;
     RECT  67.215 40.787 67.305 41.057 ;
     RECT  69.915 40.787 70.005 41.057 ;
     RECT  72.615 40.787 72.705 41.057 ;
     RECT  2.304 41.035 6.102 41.099 ;
     RECT  82.08 41.009 82.17 41.099 ;
     RECT  82.152 41.099 82.17 41.171 ;
     RECT  95.364 40.981 97.506 41.207 ;
     RECT  85.32 41.107 85.338 41.215 ;
     RECT  86.115 40.937 86.397 41.215 ;
     RECT  85.32 41.215 86.397 41.243 ;
     RECT  9.36 41.251 9.378 41.369 ;
     RECT  40.215 40.135 41.022 41.449 ;
     RECT  96.912 41.207 97.506 41.467 ;
     RECT  85.392 41.243 86.397 41.477 ;
     RECT  7.02 40.739 8.622 41.521 ;
     RECT  96.912 41.467 97.578 41.597 ;
     RECT  2.415 41.099 6.102 41.611 ;
     RECT  95.364 41.207 95.922 41.648 ;
     RECT  0.144 41.323 0.162 41.741 ;
     RECT  96.912 41.597 97.542 41.747 ;
     RECT  91.224 41.009 94.497 41.749 ;
     RECT  95.364 41.648 95.454 41.749 ;
     RECT  91.224 41.749 95.454 41.755 ;
     RECT  88.815 41.009 90.054 41.791 ;
     RECT  90.864 41.755 95.454 41.791 ;
     RECT  10.515 40.289 10.797 41.989 ;
     RECT  39.636 41.449 41.022 41.989 ;
     RECT  0.108 42.043 0.126 42.089 ;
     RECT  10.515 41.989 10.854 42.089 ;
     RECT  7.02 41.521 8.658 42.151 ;
     RECT  75.204 40.937 78.297 42.151 ;
     RECT  79.488 41.881 79.506 42.151 ;
     RECT  2.415 41.611 6.138 42.187 ;
     RECT  6.876 42.151 8.658 42.187 ;
     RECT  86.115 41.477 86.397 42.223 ;
     RECT  87.624 41.881 87.642 42.259 ;
     RECT  2.415 42.187 8.658 42.331 ;
     RECT  82.62 41.881 82.638 42.331 ;
     RECT  86.115 42.223 86.742 42.331 ;
     RECT  87.516 42.259 87.642 42.331 ;
     RECT  82.008 42.331 82.638 42.449 ;
     RECT  86.115 42.331 87.642 42.449 ;
     RECT  96.336 42.043 96.642 42.449 ;
     RECT  97.488 41.747 97.542 42.475 ;
     RECT  82.08 42.449 82.638 42.521 ;
     RECT  86.115 42.449 86.814 42.521 ;
     RECT  82.332 42.521 82.638 42.529 ;
     RECT  83.415 41.009 83.697 42.529 ;
     RECT  87.552 42.449 87.642 42.529 ;
     RECT  75.204 42.151 79.506 42.601 ;
     RECT  82.332 42.529 83.697 42.601 ;
     RECT  88.815 41.791 95.454 42.619 ;
     RECT  0.54 42.601 0.558 42.653 ;
     RECT  85.212 42.565 85.23 42.719 ;
     RECT  88.815 42.619 95.778 42.719 ;
     RECT  75.204 42.601 79.614 42.727 ;
     RECT  87.552 42.529 87.858 42.755 ;
     RECT  97.452 42.475 97.542 42.763 ;
     RECT  9.684 41.719 9.702 42.871 ;
     RECT  75.204 42.727 79.758 42.997 ;
     RECT  39.6 41.989 41.022 43.033 ;
     RECT  39.528 43.033 41.022 43.069 ;
     RECT  9.684 42.871 9.738 43.097 ;
     RECT  87.84 42.755 87.858 43.097 ;
     RECT  96.912 42.763 97.542 43.195 ;
     RECT  41.832 40.787 43.11 43.2 ;
     RECT  70.704 43.069 70.722 43.2 ;
     RECT  74.664 42.997 79.758 43.2 ;
     RECT  82.332 42.601 84.33 43.295 ;
     RECT  86.115 42.521 86.742 43.295 ;
     RECT  86.115 43.295 86.634 43.331 ;
     RECT  88.815 42.719 95.382 43.331 ;
     RECT  83.232 43.295 84.33 43.375 ;
     RECT  2.415 42.331 8.802 43.411 ;
     RECT  88.815 43.331 90.702 43.439 ;
     RECT  96.336 43.195 97.542 43.439 ;
     RECT  10.515 42.089 10.797 43.501 ;
     RECT  82.332 43.295 82.386 43.501 ;
     RECT  88.815 43.439 89.154 43.565 ;
     RECT  96.912 43.439 97.542 43.601 ;
     RECT  10.515 43.501 10.854 43.673 ;
     RECT  91.476 43.331 94.497 43.673 ;
     RECT  83.232 43.375 84.51 43.681 ;
     RECT  90.072 43.439 90.702 43.709 ;
     RECT  95.364 43.331 95.382 43.799 ;
     RECT  39.024 43.069 41.022 43.843 ;
     RECT  41.832 43.2 79.758 43.843 ;
     RECT  0.108 43.195 0.126 43.871 ;
     RECT  90.072 43.709 90.342 43.871 ;
     RECT  96.912 43.601 96.93 43.871 ;
     RECT  82.044 43.501 82.386 44.041 ;
     RECT  83.232 43.681 84.618 44.041 ;
     RECT  90.324 43.871 90.342 44.105 ;
     RECT  2.415 43.411 9.162 44.141 ;
     RECT  39.024 43.843 79.758 44.185 ;
     RECT  2.415 44.141 5.397 44.203 ;
     RECT  2.304 44.203 5.397 44.249 ;
     RECT  86.115 43.331 86.397 44.347 ;
     RECT  6.3 44.141 9.162 44.411 ;
     RECT  38.844 44.185 79.758 44.411 ;
     RECT  86.115 44.347 86.67 44.447 ;
     RECT  91.515 43.673 94.497 44.477 ;
     RECT  6.624 44.411 9.162 44.491 ;
     RECT  6.624 44.491 9.414 44.609 ;
     RECT  91.515 44.477 92.466 44.645 ;
     RECT  0.54 44.311 0.558 44.779 ;
     RECT  0.144 44.779 0.558 44.909 ;
     RECT  6.624 44.609 9.198 44.951 ;
     RECT  0.54 44.909 0.558 44.957 ;
     RECT  79.596 44.411 79.758 45.023 ;
     RECT  91.515 44.645 92.43 45.023 ;
     RECT  79.74 45.023 79.758 45.245 ;
     RECT  38.844 44.411 78.297 45.301 ;
     RECT  2.415 44.249 5.397 45.355 ;
     RECT  2.304 45.355 5.397 45.419 ;
     RECT  6.624 44.951 9.162 45.419 ;
     RECT  93.276 44.477 94.497 45.491 ;
     RECT  38.844 45.301 78.642 45.661 ;
     RECT  2.415 45.419 5.397 45.688 ;
     RECT  6.624 45.419 8.622 45.688 ;
     RECT  2.415 45.688 8.622 45.689 ;
     RECT  38.772 45.661 78.642 45.691 ;
     RECT  2.415 45.689 7.074 45.725 ;
     RECT  82.044 44.041 84.618 45.725 ;
     RECT  82.044 45.725 82.602 45.773 ;
     RECT  86.115 44.447 86.397 45.841 ;
     RECT  80.715 39.929 80.997 45.979 ;
     RECT  86.115 45.841 86.67 45.995 ;
     RECT  86.115 45.995 86.634 46.067 ;
     RECT  82.332 45.773 82.602 46.301 ;
     RECT  91.515 45.023 92.322 46.381 ;
     RECT  2.415 45.725 5.397 46.499 ;
     RECT  91.368 46.381 92.322 46.571 ;
     RECT  80.715 45.979 81.522 46.603 ;
     RECT  82.332 46.301 82.35 46.603 ;
     RECT  80.715 46.603 82.35 46.679 ;
     RECT  38.772 45.691 78.678 46.688 ;
     RECT  77.544 46.688 78.678 46.769 ;
     RECT  93.276 45.491 93.474 46.769 ;
     RECT  91.368 46.571 92.07 46.777 ;
     RECT  34.815 2.413 35.097 46.813 ;
     RECT  77.58 46.769 78.678 46.877 ;
     RECT  34.776 46.813 35.097 46.913 ;
     RECT  81.756 46.679 82.35 46.949 ;
     RECT  77.58 46.877 78.642 46.973 ;
     RECT  83.376 45.725 84.546 47.011 ;
     RECT  90.684 46.777 92.07 47.039 ;
     RECT  86.115 46.067 86.562 47.047 ;
     RECT  90.684 47.039 91.797 47.075 ;
     RECT  86.115 47.047 86.706 47.147 ;
     RECT  82.332 46.949 82.35 47.281 ;
     RECT  83.232 47.011 84.546 47.281 ;
     RECT  93.456 46.769 93.474 47.309 ;
     RECT  91.224 47.075 91.797 47.345 ;
     RECT  77.904 46.973 78.642 47.357 ;
     RECT  82.332 47.281 84.546 47.579 ;
     RECT  92.628 47.461 92.646 47.615 ;
     RECT  38.772 46.688 76.734 47.645 ;
     RECT  86.115 47.147 86.67 47.687 ;
     RECT  38.772 47.645 41.85 47.789 ;
     RECT  6.228 45.725 7.074 48.227 ;
     RECT  34.815 46.913 35.097 48.271 ;
     RECT  38.952 47.789 41.85 48.433 ;
     RECT  42.768 47.645 76.734 48.433 ;
     RECT  77.904 47.357 78.297 48.433 ;
     RECT  3.42 46.499 5.397 48.659 ;
     RECT  34.776 48.271 35.097 48.803 ;
     RECT  77.616 48.433 78.297 48.811 ;
     RECT  38.952 48.433 76.734 48.901 ;
     RECT  38.88 48.901 76.734 49.085 ;
     RECT  6.228 48.227 6.858 49.109 ;
     RECT  38.88 49.085 42.246 49.243 ;
     RECT  38.772 49.243 42.246 49.277 ;
     RECT  77.544 48.811 78.297 49.277 ;
     RECT  7.815 45.689 8.622 49.343 ;
     RECT  6.228 49.109 6.246 49.379 ;
     RECT  38.772 49.277 42.21 49.379 ;
     RECT  38.88 49.379 42.21 49.613 ;
     RECT  7.815 49.343 8.406 49.649 ;
     RECT  34.815 48.803 35.097 49.711 ;
     RECT  3.42 48.659 4.122 49.739 ;
     RECT  38.952 49.613 42.21 49.919 ;
     RECT  77.616 49.277 78.297 49.949 ;
     RECT  4.104 49.739 4.122 50.009 ;
     RECT  83.376 47.579 84.546 50.009 ;
     RECT  39.384 49.919 42.21 50.017 ;
     RECT  86.115 47.687 86.397 50.017 ;
     RECT  91.515 47.345 91.797 50.017 ;
     RECT  34.776 49.711 35.097 50.153 ;
     RECT  4.86 48.659 5.397 50.189 ;
     RECT  43.2 49.085 76.734 50.237 ;
     RECT  77.652 49.949 78.297 50.323 ;
     RECT  80.715 46.679 80.997 50.323 ;
     RECT  80.712 50.323 80.997 50.395 ;
     RECT  82.332 47.579 82.35 50.395 ;
     RECT  83.376 50.009 83.697 50.395 ;
     RECT  77.652 50.323 78.75 50.423 ;
     RECT  39.384 50.017 42.246 50.431 ;
     RECT  43.2 50.237 75.192 50.431 ;
     RECT  76.392 50.237 76.734 50.549 ;
     RECT  77.652 50.423 78.678 50.549 ;
     RECT  82.332 50.395 83.697 50.549 ;
     RECT  84.528 50.009 84.546 50.549 ;
     RECT  86.115 50.017 86.634 50.557 ;
     RECT  88.815 43.565 89.097 50.593 ;
     RECT  86.115 50.557 86.706 50.657 ;
     RECT  39.384 50.431 75.192 50.665 ;
     RECT  77.652 50.549 78.297 50.779 ;
     RECT  91.332 50.017 91.797 50.819 ;
     RECT  86.115 50.657 86.397 50.899 ;
     RECT  37.515 2.413 37.797 50.935 ;
     RECT  38.844 50.665 75.192 50.935 ;
     RECT  37.515 50.935 75.192 51.005 ;
     RECT  77.58 50.779 78.297 51.293 ;
     RECT  37.515 51.005 42.246 51.431 ;
     RECT  38.772 51.431 42.246 51.781 ;
     RECT  43.056 51.005 75.192 51.781 ;
     RECT  77.616 51.293 78.297 52.285 ;
     RECT  77.544 52.285 78.297 52.411 ;
     RECT  94.215 45.491 94.497 52.411 ;
     RECT  93.096 52.363 93.114 52.459 ;
     RECT  77.4 52.411 78.297 52.475 ;
     RECT  95.76 52.411 95.778 52.483 ;
     RECT  94.215 52.411 94.626 52.555 ;
     RECT  90.324 50.053 90.342 52.591 ;
     RECT  93.96 52.555 94.626 52.591 ;
     RECT  82.332 50.549 82.386 52.619 ;
     RECT  92.664 52.459 93.114 52.681 ;
     RECT  93.924 52.591 94.626 52.681 ;
     RECT  38.772 51.781 75.192 52.825 ;
     RECT  88.596 50.593 89.097 52.861 ;
     RECT  38.772 52.825 75.51 52.987 ;
     RECT  95.364 52.483 95.778 52.987 ;
     RECT  76.392 50.549 76.41 53.015 ;
     RECT  88.596 52.861 89.442 53.021 ;
     RECT  95.364 52.987 95.922 53.131 ;
     RECT  90.324 52.591 90.666 53.221 ;
     RECT  91.404 50.819 91.797 53.221 ;
     RECT  92.664 52.681 94.626 53.221 ;
     RECT  95.364 53.131 96.318 53.221 ;
     RECT  77.508 52.475 78.297 53.275 ;
     RECT  38.592 52.987 75.51 53.293 ;
     RECT  97.488 52.591 97.506 53.309 ;
     RECT  92.664 53.221 96.318 53.321 ;
     RECT  90.324 53.221 91.797 53.329 ;
     RECT  92.664 53.321 95.814 53.329 ;
     RECT  90.324 53.329 95.814 53.519 ;
     RECT  90.324 53.519 91.926 53.557 ;
     RECT  38.592 53.293 75.582 53.693 ;
     RECT  39.276 53.693 75.582 53.789 ;
     RECT  86.076 50.899 86.397 53.797 ;
     RECT  92.88 53.519 95.814 53.825 ;
     RECT  42.408 53.789 75.582 53.869 ;
     RECT  86.076 53.797 86.67 53.941 ;
     RECT  90.252 53.557 91.926 53.969 ;
     RECT  88.596 53.021 89.097 53.995 ;
     RECT  90.252 53.969 90.486 53.995 ;
     RECT  88.596 53.995 90.486 54.059 ;
     RECT  42.408 53.869 75.618 54.067 ;
     RECT  86.076 53.941 86.706 54.095 ;
     RECT  90.252 54.059 90.486 54.095 ;
     RECT  96.912 53.563 96.966 54.139 ;
     RECT  93.06 53.825 95.814 54.283 ;
     RECT  96.912 54.139 97.506 54.283 ;
     RECT  93.06 54.283 97.506 54.437 ;
     RECT  39.276 53.789 41.598 54.445 ;
     RECT  91.224 53.969 91.926 54.571 ;
     RECT  93.06 54.437 95.814 54.571 ;
     RECT  76.968 53.275 78.297 54.607 ;
     RECT  37.515 51.431 37.797 54.715 ;
     RECT  37.515 54.715 37.962 54.751 ;
     RECT  38.7 54.445 41.598 54.751 ;
     RECT  96.912 54.437 97.506 54.779 ;
     RECT  37.515 54.751 41.598 54.869 ;
     RECT  76.644 54.607 78.297 54.869 ;
     RECT  37.515 54.869 38.718 54.905 ;
     RECT  90.252 54.095 90.45 54.985 ;
     RECT  91.224 54.571 95.814 54.985 ;
     RECT  39.96 54.869 41.598 55.021 ;
     RECT  42.408 54.067 75.69 55.021 ;
     RECT  88.596 54.059 89.097 55.021 ;
     RECT  90.252 54.985 95.814 55.139 ;
     RECT  88.596 55.021 89.37 55.147 ;
     RECT  90.252 55.139 91.998 55.147 ;
     RECT  88.596 55.147 91.998 55.181 ;
     RECT  39.96 55.021 75.69 55.183 ;
     RECT  76.644 54.869 76.662 55.183 ;
     RECT  86.076 54.095 86.67 55.211 ;
     RECT  92.88 55.139 95.814 55.291 ;
     RECT  92.88 55.291 96.354 55.469 ;
     RECT  96.3 55.469 96.354 55.723 ;
     RECT  97.488 54.779 97.506 55.723 ;
     RECT  82.368 52.619 82.386 55.957 ;
     RECT  80.64 50.395 80.997 55.985 ;
     RECT  96.3 55.723 97.506 56.057 ;
     RECT  88.596 55.181 91.797 56.191 ;
     RECT  87.408 56.101 87.426 56.219 ;
     RECT  82.368 55.957 82.674 56.489 ;
     RECT  92.88 55.469 95.382 56.489 ;
     RECT  82.656 56.489 82.674 56.669 ;
     RECT  88.596 56.191 91.854 56.669 ;
     RECT  92.916 56.489 95.382 56.759 ;
     RECT  92.988 56.759 95.382 56.875 ;
     RECT  88.815 56.669 91.854 56.903 ;
     RECT  96.912 56.057 97.506 56.903 ;
     RECT  92.988 56.875 95.778 56.939 ;
     RECT  86.076 55.211 86.397 57.029 ;
     RECT  92.988 56.939 95.382 57.065 ;
     RECT  96.912 56.903 96.93 57.137 ;
     RECT  88.815 56.903 91.797 57.209 ;
     RECT  88.02 57.181 88.038 57.299 ;
     RECT  77.436 54.869 78.297 58.649 ;
     RECT  39.96 55.183 76.662 60.504 ;
     RECT  39.96 60.504 43.146 60.575 ;
     RECT  70.704 60.504 70.794 60.647 ;
     RECT  74.736 60.504 76.662 60.647 ;
     RECT  90.9 57.209 91.797 60.683 ;
     RECT  74.808 60.647 76.662 60.719 ;
     RECT  70.704 60.647 70.722 60.917 ;
     RECT  74.808 60.719 76.194 60.917 ;
     RECT  93.6 57.065 95.382 61.115 ;
     RECT  42.444 60.575 43.146 61.151 ;
     RECT  42.516 61.151 43.146 61.187 ;
     RECT  93.6 61.115 94.497 61.187 ;
     RECT  88.815 57.209 89.982 61.223 ;
     RECT  75.204 60.917 76.194 61.259 ;
     RECT  77.796 58.649 78.297 61.421 ;
     RECT  39.96 60.575 41.598 61.457 ;
     RECT  75.204 61.259 76.122 61.457 ;
     RECT  41.292 61.457 41.598 61.619 ;
     RECT  91.044 60.683 91.797 61.619 ;
     RECT  95.364 61.115 95.382 61.889 ;
     RECT  50.076 61.861 50.094 62.473 ;
     RECT  42.732 61.187 43.146 62.501 ;
     RECT  50.076 62.473 50.202 62.509 ;
     RECT  93.78 61.187 94.497 62.537 ;
     RECT  49.248 62.509 50.202 62.581 ;
     RECT  88.815 61.223 89.766 62.609 ;
     RECT  49.176 62.581 50.202 62.699 ;
     RECT  42.915 62.501 43.146 62.893 ;
     RECT  45.615 62.623 45.705 62.893 ;
     RECT  48.315 62.623 48.405 62.893 ;
     RECT  51.015 62.623 51.105 62.893 ;
     RECT  53.715 62.623 53.805 62.893 ;
     RECT  56.415 62.623 56.505 62.893 ;
     RECT  59.115 62.623 59.205 62.893 ;
     RECT  61.815 62.623 61.905 62.893 ;
     RECT  64.515 62.623 64.605 62.893 ;
     RECT  67.215 62.623 67.305 62.893 ;
     RECT  69.915 62.623 70.005 62.893 ;
     RECT  72.615 62.623 72.705 62.893 ;
     RECT  75.204 61.457 75.474 62.893 ;
     RECT  75.204 62.893 75.597 63.275 ;
     RECT  42.915 62.893 43.197 64.561 ;
     RECT  42.915 64.561 43.542 64.859 ;
     RECT  42.915 64.859 43.326 64.877 ;
     RECT  42.915 64.877 43.254 64.973 ;
     RECT  76.824 73.741 76.842 73.771 ;
     RECT  61.815 62.893 62.097 73.915 ;
     RECT  69.915 62.893 70.197 73.915 ;
     RECT  46.764 73.819 46.782 73.949 ;
     RECT  54.72 73.819 54.738 73.949 ;
     RECT  76.824 73.771 77.13 73.949 ;
     RECT  61.815 73.915 62.73 74.093 ;
     RECT  69.915 73.915 70.722 74.093 ;
     RECT  76.824 73.949 76.842 74.309 ;
     RECT  13.215 40.199 13.497 74.821 ;
     RECT  13.104 74.821 13.497 74.875 ;
     RECT  13.104 74.875 13.662 74.921 ;
     RECT  7.815 49.649 8.097 78.637 ;
     RECT  42.915 64.973 43.197 78.637 ;
     RECT  5.115 50.189 5.397 78.745 ;
     RECT  7.2 78.637 8.097 78.745 ;
     RECT  4.032 78.709 4.05 78.781 ;
     RECT  5.115 78.745 5.706 78.781 ;
     RECT  4.032 78.781 5.706 78.871 ;
     RECT  7.128 78.745 8.097 78.907 ;
     RECT  42.624 78.637 43.197 78.943 ;
     RECT  0.108 78.907 0.126 78.955 ;
     RECT  3.852 78.871 5.706 78.979 ;
     RECT  3.744 78.979 5.706 79.015 ;
     RECT  7.056 78.907 8.097 79.051 ;
     RECT  41.544 61.619 41.598 79.051 ;
     RECT  42.588 78.943 43.197 79.051 ;
     RECT  0.108 78.955 0.198 79.085 ;
     RECT  6.552 79.051 8.097 79.141 ;
     RECT  3.636 79.015 5.706 79.169 ;
     RECT  6.552 79.141 8.586 79.169 ;
     RECT  4.104 79.169 5.706 79.285 ;
     RECT  0.108 79.085 0.162 79.373 ;
     RECT  4.104 79.285 5.778 79.439 ;
     RECT  6.552 79.169 7.074 79.439 ;
     RECT  2.415 46.499 2.697 79.555 ;
     RECT  0.108 79.373 0.126 79.619 ;
     RECT  7.815 79.169 8.586 79.789 ;
     RECT  4.104 79.439 5.706 79.805 ;
     RECT  2.415 79.555 2.79 79.915 ;
     RECT  6.768 79.439 7.074 79.979 ;
     RECT  7.815 79.789 9.054 79.979 ;
     RECT  4.104 79.805 5.598 80.059 ;
     RECT  6.768 79.979 6.786 80.159 ;
     RECT  7.815 79.979 8.262 80.221 ;
     RECT  41.544 79.051 43.197 80.293 ;
     RECT  3.636 80.059 5.598 80.299 ;
     RECT  9.108 80.365 9.198 80.519 ;
     RECT  9.108 80.519 9.126 80.591 ;
     RECT  2.304 79.915 2.79 80.671 ;
     RECT  3.6 80.299 5.598 80.671 ;
     RECT  6.732 80.671 6.75 80.905 ;
     RECT  7.524 80.221 8.262 80.905 ;
     RECT  2.304 80.671 5.598 80.969 ;
     RECT  6.732 80.905 8.262 81.031 ;
     RECT  2.415 80.969 5.598 81.067 ;
     RECT  6.48 81.031 8.262 81.131 ;
     RECT  37.515 54.905 38.502 81.175 ;
     RECT  95.76 81.031 95.778 81.211 ;
     RECT  2.415 81.067 5.706 81.239 ;
     RECT  80.715 55.985 80.997 81.301 ;
     RECT  6.588 81.131 8.262 81.329 ;
     RECT  94.215 62.537 94.497 81.355 ;
     RECT  95.76 81.211 96.354 81.355 ;
     RECT  10.515 43.673 10.797 81.409 ;
     RECT  94.215 81.355 96.354 81.445 ;
     RECT  6.732 81.329 7.074 81.473 ;
     RECT  37.515 81.175 38.826 81.473 ;
     RECT  75.315 63.275 75.597 81.481 ;
     RECT  0.108 80.635 0.126 81.499 ;
     RECT  0.108 81.499 0.162 81.509 ;
     RECT  10.515 81.409 10.854 81.509 ;
     RECT  91.515 61.619 91.797 81.571 ;
     RECT  92.664 81.481 92.682 81.571 ;
     RECT  93.492 81.445 96.354 81.571 ;
     RECT  2.415 81.239 5.67 81.599 ;
     RECT  80.715 81.301 81.522 81.599 ;
     RECT  39.96 61.457 40.497 81.607 ;
     RECT  91.476 81.571 91.797 81.607 ;
     RECT  92.664 81.571 96.354 81.607 ;
     RECT  91.476 81.607 96.354 81.671 ;
     RECT  9.288 81.643 9.306 81.715 ;
     RECT  39.96 81.607 40.554 81.779 ;
     RECT  0.144 81.509 0.162 81.787 ;
     RECT  9.288 81.715 9.342 81.869 ;
     RECT  9.288 81.869 9.306 81.941 ;
     RECT  93.996 81.671 96.354 81.977 ;
     RECT  85.284 81.715 85.302 82.013 ;
     RECT  90.648 81.643 90.666 82.013 ;
     RECT  91.476 81.671 93.222 82.021 ;
     RECT  0.144 81.787 0.558 82.049 ;
     RECT  3.672 81.599 5.67 82.049 ;
     RECT  3.816 82.049 5.67 82.111 ;
     RECT  13.215 74.921 13.497 82.111 ;
     RECT  21.315 2.413 21.597 82.111 ;
     RECT  13.104 82.111 13.497 82.157 ;
     RECT  21.204 82.111 21.597 82.157 ;
     RECT  0.144 82.049 0.162 82.205 ;
     RECT  6.768 81.473 7.074 82.219 ;
     RECT  7.815 81.329 8.262 82.219 ;
     RECT  9.18 82.111 9.198 82.219 ;
     RECT  97.488 81.499 97.506 82.219 ;
     RECT  14.832 82.123 14.85 82.253 ;
     RECT  22.824 82.123 22.842 82.253 ;
     RECT  30.78 82.123 30.798 82.253 ;
     RECT  3.816 82.111 5.886 82.255 ;
     RECT  6.768 82.219 9.198 82.255 ;
     RECT  88.815 62.609 89.097 82.291 ;
     RECT  97.488 82.219 97.542 82.319 ;
     RECT  6.732 82.255 9.198 82.409 ;
     RECT  83.415 50.549 83.697 82.417 ;
     RECT  2.415 81.599 2.697 82.489 ;
     RECT  97.488 82.319 97.506 82.507 ;
     RECT  75.315 81.481 76.014 82.525 ;
     RECT  91.008 82.021 93.222 82.561 ;
     RECT  93.996 81.977 95.778 82.561 ;
     RECT  0.108 82.363 0.126 82.589 ;
     RECT  83.415 82.417 83.754 82.589 ;
     RECT  2.415 82.489 3.042 82.651 ;
     RECT  86.115 57.029 86.397 82.651 ;
     RECT  88.815 82.291 89.19 82.723 ;
     RECT  90 82.525 90.018 82.723 ;
     RECT  88.815 82.723 90.018 82.759 ;
     RECT  91.008 82.561 95.778 82.759 ;
     RECT  3.816 82.255 5.922 82.795 ;
     RECT  6.732 82.409 6.93 82.795 ;
     RECT  75.096 82.525 76.014 82.831 ;
     RECT  86.115 82.651 86.562 82.831 ;
     RECT  2.304 82.651 3.042 82.921 ;
     RECT  3.816 82.795 6.93 82.921 ;
     RECT  88.815 82.759 95.778 82.939 ;
     RECT  2.304 82.921 6.93 82.973 ;
     RECT  88.815 82.939 95.922 82.985 ;
     RECT  37.515 81.473 38.79 83.029 ;
     RECT  96.912 82.507 97.506 83.057 ;
     RECT  39.96 81.779 40.497 83.101 ;
     RECT  41.508 80.293 43.197 83.101 ;
     RECT  78.015 61.421 78.297 83.101 ;
     RECT  2.304 82.973 3.294 83.129 ;
     RECT  4.212 82.973 6.93 83.219 ;
     RECT  88.815 82.985 95.814 83.219 ;
     RECT  85.788 82.831 86.562 83.227 ;
     RECT  2.415 83.129 3.294 83.255 ;
     RECT  0.18 83.227 0.198 83.263 ;
     RECT  0.18 83.263 0.27 83.309 ;
     RECT  85.788 83.227 86.67 83.327 ;
     RECT  88.815 83.219 95.274 83.357 ;
     RECT  0.18 83.309 0.198 83.371 ;
     RECT  0.108 83.371 0.198 83.399 ;
     RECT  4.212 83.219 5.778 83.399 ;
     RECT  92.88 83.357 95.274 83.399 ;
     RECT  0.108 83.399 0.126 83.408 ;
     RECT  78.015 83.101 78.678 83.497 ;
     RECT  98.244 83.467 98.262 83.497 ;
     RECT  4.932 83.399 5.778 83.525 ;
     RECT  98.172 83.497 98.262 83.525 ;
     RECT  98.172 83.525 98.19 83.549 ;
     RECT  78.015 83.497 78.75 83.597 ;
     RECT  7.815 82.409 8.694 83.605 ;
     RECT  37.515 83.029 38.826 83.605 ;
     RECT  85.788 83.327 86.634 83.605 ;
     RECT  39.96 83.101 43.197 83.611 ;
     RECT  78.015 83.597 78.297 83.641 ;
     RECT  6.516 83.219 6.93 83.669 ;
     RECT  82.656 83.533 82.674 83.669 ;
     RECT  7.815 83.605 8.73 83.731 ;
     RECT  6.516 83.669 6.606 83.759 ;
     RECT  39.96 83.611 43.614 83.759 ;
     RECT  37.515 83.605 38.898 83.795 ;
     RECT  39.96 83.759 43.29 83.795 ;
     RECT  7.776 83.731 8.73 83.803 ;
     RECT  96.912 83.057 96.93 83.803 ;
     RECT  2.415 83.255 2.79 83.837 ;
     RECT  85.284 83.605 86.634 83.867 ;
     RECT  45.615 62.893 45.897 83.987 ;
     RECT  48.315 62.893 48.597 83.987 ;
     RECT  51.015 62.893 51.297 83.987 ;
     RECT  53.715 62.893 53.997 83.987 ;
     RECT  56.415 62.893 56.697 83.987 ;
     RECT  59.115 62.893 59.397 83.987 ;
     RECT  61.815 74.093 62.097 83.987 ;
     RECT  67.215 62.893 67.497 83.987 ;
     RECT  69.915 74.093 70.197 83.987 ;
     RECT  72.615 62.893 72.897 83.987 ;
     RECT  4.932 83.525 5.397 84.029 ;
     RECT  7.776 83.803 8.766 84.029 ;
     RECT  37.515 83.795 38.826 84.029 ;
     RECT  39.96 83.795 43.218 84.029 ;
     RECT  44.784 84.073 44.802 84.125 ;
     RECT  88.815 83.357 91.926 84.139 ;
     RECT  88.815 84.139 91.998 84.145 ;
     RECT  92.88 83.399 95.202 84.145 ;
     RECT  64.515 62.893 64.797 84.181 ;
     RECT  85.572 83.867 86.634 84.181 ;
     RECT  96.912 83.803 97.542 84.209 ;
     RECT  64.515 84.181 64.998 84.221 ;
     RECT  88.815 84.145 95.778 84.235 ;
     RECT  45.615 83.987 45.705 84.257 ;
     RECT  48.315 83.987 48.405 84.257 ;
     RECT  51.015 83.987 51.105 84.257 ;
     RECT  53.715 83.987 53.805 84.257 ;
     RECT  56.415 83.987 56.505 84.257 ;
     RECT  59.115 83.987 59.205 84.257 ;
     RECT  61.815 83.987 61.905 84.257 ;
     RECT  64.515 84.221 64.674 84.257 ;
     RECT  67.215 83.987 67.305 84.257 ;
     RECT  69.915 83.987 70.005 84.257 ;
     RECT  72.615 83.987 72.705 84.257 ;
     RECT  7.776 84.029 8.262 84.271 ;
     RECT  7.704 84.271 8.262 84.299 ;
     RECT  85.572 84.181 86.67 84.299 ;
     RECT  88.815 84.235 96.354 84.299 ;
     RECT  7.704 84.299 8.226 84.317 ;
     RECT  85.716 84.299 86.67 84.335 ;
     RECT  41.508 84.029 43.218 84.365 ;
     RECT  64.656 84.257 64.674 84.365 ;
     RECT  97.524 84.209 97.542 84.479 ;
     RECT  2.415 83.837 2.697 84.721 ;
     RECT  83.415 82.589 83.697 84.721 ;
     RECT  0.54 84.667 0.558 84.749 ;
     RECT  2.415 84.721 3.078 84.811 ;
     RECT  3.996 84.541 4.014 84.811 ;
     RECT  5.115 84.029 5.397 84.811 ;
     RECT  37.515 84.029 38.79 84.811 ;
     RECT  39.96 84.029 40.626 84.811 ;
     RECT  83.415 84.721 84.078 84.811 ;
     RECT  83.376 84.811 84.078 84.847 ;
     RECT  2.304 84.811 3.078 84.848 ;
     RECT  3.996 84.811 5.397 84.848 ;
     RECT  5.04 84.848 5.397 84.907 ;
     RECT  5.04 84.907 5.49 84.941 ;
     RECT  83.376 84.847 84.258 84.947 ;
     RECT  75.096 82.831 76.41 84.989 ;
     RECT  37.515 84.811 40.626 84.991 ;
     RECT  41.508 84.365 43.074 84.991 ;
     RECT  95.724 84.299 96.354 84.991 ;
     RECT  77.364 83.641 78.297 85.081 ;
     RECT  2.415 84.848 3.078 85.109 ;
     RECT  3.996 84.848 4.266 85.109 ;
     RECT  7.815 84.317 8.226 85.117 ;
     RECT  85.716 84.335 86.397 85.117 ;
     RECT  85.716 85.117 86.634 85.145 ;
     RECT  7.776 85.117 8.226 85.153 ;
     RECT  77.364 85.081 78.678 85.181 ;
     RECT  7.632 85.153 8.226 85.225 ;
     RECT  0.18 85.099 0.198 85.243 ;
     RECT  37.515 84.991 43.074 85.253 ;
     RECT  95.724 84.991 96.93 85.253 ;
     RECT  3.996 85.109 4.23 85.261 ;
     RECT  6.804 84.721 6.822 85.261 ;
     RECT  83.376 84.947 84.222 85.261 ;
     RECT  88.815 84.299 94.662 85.261 ;
     RECT  7.632 85.225 8.37 85.351 ;
     RECT  9.18 85.261 9.198 85.351 ;
     RECT  75.132 84.989 76.41 85.351 ;
     RECT  77.364 85.181 78.297 85.351 ;
     RECT  88.452 85.261 94.662 85.351 ;
     RECT  3.852 85.261 4.23 85.379 ;
     RECT  86.004 85.145 86.634 85.379 ;
     RECT  6.804 85.261 6.858 85.387 ;
     RECT  7.632 85.351 9.198 85.451 ;
     RECT  80.715 81.599 80.997 85.459 ;
     RECT  6.552 85.387 6.858 85.531 ;
     RECT  7.632 85.451 8.226 85.531 ;
     RECT  96.336 85.253 96.93 85.531 ;
     RECT  88.452 85.351 94.842 85.559 ;
     RECT  0.108 85.243 0.198 85.568 ;
     RECT  6.552 85.531 8.226 85.685 ;
     RECT  96.336 85.531 97.506 85.709 ;
     RECT  96.912 85.709 97.506 85.721 ;
     RECT  86.115 85.379 86.634 85.757 ;
     RECT  97.488 85.721 97.506 85.757 ;
     RECT  80.715 85.459 81.306 85.801 ;
     RECT  82.332 85.621 82.35 85.801 ;
     RECT  83.232 85.261 84.222 85.801 ;
     RECT  88.452 85.559 89.097 85.801 ;
     RECT  90.216 85.559 94.842 85.819 ;
     RECT  9.18 85.451 9.198 85.829 ;
     RECT  4.14 85.379 4.23 85.891 ;
     RECT  5.115 84.941 5.49 85.891 ;
     RECT  82.332 85.801 84.474 85.919 ;
     RECT  88.272 85.801 89.097 85.919 ;
     RECT  90.216 85.819 95.202 85.919 ;
     RECT  2.415 85.109 2.934 85.955 ;
     RECT  80.715 85.801 81.414 86.035 ;
     RECT  90.216 85.919 94.497 86.045 ;
     RECT  4.14 85.891 5.49 86.071 ;
     RECT  4.14 86.071 5.67 86.161 ;
     RECT  4.068 86.161 5.67 86.203 ;
     RECT  6.84 85.685 8.226 86.203 ;
     RECT  90.36 86.045 94.497 86.225 ;
     RECT  91.515 86.225 94.497 86.261 ;
     RECT  93.204 86.261 94.497 86.297 ;
     RECT  34.815 50.153 35.097 86.305 ;
     RECT  39.348 85.253 43.074 86.333 ;
     RECT  90.36 86.225 90.702 86.333 ;
     RECT  37.515 85.253 38.502 86.341 ;
     RECT  2.415 85.955 2.862 86.369 ;
     RECT  4.068 86.203 5.706 86.369 ;
     RECT  35.928 85.927 35.946 86.369 ;
     RECT  39.6 86.333 43.074 86.4 ;
     RECT  75.132 85.351 78.297 86.4 ;
     RECT  0.54 85.801 0.558 86.429 ;
     RECT  83.232 85.919 84.474 86.495 ;
     RECT  87.876 86.341 87.894 86.495 ;
     RECT  4.068 86.369 5.49 86.503 ;
     RECT  86.115 85.757 86.397 86.503 ;
     RECT  9.108 86.431 9.126 86.531 ;
     RECT  37.515 86.341 38.826 86.567 ;
     RECT  34.776 86.305 35.097 86.603 ;
     RECT  86.115 86.503 86.67 86.603 ;
     RECT  6.84 86.203 8.262 86.701 ;
     RECT  39.6 86.4 78.297 86.729 ;
     RECT  6.84 86.701 8.298 86.836 ;
     RECT  6.84 86.836 8.334 86.845 ;
     RECT  6.444 86.845 8.334 86.923 ;
     RECT  39.636 86.729 78.297 87.151 ;
     RECT  80.715 86.035 81.522 87.163 ;
     RECT  39.636 87.151 78.39 87.197 ;
     RECT  3.996 86.503 5.49 87.211 ;
     RECT  6.444 86.923 8.982 87.211 ;
     RECT  90.36 86.333 90.378 87.241 ;
     RECT  3.996 87.211 8.982 87.385 ;
     RECT  9.756 87.313 9.774 87.385 ;
     RECT  2.415 86.369 2.697 87.403 ;
     RECT  37.515 86.567 38.502 87.421 ;
     RECT  83.232 86.495 83.697 87.421 ;
     RECT  80.676 87.163 81.522 87.451 ;
     RECT  3.996 87.385 9.774 87.539 ;
     RECT  86.115 86.603 86.397 87.547 ;
     RECT  90.36 87.241 90.666 87.575 ;
     RECT  80.388 87.451 81.522 87.629 ;
     RECT  86.115 87.547 86.634 87.647 ;
     RECT  83.232 87.421 83.754 87.691 ;
     RECT  84.492 86.611 84.51 87.691 ;
     RECT  0.108 86.683 0.126 87.719 ;
     RECT  37.515 87.421 38.826 87.853 ;
     RECT  37.515 87.853 38.862 87.952 ;
     RECT  91.515 86.261 92.43 87.961 ;
     RECT  93.276 86.297 94.497 87.961 ;
     RECT  4.5 87.539 9.774 88.087 ;
     RECT  10.515 81.509 10.797 88.087 ;
     RECT  91.476 87.961 94.497 88.109 ;
     RECT  37.515 87.952 38.898 88.115 ;
     RECT  37.515 88.115 38.79 88.187 ;
     RECT  39.636 87.197 78.297 88.195 ;
     RECT  2.304 87.403 2.697 88.219 ;
     RECT  3.42 88.123 3.438 88.219 ;
     RECT  4.5 88.087 10.797 88.259 ;
     RECT  2.304 88.219 3.438 88.349 ;
     RECT  3.42 88.349 3.438 88.429 ;
     RECT  4.5 88.259 9.558 88.429 ;
     RECT  82.332 85.919 82.422 88.445 ;
     RECT  80.64 87.629 81.522 88.493 ;
     RECT  0.144 88.459 0.162 88.589 ;
     RECT  39.564 88.195 78.297 88.591 ;
     RECT  82.404 88.445 82.422 88.627 ;
     RECT  83.232 87.691 84.51 88.627 ;
     RECT  82.404 88.627 84.51 88.691 ;
     RECT  3.42 88.429 9.558 88.727 ;
     RECT  82.62 88.691 84.51 88.733 ;
     RECT  82.62 88.733 84.402 88.763 ;
     RECT  2.304 88.349 2.697 88.771 ;
     RECT  2.088 88.771 2.697 88.877 ;
     RECT  3.42 88.727 9.306 88.889 ;
     RECT  39.564 88.591 78.354 88.925 ;
     RECT  77.472 88.925 78.354 88.987 ;
     RECT  77.472 88.987 78.678 89.021 ;
     RECT  82.656 88.763 84.402 89.021 ;
     RECT  91.515 88.109 94.497 89.033 ;
     RECT  77.544 89.021 78.678 89.035 ;
     RECT  79.488 86.035 79.506 89.035 ;
     RECT  4.32 88.889 9.306 89.159 ;
     RECT  86.115 87.647 86.397 89.167 ;
     RECT  2.304 88.877 2.697 89.168 ;
     RECT  77.544 89.035 79.506 89.213 ;
     RECT  3.42 88.889 3.438 89.231 ;
     RECT  7.815 89.159 9.306 89.231 ;
     RECT  86.115 89.167 86.67 89.267 ;
     RECT  4.32 89.159 6.03 89.429 ;
     RECT  6.84 89.159 6.858 89.429 ;
     RECT  7.815 89.231 8.91 89.429 ;
     RECT  37.515 88.187 38.502 89.545 ;
     RECT  7.815 89.429 8.37 89.573 ;
     RECT  5.115 89.429 6.03 89.609 ;
     RECT  77.544 89.213 78.678 89.741 ;
     RECT  39.564 88.925 76.482 89.803 ;
     RECT  83.34 89.021 84.402 89.837 ;
     RECT  37.515 89.545 38.826 89.843 ;
     RECT  39.564 89.803 76.626 89.843 ;
     RECT  39.564 89.843 76.554 89.885 ;
     RECT  92.808 89.033 94.497 89.969 ;
     RECT  83.34 89.837 83.79 90.211 ;
     RECT  92.808 89.969 92.898 90.239 ;
     RECT  86.115 89.267 86.634 90.247 ;
     RECT  90.648 87.575 90.666 90.275 ;
     RECT  92.808 90.239 92.826 90.311 ;
     RECT  82.62 90.211 83.79 90.331 ;
     RECT  86.115 90.247 86.67 90.391 ;
     RECT  91.515 89.033 92.034 90.391 ;
     RECT  39.564 89.885 76.41 90.461 ;
     RECT  82.08 90.331 83.79 90.509 ;
     RECT  91.515 90.391 92.214 90.545 ;
     RECT  77.544 89.741 78.354 90.557 ;
     RECT  86.115 90.391 86.706 90.581 ;
     RECT  82.656 90.509 83.79 90.653 ;
     RECT  77.904 90.557 78.354 90.763 ;
     RECT  91.515 90.545 91.89 90.815 ;
     RECT  77.904 90.763 78.678 90.893 ;
     RECT  82.656 90.653 83.697 90.893 ;
     RECT  86.115 90.581 86.634 90.923 ;
     RECT  39.564 90.461 76.374 91.613 ;
     RECT  77.904 90.893 78.297 91.675 ;
     RECT  39.564 91.613 75.546 91.805 ;
     RECT  76.32 91.613 76.374 92.011 ;
     RECT  77.472 91.675 78.297 92.011 ;
     RECT  76.32 92.011 78.297 92.093 ;
     RECT  76.356 92.093 78.297 92.189 ;
     RECT  37.515 89.843 38.502 92.245 ;
     RECT  39.564 91.805 75.51 92.245 ;
     RECT  76.356 92.189 76.41 92.381 ;
     RECT  77.58 92.189 78.297 92.861 ;
     RECT  21.315 82.157 21.597 93.091 ;
     RECT  22.824 93.067 22.842 93.119 ;
     RECT  83.34 90.893 83.697 93.361 ;
     RECT  83.34 93.361 83.97 93.479 ;
     RECT  21.315 93.091 22.086 93.485 ;
     RECT  86.115 90.923 86.397 93.487 ;
     RECT  91.515 90.815 91.797 93.487 ;
     RECT  37.515 92.245 75.51 93.623 ;
     RECT  86.115 93.487 86.634 93.623 ;
     RECT  79.488 89.213 79.506 93.631 ;
     RECT  80.64 88.493 80.997 93.631 ;
     RECT  79.488 93.631 80.997 93.749 ;
     RECT  90.432 93.523 90.45 93.829 ;
     RECT  77.616 92.861 78.297 93.865 ;
     RECT  76.392 92.381 76.41 93.901 ;
     RECT  77.544 93.865 78.297 93.901 ;
     RECT  83.34 93.479 83.754 93.901 ;
     RECT  80.64 93.749 80.997 94.019 ;
     RECT  83.088 93.901 83.754 94.019 ;
     RECT  38.628 93.623 75.51 94.027 ;
     RECT  76.356 93.901 76.41 94.027 ;
     RECT  90.36 93.829 90.45 94.027 ;
     RECT  77.472 93.901 78.297 94.055 ;
     RECT  38.628 94.027 76.41 94.205 ;
     RECT  43.092 94.205 76.41 94.685 ;
     RECT  38.628 94.205 42.354 94.981 ;
     RECT  43.092 94.685 75.192 94.981 ;
     RECT  77.616 94.055 78.297 95.611 ;
     RECT  38.628 94.981 75.192 95.639 ;
     RECT  76.392 94.685 76.41 95.899 ;
     RECT  79.488 93.749 79.506 96.053 ;
     RECT  91.476 93.487 91.797 96.061 ;
     RECT  93.24 96.025 93.258 96.061 ;
     RECT  94.215 89.969 94.497 96.061 ;
     RECT  93.24 96.061 94.497 96.181 ;
     RECT  77.58 95.611 78.297 96.187 ;
     RECT  91.476 96.061 92.178 96.223 ;
     RECT  93.06 96.181 94.497 96.223 ;
     RECT  77.436 96.187 78.297 96.475 ;
     RECT  95.76 96.259 95.778 96.529 ;
     RECT  76.392 95.899 76.446 96.667 ;
     RECT  77.4 96.475 78.297 96.667 ;
     RECT  76.392 96.667 78.297 96.755 ;
     RECT  39.708 95.639 75.192 96.859 ;
     RECT  90.36 94.027 90.738 96.871 ;
     RECT  91.476 96.223 94.497 96.871 ;
     RECT  95.76 96.529 95.814 96.871 ;
     RECT  39.708 96.859 75.33 96.955 ;
     RECT  95.22 96.871 95.814 96.989 ;
     RECT  90.36 96.871 94.497 97.033 ;
     RECT  96.912 96.763 96.93 97.033 ;
     RECT  39.708 96.955 75.474 97.069 ;
     RECT  96.912 97.033 97.506 97.085 ;
     RECT  95.76 96.989 95.814 97.097 ;
     RECT  86.115 93.623 86.397 97.231 ;
     RECT  96.912 97.085 96.966 97.331 ;
     RECT  96.912 97.331 96.93 97.339 ;
     RECT  90.36 97.033 94.734 97.411 ;
     RECT  96.3 97.339 96.93 97.601 ;
     RECT  39.708 97.069 75.582 97.609 ;
     RECT  90.288 97.411 94.734 97.645 ;
     RECT  96.912 97.601 96.93 97.871 ;
     RECT  90.072 97.645 94.734 98.041 ;
     RECT  95.76 97.915 95.922 98.041 ;
     RECT  76.644 96.755 78.297 98.149 ;
     RECT  88.815 85.919 89.097 98.185 ;
     RECT  90.072 98.041 95.922 98.185 ;
     RECT  39.708 97.609 75.726 98.383 ;
     RECT  76.644 98.149 78.93 98.383 ;
     RECT  88.815 98.185 95.922 98.411 ;
     RECT  86.115 97.231 86.67 98.419 ;
     RECT  95.904 98.411 95.922 98.491 ;
     RECT  86.115 98.419 86.706 98.519 ;
     RECT  39.708 98.383 78.93 98.581 ;
     RECT  95.904 98.491 96.354 98.923 ;
     RECT  97.488 98.221 97.506 98.923 ;
     RECT  95.904 98.923 97.506 99.031 ;
     RECT  98.244 99.019 98.262 99.031 ;
     RECT  95.904 99.031 98.262 99.059 ;
     RECT  95.904 99.059 98.19 99.101 ;
     RECT  95.904 99.101 97.542 99.157 ;
     RECT  88.815 98.411 94.914 99.197 ;
     RECT  95.76 99.157 97.542 99.245 ;
     RECT  39.636 98.581 78.93 99.455 ;
     RECT  96.3 99.245 97.542 99.533 ;
     RECT  21.315 93.485 21.597 99.739 ;
     RECT  21.315 99.739 22.23 99.959 ;
     RECT  86.115 98.519 86.397 100.003 ;
     RECT  88.815 99.197 89.154 100.003 ;
     RECT  90.072 99.197 94.914 100.003 ;
     RECT  21.315 99.959 21.906 100.013 ;
     RECT  83.415 94.019 83.754 100.031 ;
     RECT  96.3 99.533 96.354 100.067 ;
     RECT  87.696 100.003 87.714 100.075 ;
     RECT  87.624 100.075 87.714 100.111 ;
     RECT  82.332 94.027 82.35 100.201 ;
     RECT  82.332 100.201 82.674 100.229 ;
     RECT  85.608 100.003 86.397 100.229 ;
     RECT  97.488 99.533 97.542 100.253 ;
     RECT  87.516 100.111 87.714 100.265 ;
     RECT  82.656 100.229 82.674 100.301 ;
     RECT  96.336 100.067 96.354 100.397 ;
     RECT  38.628 95.639 38.646 100.459 ;
     RECT  88.815 100.003 94.914 100.535 ;
     RECT  37.515 93.623 37.797 100.651 ;
     RECT  38.628 100.459 38.754 100.651 ;
     RECT  37.515 100.651 38.754 100.769 ;
     RECT  87.732 100.471 87.75 100.769 ;
     RECT  97.488 100.253 97.506 100.777 ;
     RECT  96.912 100.777 97.506 100.829 ;
     RECT  89.928 100.535 94.914 100.841 ;
     RECT  97.488 100.829 97.506 100.841 ;
     RECT  37.515 100.769 38.646 100.877 ;
     RECT  90 100.841 94.914 100.877 ;
     RECT  90.072 100.877 94.914 101.039 ;
     RECT  39.636 99.455 77.238 103.235 ;
     RECT  39.636 103.235 76.158 103.704 ;
     RECT  91.116 101.039 94.914 103.811 ;
     RECT  90.072 101.039 90.342 103.883 ;
     RECT  75.24 103.704 76.158 103.919 ;
     RECT  39.636 103.704 43.146 104.161 ;
     RECT  39.456 104.161 43.146 104.237 ;
     RECT  77.22 103.235 77.238 104.333 ;
     RECT  91.116 103.811 94.842 104.423 ;
     RECT  91.116 104.423 92.862 104.459 ;
     RECT  91.116 104.459 91.797 104.549 ;
     RECT  75.24 103.919 76.122 104.585 ;
     RECT  92.844 104.459 92.862 104.927 ;
     RECT  39.636 104.237 43.146 105.269 ;
     RECT  49.86 105.169 49.878 105.637 ;
     RECT  93.744 104.423 94.842 105.665 ;
     RECT  78.015 99.455 78.93 105.737 ;
     RECT  90.324 103.883 90.342 105.773 ;
     RECT  47.016 105.745 47.034 105.781 ;
     RECT  51.156 105.133 51.174 105.781 ;
     RECT  94.215 105.665 94.842 105.809 ;
     RECT  47.016 105.781 47.106 105.899 ;
     RECT  49.284 105.637 49.878 105.899 ;
     RECT  50.976 105.781 51.174 105.899 ;
     RECT  64.515 105.823 64.605 105.931 ;
     RECT  75.24 104.585 75.474 105.935 ;
     RECT  65.556 105.835 65.574 106.079 ;
     RECT  39.888 105.269 43.146 106.093 ;
     RECT  45.615 105.823 45.705 106.093 ;
     RECT  48.315 105.823 48.405 106.093 ;
     RECT  51.015 105.899 51.174 106.093 ;
     RECT  53.715 105.823 53.805 106.093 ;
     RECT  56.415 105.823 56.505 106.093 ;
     RECT  59.115 105.823 59.205 106.093 ;
     RECT  61.815 105.823 61.905 106.093 ;
     RECT  64.515 105.931 64.674 106.093 ;
     RECT  67.215 105.823 67.305 106.093 ;
     RECT  69.915 105.823 70.005 106.093 ;
     RECT  72.615 105.823 72.705 106.093 ;
     RECT  75.315 105.935 75.474 106.093 ;
     RECT  39.888 106.093 43.197 107.179 ;
     RECT  39.888 107.179 43.506 107.401 ;
     RECT  39.888 107.401 43.578 108.239 ;
     RECT  39.888 108.239 43.542 108.515 ;
     RECT  61.815 106.093 62.097 110.347 ;
     RECT  64.515 106.093 64.797 110.347 ;
     RECT  61.815 110.347 62.73 110.525 ;
     RECT  64.515 110.347 64.998 110.621 ;
     RECT  39.888 108.515 43.197 113.459 ;
     RECT  39.888 113.459 40.59 113.999 ;
     RECT  41.58 113.459 43.197 114.523 ;
     RECT  41.436 114.523 43.197 114.575 ;
     RECT  35.928 117.211 35.946 117.319 ;
     RECT  35.928 117.319 36.558 117.355 ;
     RECT  35.82 117.355 36.558 117.391 ;
     RECT  37.515 100.877 37.797 117.391 ;
     RECT  38.628 100.877 38.646 117.391 ;
     RECT  35.82 117.391 38.646 117.931 ;
     RECT  5.115 89.609 5.397 118.021 ;
     RECT  7.815 89.573 8.097 118.021 ;
     RECT  35.82 117.931 38.682 118.121 ;
     RECT  5.04 118.021 5.397 118.129 ;
     RECT  6.84 118.021 6.858 118.129 ;
     RECT  34.815 86.603 35.097 118.129 ;
     RECT  38.628 118.121 38.682 118.129 ;
     RECT  4.68 118.129 5.397 118.165 ;
     RECT  6.768 118.129 7.038 118.165 ;
     RECT  7.776 118.021 8.097 118.165 ;
     RECT  4.68 118.165 5.49 118.201 ;
     RECT  0.108 118.075 0.126 118.219 ;
     RECT  6.768 118.165 8.097 118.229 ;
     RECT  3.744 118.201 3.762 118.291 ;
     RECT  4.68 118.201 5.634 118.291 ;
     RECT  6.84 118.229 8.097 118.319 ;
     RECT  38.628 118.129 38.754 118.319 ;
     RECT  6.84 118.319 7.038 118.427 ;
     RECT  3.744 118.291 5.634 118.435 ;
     RECT  2.415 89.168 2.697 118.459 ;
     RECT  34.776 118.129 35.097 118.499 ;
     RECT  7.815 118.319 8.097 118.561 ;
     RECT  9.144 118.291 9.162 118.561 ;
     RECT  34.815 118.499 35.097 118.561 ;
     RECT  35.82 118.121 37.89 118.561 ;
     RECT  7.815 118.561 9.162 118.589 ;
     RECT  2.415 118.459 2.79 118.597 ;
     RECT  3.744 118.435 5.85 118.597 ;
     RECT  10.515 88.259 10.797 118.669 ;
     RECT  0.108 118.219 0.162 118.699 ;
     RECT  10.515 118.669 10.854 118.741 ;
     RECT  0.108 118.699 0.198 118.829 ;
     RECT  10.515 118.741 10.926 118.859 ;
     RECT  39.888 113.999 40.497 118.903 ;
     RECT  34.815 118.561 37.89 118.939 ;
     RECT  38.628 118.319 38.646 118.939 ;
     RECT  39.888 118.903 40.554 118.975 ;
     RECT  41.58 114.575 43.197 118.975 ;
     RECT  39.888 118.975 43.197 119.021 ;
     RECT  6.84 118.427 6.858 119.101 ;
     RECT  6.804 119.101 6.858 119.245 ;
     RECT  13.215 82.157 13.497 119.371 ;
     RECT  21.315 100.013 21.597 119.371 ;
     RECT  24.015 2.413 24.297 119.371 ;
     RECT  22.608 119.131 22.626 119.399 ;
     RECT  2.415 118.597 5.85 119.407 ;
     RECT  6.588 119.245 6.858 119.407 ;
     RECT  13.104 119.371 13.497 119.408 ;
     RECT  21.204 119.371 21.597 119.408 ;
     RECT  2.415 119.407 6.858 119.479 ;
     RECT  14.832 119.371 14.85 119.501 ;
     RECT  30.78 119.371 30.798 119.501 ;
     RECT  23.904 119.371 24.297 119.507 ;
     RECT  2.268 119.479 6.858 119.515 ;
     RECT  7.815 118.589 8.982 119.515 ;
     RECT  34.815 118.939 38.646 119.641 ;
     RECT  2.268 119.515 9.018 119.669 ;
     RECT  2.268 119.669 8.982 119.705 ;
     RECT  34.815 119.641 39.114 119.713 ;
     RECT  34.776 119.713 39.114 119.749 ;
     RECT  34.776 119.749 39.15 119.785 ;
     RECT  39.888 119.021 40.554 119.785 ;
     RECT  3.888 119.705 8.982 119.789 ;
     RECT  2.268 119.705 2.898 119.837 ;
     RECT  34.776 119.785 40.554 120.091 ;
     RECT  41.292 119.021 43.197 120.091 ;
     RECT  34.776 120.091 43.197 120.119 ;
     RECT  0.108 118.829 0.162 120.209 ;
     RECT  2.415 119.837 2.898 120.451 ;
     RECT  3.888 119.789 4.266 120.451 ;
     RECT  0.144 120.209 0.162 120.509 ;
     RECT  5.115 119.789 8.982 120.509 ;
     RECT  2.415 120.451 4.266 120.595 ;
     RECT  5.115 120.509 5.886 120.595 ;
     RECT  6.696 120.509 8.982 120.631 ;
     RECT  6.696 120.631 9.09 120.749 ;
     RECT  30.78 120.631 30.798 120.749 ;
     RECT  34.815 120.119 43.197 120.901 ;
     RECT  0.108 120.955 0.126 121.243 ;
     RECT  0.108 121.243 0.162 121.373 ;
     RECT  6.696 120.749 8.586 121.469 ;
     RECT  6.768 121.469 8.586 121.531 ;
     RECT  34.815 120.901 43.254 121.531 ;
     RECT  32.115 2.413 32.397 121.603 ;
     RECT  6.768 121.531 9.126 121.829 ;
     RECT  2.415 120.595 5.886 121.865 ;
     RECT  2.415 121.865 2.697 121.963 ;
     RECT  3.42 121.865 5.886 121.981 ;
     RECT  34.776 121.531 43.254 121.981 ;
     RECT  6.804 121.829 9.126 122.099 ;
     RECT  30.78 121.981 30.798 122.099 ;
     RECT  2.304 121.963 2.697 122.251 ;
     RECT  7.02 122.099 9.126 122.251 ;
     RECT  7.02 122.251 9.162 122.369 ;
     RECT  34.704 121.981 43.254 122.405 ;
     RECT  2.232 122.251 2.697 122.441 ;
     RECT  32.115 121.603 33.102 122.477 ;
     RECT  3.42 121.981 5.994 122.521 ;
     RECT  7.02 122.369 8.586 122.549 ;
     RECT  3.42 122.521 6.03 122.639 ;
     RECT  0.108 121.373 0.126 122.717 ;
     RECT  4.392 122.639 6.03 122.989 ;
     RECT  3.42 122.639 3.618 123.089 ;
     RECT  30.852 122.989 30.87 123.089 ;
     RECT  3.6 123.089 3.618 123.287 ;
     RECT  4.392 122.989 6.102 123.359 ;
     RECT  5.115 123.359 6.102 123.629 ;
     RECT  7.092 122.549 8.478 123.691 ;
     RECT  7.092 123.691 9.162 123.719 ;
     RECT  34.815 122.405 43.254 123.727 ;
     RECT  75.315 106.093 75.597 124.105 ;
     RECT  7.164 123.719 9.162 124.133 ;
     RECT  7.164 124.133 8.097 124.169 ;
     RECT  74.916 124.105 75.597 124.259 ;
     RECT  9.144 124.133 9.162 124.403 ;
     RECT  75.096 124.259 75.597 124.403 ;
     RECT  6.264 123.691 6.282 124.439 ;
     RECT  73.944 124.375 73.962 124.795 ;
     RECT  94.215 105.809 94.497 124.807 ;
     RECT  34.704 123.727 43.254 124.871 ;
     RECT  94.215 124.807 95.13 125.041 ;
     RECT  94.215 125.041 95.814 125.131 ;
     RECT  73.944 124.795 74.358 125.185 ;
     RECT  75.168 124.403 75.597 125.185 ;
     RECT  94.215 125.131 95.922 125.221 ;
     RECT  72.615 106.093 72.897 125.347 ;
     RECT  73.944 125.185 75.597 125.347 ;
     RECT  94.215 125.221 96.354 125.453 ;
     RECT  91.515 104.549 91.797 125.455 ;
     RECT  7.815 124.169 8.097 125.491 ;
     RECT  91.476 125.455 91.797 125.491 ;
     RECT  94.215 125.453 95.922 125.491 ;
     RECT  91.476 125.491 92.43 125.581 ;
     RECT  72.615 125.347 75.597 125.689 ;
     RECT  86.115 100.229 86.397 125.689 ;
     RECT  90.504 125.617 90.522 125.689 ;
     RECT  78.015 105.737 78.297 125.761 ;
     RECT  86.115 125.689 86.67 125.761 ;
     RECT  88.815 100.535 89.097 125.761 ;
     RECT  91.476 125.581 93.042 125.761 ;
     RECT  7.815 125.491 8.586 125.837 ;
     RECT  78.015 125.761 78.642 125.879 ;
     RECT  85.428 125.761 86.67 125.879 ;
     RECT  88.815 125.761 89.586 125.887 ;
     RECT  86.004 125.879 86.67 125.915 ;
     RECT  34.815 124.871 43.254 125.995 ;
     RECT  91.44 125.761 93.042 126.031 ;
     RECT  94.068 125.491 95.922 126.031 ;
     RECT  88.815 125.887 89.658 126.059 ;
     RECT  34.56 125.995 43.254 126.149 ;
     RECT  91.44 126.031 95.922 126.149 ;
     RECT  90.432 125.689 90.522 126.193 ;
     RECT  91.512 126.149 95.922 126.227 ;
     RECT  72.615 125.689 75.762 126.229 ;
     RECT  90.432 126.193 90.702 126.229 ;
     RECT  72.615 126.229 76.122 126.265 ;
     RECT  77.112 125.221 77.13 126.265 ;
     RECT  97.488 125.149 97.506 126.283 ;
     RECT  82.656 126.193 82.674 126.293 ;
     RECT  90.324 126.229 90.702 126.293 ;
     RECT  83.415 100.031 83.697 126.301 ;
     RECT  91.515 126.227 95.922 126.301 ;
     RECT  82.98 126.301 83.697 126.419 ;
     RECT  86.004 125.915 86.397 126.419 ;
     RECT  83.232 126.419 83.697 126.455 ;
     RECT  90.324 126.293 90.558 126.455 ;
     RECT  72.615 126.265 77.13 126.571 ;
     RECT  78.015 125.879 78.297 126.571 ;
     RECT  91.515 126.301 95.994 126.715 ;
     RECT  34.704 126.149 43.254 126.725 ;
     RECT  72.615 126.571 78.297 126.725 ;
     RECT  34.776 126.725 43.254 126.761 ;
     RECT  91.515 126.715 96.318 126.761 ;
     RECT  86.115 126.419 86.397 126.769 ;
     RECT  88.815 126.059 89.514 126.841 ;
     RECT  72.615 126.725 73.818 126.959 ;
     RECT  85.14 126.571 85.158 126.959 ;
     RECT  88.815 126.841 89.586 126.959 ;
     RECT  80.715 94.019 80.997 126.967 ;
     RECT  74.592 126.725 78.297 127.111 ;
     RECT  45.615 106.093 45.897 127.187 ;
     RECT  48.315 106.093 48.597 127.187 ;
     RECT  51.015 106.093 51.297 127.187 ;
     RECT  53.715 106.093 53.997 127.187 ;
     RECT  56.415 106.093 56.697 127.187 ;
     RECT  59.115 106.093 59.397 127.187 ;
     RECT  61.815 110.525 62.097 127.187 ;
     RECT  64.515 110.621 64.797 127.187 ;
     RECT  67.215 106.093 67.497 127.187 ;
     RECT  69.915 106.093 70.197 127.187 ;
     RECT  72.615 126.959 72.897 127.187 ;
     RECT  90.324 126.455 90.522 127.201 ;
     RECT  80.715 126.967 81.522 127.228 ;
     RECT  74.592 127.111 78.75 127.229 ;
     RECT  73.8 126.959 73.818 127.265 ;
     RECT  74.664 127.229 78.75 127.265 ;
     RECT  97.488 126.283 98.19 127.291 ;
     RECT  74.7 127.265 78.75 127.337 ;
     RECT  90.288 127.201 90.666 127.345 ;
     RECT  91.515 126.761 95.922 127.345 ;
     RECT  84.996 127.237 85.086 127.381 ;
     RECT  86.115 126.769 86.67 127.381 ;
     RECT  80.715 127.228 81.558 127.409 ;
     RECT  45.615 127.187 45.705 127.457 ;
     RECT  48.315 127.187 48.405 127.457 ;
     RECT  51.015 127.187 51.105 127.457 ;
     RECT  53.715 127.187 53.805 127.457 ;
     RECT  56.415 127.187 56.505 127.457 ;
     RECT  59.115 127.187 59.205 127.457 ;
     RECT  61.815 127.187 61.905 127.457 ;
     RECT  64.515 127.187 64.605 127.457 ;
     RECT  67.215 127.187 67.305 127.457 ;
     RECT  69.915 127.187 70.005 127.457 ;
     RECT  72.615 127.187 72.705 127.457 ;
     RECT  74.736 127.337 78.75 127.499 ;
     RECT  84.852 127.381 85.086 127.499 ;
     RECT  86.115 127.381 86.706 127.499 ;
     RECT  84.852 127.499 84.87 127.535 ;
     RECT  90.288 127.345 95.922 127.535 ;
     RECT  90.324 127.535 95.922 127.565 ;
     RECT  86.115 127.499 86.562 127.607 ;
     RECT  88.815 126.959 89.37 127.661 ;
     RECT  5.115 123.629 5.397 127.675 ;
     RECT  34.815 126.761 43.254 127.679 ;
     RECT  96.912 127.291 98.19 127.841 ;
     RECT  96.912 127.841 97.542 127.877 ;
     RECT  96.948 127.877 97.542 127.949 ;
     RECT  7.056 127.963 7.074 128.039 ;
     RECT  94.176 127.565 95.922 128.048 ;
     RECT  90.324 127.565 93.402 128.075 ;
     RECT  34.815 127.679 43.182 128.149 ;
     RECT  34.812 128.149 43.182 128.189 ;
     RECT  94.176 128.048 95.778 128.309 ;
     RECT  86.115 127.607 86.397 128.425 ;
     RECT  91.26 128.075 93.402 128.425 ;
     RECT  94.176 128.309 94.698 128.425 ;
     RECT  91.26 128.425 94.698 128.453 ;
     RECT  96.948 127.949 97.506 128.489 ;
     RECT  83.415 126.455 83.697 128.551 ;
     RECT  87.48 128.281 87.498 128.579 ;
     RECT  95.76 128.309 95.778 128.579 ;
     RECT  90.324 128.075 90.522 128.587 ;
     RECT  85.464 128.425 86.397 128.615 ;
     RECT  90.072 128.587 90.522 128.615 ;
     RECT  91.515 128.453 94.698 128.651 ;
     RECT  96.948 128.489 96.966 128.651 ;
     RECT  82.656 128.587 82.674 128.687 ;
     RECT  85.572 128.615 86.397 128.687 ;
     RECT  90.072 128.615 90.378 128.723 ;
     RECT  2.415 122.441 2.697 128.731 ;
     RECT  3.528 128.731 3.546 128.821 ;
     RECT  7.815 125.837 8.097 128.821 ;
     RECT  2.304 128.731 2.697 128.827 ;
     RECT  3.528 128.821 4.086 128.827 ;
     RECT  91.515 128.651 94.662 128.921 ;
     RECT  90.324 128.723 90.378 128.957 ;
     RECT  5.115 127.675 5.562 128.965 ;
     RECT  2.304 128.827 4.086 129.001 ;
     RECT  7.452 128.821 8.694 129.115 ;
     RECT  5.115 128.965 6.174 129.119 ;
     RECT  6.948 129.115 8.694 129.155 ;
     RECT  2.304 129.001 4.374 129.235 ;
     RECT  5.115 129.119 5.85 129.235 ;
     RECT  90.36 128.957 90.378 129.361 ;
     RECT  91.515 128.921 94.497 129.361 ;
     RECT  90.36 129.361 94.497 129.461 ;
     RECT  2.304 129.235 5.85 129.485 ;
     RECT  7.164 129.155 8.694 129.505 ;
     RECT  34.815 128.189 43.182 129.6 ;
     RECT  74.736 127.499 78.297 129.6 ;
     RECT  90.36 129.461 92.898 129.695 ;
     RECT  4.428 129.485 5.85 129.929 ;
     RECT  7.164 129.505 8.946 129.929 ;
     RECT  34.815 129.6 78.297 129.931 ;
     RECT  2.304 129.485 3.654 130.208 ;
     RECT  34.38 129.931 78.297 130.235 ;
     RECT  7.164 129.929 8.406 130.243 ;
     RECT  6.84 130.243 8.406 130.351 ;
     RECT  34.776 130.235 78.297 130.459 ;
     RECT  6.696 130.351 8.406 130.513 ;
     RECT  86.115 128.687 86.397 130.513 ;
     RECT  0.108 129.307 0.126 130.541 ;
     RECT  2.415 130.208 3.654 130.541 ;
     RECT  6.516 130.513 8.406 130.541 ;
     RECT  3.492 130.541 3.654 130.549 ;
     RECT  4.428 129.929 5.742 130.549 ;
     RECT  85.752 130.513 86.397 130.711 ;
     RECT  90.36 129.695 92.862 130.711 ;
     RECT  93.96 129.461 94.497 130.711 ;
     RECT  3.492 130.549 5.742 130.855 ;
     RECT  6.516 130.541 8.37 130.855 ;
     RECT  34.776 130.459 78.678 130.883 ;
     RECT  0.324 130.603 0.342 130.891 ;
     RECT  9.648 130.513 9.666 130.981 ;
     RECT  82.656 130.747 82.674 130.981 ;
     RECT  34.815 130.883 78.678 130.987 ;
     RECT  79.488 130.315 79.506 130.987 ;
     RECT  0.324 130.891 0.666 131.069 ;
     RECT  82.116 130.981 82.674 131.083 ;
     RECT  34.815 130.987 79.506 131.117 ;
     RECT  83.415 128.551 83.79 131.165 ;
     RECT  2.415 130.541 2.697 131.179 ;
     RECT  82.08 131.083 82.674 131.189 ;
     RECT  2.16 131.179 2.697 131.275 ;
     RECT  3.492 130.855 8.37 131.275 ;
     RECT  34.815 131.117 78.678 131.279 ;
     RECT  90.36 130.711 94.497 131.279 ;
     RECT  82.116 131.189 82.674 131.309 ;
     RECT  9.108 130.981 9.666 131.315 ;
     RECT  34.815 131.279 78.498 131.357 ;
     RECT  83.415 131.165 83.754 131.405 ;
     RECT  2.16 131.275 8.37 131.431 ;
     RECT  9.648 131.315 9.666 131.459 ;
     RECT  2.16 131.431 8.478 131.549 ;
     RECT  0.144 131.467 0.162 131.597 ;
     RECT  2.16 131.549 6.246 131.621 ;
     RECT  82.656 131.309 82.674 131.657 ;
     RECT  34.815 131.357 78.297 131.701 ;
     RECT  90.36 131.279 92.682 131.819 ;
     RECT  85.752 130.711 86.454 131.827 ;
     RECT  0.108 131.755 0.126 131.885 ;
     RECT  85.752 131.827 86.67 131.927 ;
     RECT  84.636 129.541 84.654 131.933 ;
     RECT  34.776 131.701 78.297 131.935 ;
     RECT  83.415 131.405 83.697 131.947 ;
     RECT  2.304 131.621 6.246 131.999 ;
     RECT  6.984 131.549 7.074 131.999 ;
     RECT  30.78 131.971 30.798 132.089 ;
     RECT  34.704 131.935 78.297 132.235 ;
     RECT  2.415 131.999 6.246 132.269 ;
     RECT  90.36 131.819 92.646 132.395 ;
     RECT  83.124 131.947 83.697 132.461 ;
     RECT  34.704 132.235 78.678 132.475 ;
     RECT  34.704 132.475 78.75 132.511 ;
     RECT  83.232 132.461 83.697 132.539 ;
     RECT  93.456 131.279 94.497 132.629 ;
     RECT  91.116 132.395 92.646 132.665 ;
     RECT  34.2 132.511 78.75 132.667 ;
     RECT  79.488 131.117 79.506 132.667 ;
     RECT  83.268 132.539 83.697 132.701 ;
     RECT  34.2 132.667 79.506 132.797 ;
     RECT  85.752 131.927 86.634 132.907 ;
     RECT  83.415 132.701 83.697 133.003 ;
     RECT  4.68 132.269 6.246 133.007 ;
     RECT  85.752 132.907 86.67 133.043 ;
     RECT  83.415 133.003 84.186 133.079 ;
     RECT  7.056 131.999 7.074 133.241 ;
     RECT  4.68 133.007 5.778 133.349 ;
     RECT  34.2 132.797 78.678 133.709 ;
     RECT  7.815 131.549 8.478 133.817 ;
     RECT  34.2 133.709 78.606 134.045 ;
     RECT  2.415 132.269 3.726 134.159 ;
     RECT  2.415 134.159 3.222 134.285 ;
     RECT  34.2 134.045 76.086 134.825 ;
     RECT  90.36 132.395 90.378 134.827 ;
     RECT  89.928 134.827 90.378 134.867 ;
     RECT  5.115 133.349 5.778 134.933 ;
     RECT  34.2 134.825 35.097 134.969 ;
     RECT  36 134.825 76.086 135.005 ;
     RECT  76.968 134.045 78.606 135.059 ;
     RECT  76.968 135.059 78.297 135.101 ;
     RECT  89.964 134.867 90.378 135.101 ;
     RECT  42.768 135.005 76.086 135.355 ;
     RECT  36 135.005 41.922 135.869 ;
     RECT  34.815 134.969 35.097 136.021 ;
     RECT  34.815 136.021 35.658 136.061 ;
     RECT  36.576 135.869 41.922 136.061 ;
     RECT  36.576 136.061 41.31 136.175 ;
     RECT  85.752 133.043 86.454 136.679 ;
     RECT  88.815 127.661 89.097 136.759 ;
     RECT  90.36 135.101 90.378 136.759 ;
     RECT  36.936 136.175 41.31 136.781 ;
     RECT  42.768 135.355 76.41 137.065 ;
     RECT  42.768 137.065 76.446 137.101 ;
     RECT  42.732 137.101 76.446 137.213 ;
     RECT  86.115 136.679 86.454 137.219 ;
     RECT  91.515 132.665 92.646 137.335 ;
     RECT  37.188 136.781 41.31 137.467 ;
     RECT  42.732 137.213 76.41 137.501 ;
     RECT  37.188 137.467 41.706 137.561 ;
     RECT  91.515 137.335 92.79 137.605 ;
     RECT  42.732 137.501 75.192 137.641 ;
     RECT  37.188 137.561 41.31 137.645 ;
     RECT  37.515 137.645 41.31 138.427 ;
     RECT  42.156 137.641 75.192 138.427 ;
     RECT  77.256 135.101 78.297 138.713 ;
     RECT  91.515 137.605 93.042 138.811 ;
     RECT  93.96 132.629 94.497 138.811 ;
     RECT  88.815 136.759 90.378 138.839 ;
     RECT  91.515 138.811 94.497 138.847 ;
     RECT  95.364 138.721 95.382 138.847 ;
     RECT  76.068 137.501 76.41 138.875 ;
     RECT  91.515 138.847 95.778 138.991 ;
     RECT  96.912 138.955 96.93 138.991 ;
     RECT  91.515 138.991 96.93 139.181 ;
     RECT  37.515 138.427 75.192 139.225 ;
     RECT  86.115 137.219 86.397 139.261 ;
     RECT  37.404 139.225 75.192 139.291 ;
     RECT  76.068 138.875 76.374 139.291 ;
     RECT  37.404 139.291 76.374 139.421 ;
     RECT  77.472 138.713 78.297 139.483 ;
     RECT  97.488 139.243 97.506 139.487 ;
     RECT  90.756 139.351 90.774 139.531 ;
     RECT  91.515 139.181 96.39 139.531 ;
     RECT  77.436 139.483 78.297 139.675 ;
     RECT  37.515 139.421 76.374 139.771 ;
     RECT  77.4 139.675 78.297 139.771 ;
     RECT  90.756 139.531 96.39 139.829 ;
     RECT  90.756 139.829 95.814 139.919 ;
     RECT  86.115 139.261 86.67 139.999 ;
     RECT  88.815 138.839 89.982 140.035 ;
     RECT  90.756 139.919 95.346 140.035 ;
     RECT  86.115 139.999 86.706 140.099 ;
     RECT  88.815 140.035 95.346 140.459 ;
     RECT  96.912 140.251 96.93 140.495 ;
     RECT  90.972 140.459 95.346 140.683 ;
     RECT  86.115 140.099 86.67 140.729 ;
     RECT  88.815 140.459 89.982 140.729 ;
     RECT  90.972 140.683 95.814 140.827 ;
     RECT  97.488 140.539 97.506 140.881 ;
     RECT  90.972 140.827 95.922 141.421 ;
     RECT  90.648 141.421 95.922 141.547 ;
     RECT  86.115 140.729 86.397 141.655 ;
     RECT  90.648 141.547 96.318 141.809 ;
     RECT  86.115 141.655 86.67 141.917 ;
     RECT  83.415 133.079 83.697 141.961 ;
     RECT  88.815 140.729 89.766 141.961 ;
     RECT  90.648 141.809 95.346 141.961 ;
     RECT  96.3 141.809 96.318 141.979 ;
     RECT  97.488 140.881 97.542 141.979 ;
     RECT  79.488 132.797 79.506 141.989 ;
     RECT  96.3 141.979 97.542 141.989 ;
     RECT  82.836 141.961 83.697 142.079 ;
     RECT  96.3 141.989 97.506 142.187 ;
     RECT  86.115 141.917 86.634 142.259 ;
     RECT  37.515 139.771 78.297 142.349 ;
     RECT  37.515 142.349 76.662 142.501 ;
     RECT  37.296 142.501 76.662 142.507 ;
     RECT  36.9 142.507 76.662 142.619 ;
     RECT  87.804 142.087 87.822 142.619 ;
     RECT  37.296 142.619 76.662 142.637 ;
     RECT  96.912 142.187 97.506 142.771 ;
     RECT  77.616 142.349 78.297 142.861 ;
     RECT  88.815 141.961 95.346 142.897 ;
     RECT  77.616 142.861 78.678 142.961 ;
     RECT  96.912 142.771 97.542 143.021 ;
     RECT  88.344 142.897 95.346 143.069 ;
     RECT  88.344 143.069 89.982 143.159 ;
     RECT  96.912 143.021 97.506 143.231 ;
     RECT  90.9 143.069 95.346 143.275 ;
     RECT  88.344 143.159 89.097 143.429 ;
     RECT  90.9 143.275 95.814 143.429 ;
     RECT  90.9 143.429 95.346 143.699 ;
     RECT  97.488 143.231 97.506 143.807 ;
     RECT  77.616 142.961 78.297 146.435 ;
     RECT  37.515 142.637 76.662 146.904 ;
     RECT  90.9 143.699 92.754 146.975 ;
     RECT  93.528 143.699 95.346 147.083 ;
     RECT  70.704 146.904 70.722 147.197 ;
     RECT  37.515 146.904 43.146 147.245 ;
     RECT  93.6 147.083 95.346 147.245 ;
     RECT  74.736 146.904 76.662 147.479 ;
     RECT  74.736 147.479 76.158 147.515 ;
     RECT  94.215 147.245 95.346 147.659 ;
     RECT  37.515 147.245 41.886 147.749 ;
     RECT  95.328 147.659 95.346 147.749 ;
     RECT  37.515 147.749 41.382 147.785 ;
     RECT  90.9 146.975 92.322 147.785 ;
     RECT  37.515 147.785 41.31 147.821 ;
     RECT  90.9 147.785 91.797 147.821 ;
     RECT  76.068 147.515 76.158 147.857 ;
     RECT  37.515 147.821 40.806 147.893 ;
     RECT  77.904 146.435 78.297 147.893 ;
     RECT  89.964 143.159 89.982 148.469 ;
     RECT  42.696 147.245 43.146 148.514 ;
     RECT  50.832 148.486 50.85 148.531 ;
     RECT  42.732 148.514 43.146 148.559 ;
     RECT  50.436 148.531 50.85 148.945 ;
     RECT  76.068 147.857 76.086 148.973 ;
     RECT  47.988 148.441 48.006 148.981 ;
     RECT  74.736 147.515 75.258 149.009 ;
     RECT  47.988 148.981 48.078 149.023 ;
     RECT  50.364 148.945 50.85 149.023 ;
     RECT  75.168 149.009 75.258 149.023 ;
     RECT  47.988 149.023 48.405 149.099 ;
     RECT  50.364 149.023 51.105 149.099 ;
     RECT  75.168 149.023 75.597 149.135 ;
     RECT  54.648 148.981 54.666 149.171 ;
     RECT  42.915 148.559 43.146 149.293 ;
     RECT  45.615 149.023 45.705 149.293 ;
     RECT  48.315 149.099 48.405 149.293 ;
     RECT  51.015 149.099 51.105 149.293 ;
     RECT  53.715 149.023 53.805 149.293 ;
     RECT  56.415 149.023 56.505 149.293 ;
     RECT  59.115 149.023 59.205 149.293 ;
     RECT  61.815 149.023 61.905 149.293 ;
     RECT  64.515 149.023 64.605 149.293 ;
     RECT  67.215 149.023 67.305 149.293 ;
     RECT  69.915 149.023 70.005 149.293 ;
     RECT  72.615 149.023 72.705 149.293 ;
     RECT  75.24 149.135 75.597 149.369 ;
     RECT  37.515 147.893 40.497 164.731 ;
     RECT  37.368 164.731 40.497 165.029 ;
     RECT  37.476 165.029 40.497 165.875 ;
     RECT  37.515 165.875 40.497 167.099 ;
     RECT  37.515 167.099 39.294 167.603 ;
     RECT  37.515 167.603 39.222 167.729 ;
     RECT  37.515 167.729 39.042 167.909 ;
     RECT  2.415 134.285 2.697 168.227 ;
     RECT  5.115 134.933 5.397 168.227 ;
     RECT  7.815 133.817 8.097 168.227 ;
     RECT  10.515 118.859 10.797 168.227 ;
     RECT  13.215 119.408 13.497 168.227 ;
     RECT  15.915 2.413 16.197 168.227 ;
     RECT  18.615 2.413 18.897 168.227 ;
     RECT  21.315 119.408 21.597 168.227 ;
     RECT  24.015 119.507 24.297 168.227 ;
     RECT  26.715 2.413 26.997 168.227 ;
     RECT  29.415 2.413 29.697 168.227 ;
     RECT  32.115 122.477 32.397 168.227 ;
     RECT  34.815 136.061 35.097 168.227 ;
     RECT  40.215 167.099 40.497 168.227 ;
     RECT  42.915 149.293 43.197 168.227 ;
     RECT  45.615 149.293 45.897 168.227 ;
     RECT  48.315 149.293 48.597 168.227 ;
     RECT  51.015 149.293 51.297 168.227 ;
     RECT  53.715 149.293 53.997 168.227 ;
     RECT  56.415 149.293 56.697 168.227 ;
     RECT  59.115 149.293 59.397 168.227 ;
     RECT  61.815 149.293 62.097 168.227 ;
     RECT  64.515 149.293 64.797 168.227 ;
     RECT  67.215 149.293 67.497 168.227 ;
     RECT  69.915 149.293 70.197 168.227 ;
     RECT  72.615 149.293 72.897 168.227 ;
     RECT  75.315 149.369 75.597 168.227 ;
     RECT  78.015 147.893 78.297 168.227 ;
     RECT  80.715 127.409 80.997 168.227 ;
     RECT  83.415 142.079 83.697 168.227 ;
     RECT  86.115 142.259 86.397 168.227 ;
     RECT  88.815 143.429 89.097 168.227 ;
     RECT  91.515 147.821 91.797 168.227 ;
     RECT  94.215 147.659 94.497 168.227 ;
     RECT  2.415 168.227 2.505 168.497 ;
     RECT  5.115 168.227 5.205 168.497 ;
     RECT  7.815 168.227 7.905 168.497 ;
     RECT  10.515 168.227 10.605 168.497 ;
     RECT  13.215 168.227 13.305 168.497 ;
     RECT  15.915 168.227 16.005 168.497 ;
     RECT  18.615 168.227 18.705 168.497 ;
     RECT  21.315 168.227 21.405 168.497 ;
     RECT  24.015 168.227 24.105 168.497 ;
     RECT  26.715 168.227 26.805 168.497 ;
     RECT  29.415 168.227 29.505 168.497 ;
     RECT  32.115 168.227 32.205 168.497 ;
     RECT  34.815 168.227 34.905 168.497 ;
     RECT  37.515 167.909 39.006 168.497 ;
     RECT  40.215 168.227 40.305 168.497 ;
     RECT  42.915 168.227 43.005 168.497 ;
     RECT  45.615 168.227 45.705 168.497 ;
     RECT  48.315 168.227 48.405 168.497 ;
     RECT  51.015 168.227 51.105 168.497 ;
     RECT  53.715 168.227 53.805 168.497 ;
     RECT  56.415 168.227 56.505 168.497 ;
     RECT  59.115 168.227 59.205 168.497 ;
     RECT  61.815 168.227 61.905 168.497 ;
     RECT  64.515 168.227 64.605 168.497 ;
     RECT  67.215 168.227 67.305 168.497 ;
     RECT  69.915 168.227 70.005 168.497 ;
     RECT  72.615 168.227 72.705 168.497 ;
     RECT  75.315 168.227 75.405 168.497 ;
     RECT  78.015 168.227 78.105 168.497 ;
     RECT  80.715 168.227 80.805 168.497 ;
     RECT  83.415 168.227 83.505 168.497 ;
     RECT  86.115 168.227 86.205 168.497 ;
     RECT  88.815 168.227 88.905 168.497 ;
     RECT  91.515 168.227 91.605 168.497 ;
     RECT  94.215 168.227 94.305 168.497 ;
     RECT  38.052 168.497 39.006 170.347 ;
     RECT  37.836 170.347 39.006 170.609 ;
     RECT  37.908 170.609 39.006 170.621 ;
    LAYER M4 ;
     RECT  0.06 118.08 0.097 122.568 ;
     RECT  0.06 128.736 0.097 131.784 ;
     RECT  0.06 31.68 0.137 36.168 ;
     RECT  0.06 40.896 0.137 45.384 ;
     RECT  0.06 78.912 0.137 83.4 ;
     RECT  0.097 118.08 0.137 122.712 ;
     RECT  0.137 78.96 0.17 83.4 ;
     RECT  0.137 118.224 0.173 122.712 ;
     RECT  0.06 84.672 0.569 89.16 ;
     RECT  0.137 31.824 2.077 36.024 ;
     RECT  2.077 31.728 2.408 36.024 ;
     RECT  0.137 41.04 2.408 45.384 ;
     RECT  0.17 78.96 2.408 83.352 ;
     RECT  0.569 84.816 2.408 89.16 ;
     RECT  0.173 118.32 2.408 122.712 ;
     RECT  0.097 128.736 2.408 131.88 ;
     RECT  2.408 2.148 2.512 168.492 ;
     RECT  2.512 2.418 2.704 168.222 ;
     RECT  2.704 128.832 3.413 131.88 ;
     RECT  3.413 128.88 3.773 131.88 ;
     RECT  2.704 78.96 3.881 83.832 ;
     RECT  2.704 41.04 3.887 45.432 ;
     RECT  2.704 31.728 3.917 36.024 ;
     RECT  3.887 41.04 3.949 45.72 ;
     RECT  2.704 118.32 3.989 122.856 ;
     RECT  3.773 128.88 4.097 131.64 ;
     RECT  3.917 31.968 4.741 36.024 ;
     RECT  4.741 31.968 5.108 36.936 ;
     RECT  3.949 40.56 5.108 45.72 ;
     RECT  3.881 79.2 5.108 83.832 ;
     RECT  2.704 84.816 5.108 89.16 ;
     RECT  3.989 118.368 5.108 122.856 ;
     RECT  4.097 128.976 5.108 131.64 ;
     RECT  5.108 2.148 5.212 168.492 ;
     RECT  5.212 2.418 5.404 168.222 ;
     RECT  5.404 32.544 5.573 33.288 ;
     RECT  5.404 87.216 5.573 88.44 ;
     RECT  5.404 118.32 5.573 122.424 ;
     RECT  5.404 78.912 5.603 84.936 ;
     RECT  5.404 86.016 5.603 86.232 ;
     RECT  5.573 33.072 5.609 33.288 ;
     RECT  5.603 78.912 5.609 84.312 ;
     RECT  5.573 118.32 5.609 119.016 ;
     RECT  5.573 120.24 5.645 122.424 ;
     RECT  5.404 129.12 5.645 130.584 ;
     RECT  5.609 81.072 5.681 84.312 ;
     RECT  5.404 34.416 5.717 35.496 ;
     RECT  5.404 41.616 5.717 44.136 ;
     RECT  5.609 78.912 5.717 79.8 ;
     RECT  5.681 81.072 5.717 81.096 ;
     RECT  5.603 86.208 5.717 86.232 ;
     RECT  5.404 131.568 5.717 131.592 ;
     RECT  5.573 87.216 5.753 88.392 ;
     RECT  5.717 34.896 5.825 35.496 ;
     RECT  5.681 82.128 5.825 84.312 ;
     RECT  5.753 87.216 5.825 88.248 ;
     RECT  5.609 118.896 5.825 119.016 ;
     RECT  5.825 118.992 5.861 119.016 ;
     RECT  5.404 36.912 5.939 37.224 ;
     RECT  5.404 45.696 6.113 45.72 ;
     RECT  5.717 41.616 6.149 43.08 ;
     RECT  5.645 120.24 6.149 121.848 ;
     RECT  5.825 87.936 6.293 88.248 ;
     RECT  5.609 33.072 6.797 33.096 ;
     RECT  5.825 82.128 6.829 82.248 ;
     RECT  5.825 83.232 6.829 84.312 ;
     RECT  6.829 82.128 6.833 84.312 ;
     RECT  6.149 120.48 7.004 121.848 ;
     RECT  5.404 127.68 7.004 127.704 ;
     RECT  6.829 86.208 7.441 86.232 ;
     RECT  7.369 33.552 7.808 33.576 ;
     RECT  5.825 34.896 7.808 34.92 ;
     RECT  5.939 36.912 7.808 36.936 ;
     RECT  5.404 40.56 7.808 40.584 ;
     RECT  6.149 42.48 7.808 43.08 ;
     RECT  6.685 44.304 7.808 44.328 ;
     RECT  5.717 78.912 7.808 78.936 ;
     RECT  6.833 82.128 7.808 82.296 ;
     RECT  6.833 83.76 7.808 84.312 ;
     RECT  7.441 86.208 7.808 86.664 ;
     RECT  6.293 87.936 7.808 87.96 ;
     RECT  6.865 118.176 7.808 118.2 ;
     RECT  7.669 119.472 7.808 119.496 ;
     RECT  7.004 120.48 7.808 122.52 ;
     RECT  7.669 125.184 7.808 125.208 ;
     RECT  7.004 127.68 7.808 127.992 ;
     RECT  5.645 129.12 7.808 129.768 ;
     RECT  7.369 130.752 7.808 130.776 ;
     RECT  7.808 2.148 7.912 168.492 ;
     RECT  7.912 2.418 8.104 168.222 ;
     RECT  8.104 82.224 8.165 84.408 ;
     RECT  8.104 128.832 8.165 129.768 ;
     RECT  8.165 82.272 8.243 84.408 ;
     RECT  8.104 130.752 8.243 130.968 ;
     RECT  8.104 85.824 8.273 87.816 ;
     RECT  8.243 83.808 8.281 84.408 ;
     RECT  8.165 128.832 8.281 129.384 ;
     RECT  8.243 130.944 8.281 130.968 ;
     RECT  8.104 36.384 8.291 36.408 ;
     RECT  8.104 118.176 8.291 118.2 ;
     RECT  8.104 119.376 8.291 119.496 ;
     RECT  8.104 120.48 8.291 121.56 ;
     RECT  8.104 122.832 8.345 122.856 ;
     RECT  8.273 85.824 8.387 85.848 ;
     RECT  8.291 120.48 8.417 120.504 ;
     RECT  8.104 44.448 8.425 44.472 ;
     RECT  8.104 40.128 8.453 41.352 ;
     RECT  8.273 86.928 8.453 87.816 ;
     RECT  8.104 34.8 8.489 34.92 ;
     RECT  8.453 87.792 8.489 87.816 ;
     RECT  8.104 33.552 8.524 33.576 ;
     RECT  8.104 125.808 8.597 125.832 ;
     RECT  8.489 34.896 8.993 34.92 ;
     RECT  8.453 40.128 10.508 40.584 ;
     RECT  8.104 49.584 10.508 49.608 ;
     RECT  8.243 82.272 10.508 82.296 ;
     RECT  8.281 83.808 10.508 84.168 ;
     RECT  8.291 119.472 10.508 119.496 ;
     RECT  10.508 2.148 10.612 168.492 ;
     RECT  10.612 2.418 10.804 168.222 ;
     RECT  10.804 40.128 11.441 40.584 ;
     RECT  11.441 40.176 11.699 40.584 ;
     RECT  10.804 83.808 11.699 84.168 ;
     RECT  11.699 40.176 11.837 40.344 ;
     RECT  11.837 40.32 13.208 40.344 ;
     RECT  10.804 49.584 13.208 49.608 ;
     RECT  10.804 74.976 13.208 75 ;
     RECT  10.804 82.128 13.208 82.152 ;
     RECT  11.699 83.808 13.208 83.832 ;
     RECT  10.804 119.376 13.208 119.4 ;
     RECT  13.208 2.148 13.312 168.492 ;
     RECT  13.312 2.418 13.504 168.222 ;
     RECT  13.504 40.32 13.619 40.344 ;
     RECT  13.504 82.128 14.821 82.152 ;
     RECT  13.504 119.376 14.821 119.4 ;
     RECT  14.821 82.128 14.861 82.248 ;
     RECT  14.821 119.376 14.861 119.496 ;
     RECT  13.504 46.512 15.908 46.536 ;
     RECT  13.504 49.584 15.908 49.608 ;
     RECT  13.504 74.88 15.908 74.904 ;
     RECT  14.861 82.224 15.908 82.248 ;
     RECT  13.504 83.808 15.908 83.832 ;
     RECT  14.861 119.472 15.908 119.496 ;
     RECT  15.908 2.148 16.012 168.492 ;
     RECT  16.012 2.418 16.204 168.222 ;
     RECT  16.204 46.512 18.608 46.536 ;
     RECT  16.204 49.584 18.608 49.608 ;
     RECT  16.204 74.88 18.608 74.904 ;
     RECT  16.204 82.224 18.608 82.248 ;
     RECT  16.204 83.808 18.608 83.832 ;
     RECT  16.204 119.472 18.608 119.496 ;
     RECT  18.608 2.148 18.712 168.492 ;
     RECT  18.712 2.418 18.904 168.222 ;
     RECT  18.904 46.512 21.308 46.536 ;
     RECT  18.904 49.584 21.308 49.608 ;
     RECT  18.904 74.88 21.308 74.904 ;
     RECT  18.904 82.128 21.308 82.152 ;
     RECT  18.904 83.808 21.308 83.832 ;
     RECT  18.904 119.376 21.308 119.4 ;
     RECT  21.308 2.148 21.412 168.492 ;
     RECT  21.412 2.418 21.604 168.222 ;
     RECT  21.604 93.072 22.141 93.48 ;
     RECT  21.604 99.744 22.241 100.008 ;
     RECT  21.604 74.88 22.499 74.904 ;
     RECT  21.604 119.376 22.597 119.4 ;
     RECT  22.597 119.136 22.681 119.4 ;
     RECT  21.604 82.128 22.813 82.152 ;
     RECT  22.813 82.128 22.853 82.248 ;
     RECT  22.141 93.072 22.853 93.096 ;
     RECT  21.604 46.512 24.008 46.536 ;
     RECT  21.604 49.584 24.008 49.608 ;
     RECT  22.853 82.224 24.008 82.248 ;
     RECT  21.604 83.808 24.008 83.832 ;
     RECT  22.241 99.984 24.008 100.008 ;
     RECT  22.681 119.376 24.008 119.4 ;
     RECT  24.008 2.148 24.112 168.492 ;
     RECT  24.112 2.418 24.304 168.222 ;
     RECT  24.304 46.512 26.708 46.536 ;
     RECT  24.304 49.584 26.708 49.608 ;
     RECT  24.304 82.224 26.708 82.248 ;
     RECT  24.304 83.808 26.708 83.832 ;
     RECT  24.304 99.984 26.708 100.008 ;
     RECT  24.304 119.472 26.708 119.496 ;
     RECT  26.708 2.148 26.812 168.492 ;
     RECT  26.812 2.418 27.004 168.222 ;
     RECT  27.004 46.512 29.408 46.536 ;
     RECT  27.004 49.584 29.408 49.608 ;
     RECT  27.004 82.224 29.408 82.248 ;
     RECT  27.004 83.808 29.408 83.832 ;
     RECT  27.004 99.984 29.408 100.008 ;
     RECT  27.004 119.472 29.408 119.496 ;
     RECT  29.408 2.148 29.512 168.492 ;
     RECT  29.512 2.418 29.704 168.222 ;
     RECT  29.704 82.128 30.769 82.152 ;
     RECT  29.704 119.376 30.769 119.4 ;
     RECT  30.769 82.128 30.809 82.248 ;
     RECT  30.769 119.376 30.809 119.496 ;
     RECT  29.704 46.512 32.108 46.536 ;
     RECT  29.704 49.584 32.108 49.608 ;
     RECT  30.809 82.224 32.108 82.248 ;
     RECT  29.704 83.808 32.108 83.832 ;
     RECT  29.704 99.984 32.108 100.008 ;
     RECT  30.809 119.472 32.108 119.496 ;
     RECT  32.108 2.148 32.212 168.492 ;
     RECT  32.212 2.418 32.404 168.222 ;
     RECT  34.693 132.144 34.765 132.168 ;
     RECT  32.404 46.512 34.808 46.536 ;
     RECT  32.404 49.584 34.808 49.608 ;
     RECT  32.404 82.224 34.808 82.248 ;
     RECT  32.404 83.808 34.808 83.832 ;
     RECT  32.404 99.984 34.808 100.008 ;
     RECT  32.404 119.472 34.808 119.496 ;
     RECT  34.693 123.744 34.808 123.768 ;
     RECT  34.549 126 34.808 126.024 ;
     RECT  34.801 128.16 34.808 128.184 ;
     RECT  34.369 129.936 34.808 129.96 ;
     RECT  34.765 132.144 34.808 132.216 ;
     RECT  34.808 2.148 34.912 168.492 ;
     RECT  34.912 2.418 35.104 168.222 ;
     RECT  35.104 127.632 35.165 132.216 ;
     RECT  35.165 127.632 35.389 129.432 ;
     RECT  35.165 130.512 35.453 132.216 ;
     RECT  35.104 122.88 35.603 126.6 ;
     RECT  35.603 123.024 35.741 126.6 ;
     RECT  35.389 127.632 35.813 128.616 ;
     RECT  35.453 130.512 36.209 131.304 ;
     RECT  35.104 117.888 36.241 117.912 ;
     RECT  35.104 119.088 36.241 120.456 ;
     RECT  36.241 117.888 36.245 120.456 ;
     RECT  35.104 121.44 36.245 121.56 ;
     RECT  35.741 123.024 36.389 124.824 ;
     RECT  35.104 134.352 36.673 136.056 ;
     RECT  36.209 130.512 36.709 131.112 ;
     RECT  36.673 133.44 36.925 136.056 ;
     RECT  35.813 127.728 37.1 128.616 ;
     RECT  37.033 132.384 37.105 132.408 ;
     RECT  36.925 133.44 37.105 136.776 ;
     RECT  37.105 132.384 37.177 136.776 ;
     RECT  36.245 121.44 37.244 121.464 ;
     RECT  36.889 142.512 37.244 142.536 ;
     RECT  37.244 120.72 37.285 121.464 ;
     RECT  37.244 142.512 37.285 142.632 ;
     RECT  37.285 120.72 37.381 121.56 ;
     RECT  36.389 124.8 37.429 124.824 ;
     RECT  35.104 46.512 37.508 46.536 ;
     RECT  35.104 49.584 37.508 49.608 ;
     RECT  35.104 82.224 37.508 82.248 ;
     RECT  35.104 83.808 37.508 83.832 ;
     RECT  35.104 99.984 37.508 100.008 ;
     RECT  37.381 110.496 37.508 110.52 ;
     RECT  36.245 117.888 37.508 119.496 ;
     RECT  37.381 120.72 37.508 121.848 ;
     RECT  36.389 123.024 37.508 123.768 ;
     RECT  37.429 124.8 37.508 124.872 ;
     RECT  35.741 125.856 37.508 126.6 ;
     RECT  37.1 127.728 37.508 128.856 ;
     RECT  36.709 130.368 37.508 131.112 ;
     RECT  37.177 132.384 37.508 137.64 ;
     RECT  37.329 139.392 37.508 139.416 ;
     RECT  37.285 140.736 37.508 140.76 ;
     RECT  37.285 142.512 37.508 143.064 ;
     RECT  37.357 164.736 37.508 164.76 ;
     RECT  37.508 2.148 37.612 168.492 ;
     RECT  37.612 2.418 37.804 168.222 ;
     RECT  37.804 119.136 37.865 119.832 ;
     RECT  37.825 170.352 37.957 170.376 ;
     RECT  37.804 140.736 37.973 140.76 ;
     RECT  37.804 99.984 38.003 100.872 ;
     RECT  37.957 170.352 38.044 170.52 ;
     RECT  38.044 170.352 38.153 170.472 ;
     RECT  37.804 129.984 38.195 130.008 ;
     RECT  37.804 121.68 38.225 124.872 ;
     RECT  37.804 127.056 38.297 129 ;
     RECT  37.804 148.8 38.297 149.352 ;
     RECT  38.003 100.464 38.341 100.872 ;
     RECT  37.804 139.392 38.387 139.416 ;
     RECT  37.804 141.888 38.387 141.912 ;
     RECT  37.804 164.832 38.405 164.856 ;
     RECT  37.804 92.88 38.428 93.576 ;
     RECT  37.804 142.896 38.435 143.496 ;
     RECT  37.865 119.472 38.483 119.832 ;
     RECT  37.804 54.72 38.579 54.744 ;
     RECT  38.297 148.8 38.585 148.824 ;
     RECT  37.804 52.992 38.621 53.688 ;
     RECT  38.225 121.68 38.621 124.584 ;
     RECT  37.804 94.656 38.729 95.448 ;
     RECT  37.804 163.776 38.729 163.8 ;
     RECT  37.804 166.08 38.765 166.104 ;
     RECT  38.729 95.424 38.771 95.448 ;
     RECT  38.341 100.464 38.771 100.488 ;
     RECT  37.804 117.888 38.771 117.912 ;
     RECT  37.804 82.128 38.801 82.248 ;
     RECT  37.804 132.144 38.821 132.792 ;
     RECT  37.804 134.544 38.821 135.384 ;
     RECT  37.804 130.992 38.867 131.016 ;
     RECT  38.821 132.144 38.867 135.384 ;
     RECT  38.867 132.24 38.873 135.384 ;
     RECT  37.804 144.624 38.873 144.648 ;
     RECT  38.873 132.672 38.908 135.384 ;
     RECT  38.621 52.992 38.924 53.016 ;
     RECT  38.428 92.88 38.981 93.048 ;
     RECT  38.924 52.368 39.011 53.016 ;
     RECT  37.804 49.584 39.049 49.608 ;
     RECT  38.908 132.672 39.053 132.936 ;
     RECT  38.621 122.4 39.089 124.584 ;
     RECT  38.908 134.544 39.089 135.384 ;
     RECT  38.483 119.808 39.197 119.832 ;
     RECT  39.089 134.88 39.253 135.384 ;
     RECT  37.804 47.76 39.337 47.784 ;
     RECT  38.153 170.448 39.395 170.472 ;
     RECT  39.049 49.584 39.409 49.848 ;
     RECT  38.297 127.056 39.409 128.856 ;
     RECT  39.337 47.76 39.445 47.928 ;
     RECT  39.409 49.584 39.481 50.328 ;
     RECT  37.804 51.312 39.481 51.336 ;
     RECT  39.253 134.88 39.541 135.864 ;
     RECT  39.493 136.896 39.541 136.92 ;
     RECT  39.661 91.344 39.733 91.368 ;
     RECT  39.481 49.584 39.769 51.336 ;
     RECT  39.409 127.056 39.769 129.192 ;
     RECT  39.733 91.344 39.877 91.896 ;
     RECT  38.981 92.88 39.877 93 ;
     RECT  39.877 89.808 39.949 89.832 ;
     RECT  39.877 91.344 40.021 93 ;
     RECT  39.949 88.848 40.028 89.832 ;
     RECT  37.804 104.208 40.049 104.232 ;
     RECT  37.804 83.808 40.069 83.832 ;
     RECT  40.028 88.8 40.093 89.832 ;
     RECT  40.021 90.816 40.093 93 ;
     RECT  39.541 134.88 40.165 136.92 ;
     RECT  37.804 46.512 40.208 46.536 ;
     RECT  39.445 47.76 40.208 48.216 ;
     RECT  39.769 49.248 40.208 51.336 ;
     RECT  39.011 52.992 40.208 53.016 ;
     RECT  38.965 73.824 40.208 73.848 ;
     RECT  38.801 82.224 40.208 82.248 ;
     RECT  40.069 83.76 40.208 83.832 ;
     RECT  40.021 84.912 40.208 84.936 ;
     RECT  40.093 88.416 40.208 89.832 ;
     RECT  40.093 90.816 40.208 93.048 ;
     RECT  40.049 103.872 40.208 104.232 ;
     RECT  39.349 105.936 40.208 105.96 ;
     RECT  37.804 110.496 40.208 110.52 ;
     RECT  39.553 120.288 40.208 120.312 ;
     RECT  39.089 122.496 40.208 124.584 ;
     RECT  39.769 126.96 40.208 129.192 ;
     RECT  39.229 130.512 40.208 130.872 ;
     RECT  39.053 132.816 40.208 132.936 ;
     RECT  40.165 134.784 40.208 136.92 ;
     RECT  39.581 138.48 40.208 138.504 ;
     RECT  39.445 140.016 40.208 140.04 ;
     RECT  39.481 141.024 40.208 141.048 ;
     RECT  38.435 142.896 40.208 142.92 ;
     RECT  39.308 149.616 40.208 149.688 ;
     RECT  40.208 2.148 40.312 168.492 ;
     RECT  40.312 2.418 40.504 168.222 ;
     RECT  40.504 122.496 40.529 125.448 ;
     RECT  40.504 120.048 40.565 120.312 ;
     RECT  40.504 83.808 40.601 83.928 ;
     RECT  40.504 88.8 40.601 96.984 ;
     RECT  40.529 122.832 40.673 125.448 ;
     RECT  40.673 124.8 40.717 125.448 ;
     RECT  40.504 86.64 40.745 86.664 ;
     RECT  40.565 120.048 40.787 120.072 ;
     RECT  40.504 128.304 40.889 128.328 ;
     RECT  40.504 52.416 40.931 53.4 ;
     RECT  40.504 102.816 40.931 104.328 ;
     RECT  40.504 55.824 40.979 55.848 ;
     RECT  40.504 142.512 41.033 142.536 ;
     RECT  40.504 118.992 41.141 119.016 ;
     RECT  40.673 122.832 41.429 123.528 ;
     RECT  40.504 114.528 41.465 114.552 ;
     RECT  40.504 87.648 41.497 87.672 ;
     RECT  41.533 44.256 41.569 44.28 ;
     RECT  40.504 137.568 41.569 137.88 ;
     RECT  40.504 139.2 41.569 140.136 ;
     RECT  40.504 46.848 41.605 50.808 ;
     RECT  40.601 83.904 41.605 83.928 ;
     RECT  41.605 45.696 41.641 50.808 ;
     RECT  41.497 87.456 41.641 87.672 ;
     RECT  40.601 88.8 41.641 89.832 ;
     RECT  41.497 131.904 41.641 131.928 ;
     RECT  41.641 131.136 41.677 131.928 ;
     RECT  41.605 133.056 41.677 133.08 ;
     RECT  41.569 137.568 41.677 140.136 ;
     RECT  41.641 87.456 41.713 89.832 ;
     RECT  41.429 123.504 41.713 123.528 ;
     RECT  40.504 82.224 41.749 82.248 ;
     RECT  41.605 83.76 41.749 83.928 ;
     RECT  41.749 82.224 41.785 84.36 ;
     RECT  41.713 87.456 41.821 89.88 ;
     RECT  40.601 91.008 41.821 96.984 ;
     RECT  41.749 114 41.833 114.024 ;
     RECT  40.504 107.616 41.933 107.64 ;
     RECT  41.785 82.224 41.987 84.984 ;
     RECT  41.569 44.256 41.989 44.376 ;
     RECT  40.504 105.936 41.989 105.96 ;
     RECT  41.749 120.192 41.989 120.216 ;
     RECT  41.989 44.256 42.001 44.472 ;
     RECT  41.641 45.504 42.001 50.808 ;
     RECT  40.931 52.608 42.001 53.4 ;
     RECT  40.504 134.208 42.001 136.248 ;
     RECT  42.001 44.256 42.037 50.808 ;
     RECT  42.001 52.32 42.037 53.4 ;
     RECT  41.989 119.712 42.037 120.216 ;
     RECT  41.677 131.136 42.037 133.08 ;
     RECT  42.037 52.128 42.073 53.4 ;
     RECT  42.037 119.712 42.073 120.312 ;
     RECT  42.037 130.56 42.073 133.08 ;
     RECT  42.001 134.112 42.073 136.248 ;
     RECT  42.037 44.16 42.109 50.808 ;
     RECT  42.073 51.84 42.109 53.4 ;
     RECT  41.821 87.456 42.145 96.984 ;
     RECT  41.677 137.472 42.145 140.136 ;
     RECT  42.145 87.36 42.253 96.984 ;
     RECT  42.217 39.36 42.325 39.384 ;
     RECT  42.073 119.712 42.325 121.08 ;
     RECT  42.325 39.36 42.373 39.48 ;
     RECT  42.109 44.16 42.397 53.4 ;
     RECT  42.373 126.432 42.421 126.456 ;
     RECT  41.713 123.504 42.433 124.344 ;
     RECT  40.717 125.424 42.433 125.448 ;
     RECT  42.433 147.216 42.505 147.24 ;
     RECT  41.785 128.688 42.517 128.712 ;
     RECT  42.517 128.688 42.541 128.856 ;
     RECT  42.505 38.304 42.613 38.328 ;
     RECT  42.541 128.208 42.649 128.856 ;
     RECT  42.209 85.488 42.659 85.56 ;
     RECT  42.397 44.16 42.661 53.592 ;
     RECT  42.661 43.968 42.685 53.592 ;
     RECT  42.661 64.704 42.709 64.728 ;
     RECT  42.133 107.808 42.709 107.832 ;
     RECT  42.073 130.56 42.709 136.248 ;
     RECT  42.649 128.16 42.761 128.856 ;
     RECT  42.145 137.472 42.793 140.184 ;
     RECT  42.761 128.16 42.905 128.232 ;
     RECT  42.421 37.008 42.908 37.032 ;
     RECT  42.613 38.208 42.908 38.328 ;
     RECT  42.373 39.36 42.908 39.912 ;
     RECT  42.709 64.608 42.908 64.728 ;
     RECT  40.504 73.824 42.908 73.848 ;
     RECT  42.181 80.928 42.908 80.952 ;
     RECT  41.987 82.224 42.908 84.36 ;
     RECT  41.989 105.936 42.908 106.632 ;
     RECT  42.709 107.808 42.908 108.216 ;
     RECT  40.504 110.496 42.908 110.52 ;
     RECT  42.325 119.712 42.908 121.992 ;
     RECT  42.433 123.504 42.908 125.448 ;
     RECT  42.421 126.432 42.908 126.552 ;
     RECT  42.685 43.968 42.973 53.688 ;
     RECT  42.908 2.148 43.012 41.052 ;
     RECT  42.908 62.628 43.012 84.36 ;
     RECT  42.908 105.828 43.012 127.452 ;
     RECT  42.908 149.028 43.012 168.492 ;
     RECT  42.709 130.368 43.081 136.248 ;
     RECT  43.081 129.456 43.2 136.248 ;
     RECT  42.793 137.28 43.2 140.184 ;
     RECT  43.012 2.418 43.204 40.782 ;
     RECT  43.012 62.898 43.204 84.36 ;
     RECT  43.012 105.936 43.204 127.182 ;
     RECT  43.012 149.298 43.204 168.222 ;
     RECT  43.204 83.616 43.229 84.36 ;
     RECT  43.204 107.184 43.265 108.504 ;
     RECT  43.204 123.744 43.265 123.768 ;
     RECT  42.973 43.968 43.272 53.784 ;
     RECT  40.504 60.576 43.272 61.032 ;
     RECT  42.253 86.64 43.272 96.984 ;
     RECT  40.931 103.776 43.272 104.328 ;
     RECT  43.2 129.456 43.272 140.184 ;
     RECT  42.505 147.072 43.272 147.24 ;
     RECT  43.272 129.456 43.331 147.24 ;
     RECT  43.204 64.608 43.553 64.968 ;
     RECT  43.265 108.192 43.553 108.504 ;
     RECT  43.553 108.192 43.589 108.312 ;
     RECT  43.553 64.944 43.619 64.968 ;
     RECT  43.229 83.616 43.625 84.12 ;
     RECT  43.625 83.76 44.579 84.12 ;
     RECT  43.265 107.184 44.579 107.208 ;
     RECT  43.204 73.824 45.608 73.848 ;
     RECT  44.579 84.096 45.608 84.12 ;
     RECT  43.204 105.936 45.608 105.96 ;
     RECT  43.589 108.288 45.608 108.312 ;
     RECT  43.204 110.496 45.608 110.52 ;
     RECT  45.608 2.148 45.712 41.052 ;
     RECT  45.608 62.628 45.712 84.252 ;
     RECT  45.608 105.828 45.712 127.452 ;
     RECT  45.608 149.028 45.712 168.492 ;
     RECT  45.712 2.418 45.904 40.782 ;
     RECT  45.712 62.898 45.904 83.982 ;
     RECT  45.712 105.936 45.904 127.182 ;
     RECT  45.712 149.298 45.904 168.222 ;
     RECT  45.904 73.824 46.793 73.944 ;
     RECT  46.793 73.824 48.308 73.848 ;
     RECT  45.904 105.936 48.308 105.96 ;
     RECT  45.904 110.496 48.308 110.52 ;
     RECT  48.308 2.148 48.412 41.052 ;
     RECT  48.308 62.628 48.412 84.252 ;
     RECT  48.308 105.828 48.412 127.452 ;
     RECT  48.308 149.028 48.412 168.492 ;
     RECT  48.412 2.418 48.604 40.782 ;
     RECT  48.412 62.898 48.604 83.982 ;
     RECT  48.412 105.936 48.604 127.182 ;
     RECT  48.412 149.298 48.604 168.222 ;
     RECT  48.604 73.824 51.008 73.848 ;
     RECT  48.604 105.936 51.008 105.96 ;
     RECT  48.604 110.496 51.008 110.52 ;
     RECT  51.008 2.148 51.112 41.052 ;
     RECT  51.008 62.628 51.112 84.252 ;
     RECT  51.008 105.828 51.112 127.452 ;
     RECT  51.008 149.028 51.112 168.492 ;
     RECT  51.112 2.418 51.304 40.782 ;
     RECT  51.112 62.898 51.304 83.982 ;
     RECT  51.112 105.936 51.304 127.182 ;
     RECT  51.112 149.298 51.304 168.222 ;
     RECT  51.304 73.824 53.708 73.848 ;
     RECT  51.304 105.936 53.708 105.96 ;
     RECT  51.304 110.496 53.708 110.52 ;
     RECT  53.708 2.148 53.812 41.052 ;
     RECT  53.708 62.628 53.812 84.252 ;
     RECT  53.708 105.828 53.812 127.452 ;
     RECT  53.708 149.028 53.812 168.492 ;
     RECT  53.812 2.418 54.004 40.782 ;
     RECT  53.812 62.898 54.004 83.982 ;
     RECT  53.812 105.936 54.004 127.182 ;
     RECT  53.812 149.298 54.004 168.222 ;
     RECT  54.004 73.824 54.749 73.944 ;
     RECT  54.749 73.824 56.408 73.848 ;
     RECT  54.004 105.936 56.408 105.96 ;
     RECT  54.004 110.496 56.408 110.52 ;
     RECT  56.408 2.148 56.512 41.052 ;
     RECT  56.408 62.628 56.512 84.252 ;
     RECT  56.408 105.828 56.512 127.452 ;
     RECT  56.408 149.028 56.512 168.492 ;
     RECT  56.512 2.418 56.704 40.782 ;
     RECT  56.512 62.898 56.704 83.982 ;
     RECT  56.512 105.936 56.704 127.182 ;
     RECT  56.512 149.298 56.704 168.222 ;
     RECT  56.704 73.824 59.108 73.848 ;
     RECT  56.704 105.936 59.108 105.96 ;
     RECT  56.704 110.496 59.108 110.52 ;
     RECT  59.108 2.148 59.212 41.052 ;
     RECT  59.108 62.628 59.212 84.252 ;
     RECT  59.108 105.828 59.212 127.452 ;
     RECT  59.108 149.028 59.212 168.492 ;
     RECT  59.212 2.418 59.404 40.782 ;
     RECT  59.212 62.898 59.404 83.982 ;
     RECT  59.212 105.936 59.404 127.182 ;
     RECT  59.212 149.298 59.404 168.222 ;
     RECT  59.404 73.824 61.808 73.848 ;
     RECT  59.404 105.936 61.808 105.96 ;
     RECT  59.404 110.496 61.808 110.52 ;
     RECT  61.808 2.148 61.912 41.052 ;
     RECT  61.808 62.628 61.912 84.252 ;
     RECT  61.808 105.828 61.912 127.452 ;
     RECT  61.808 149.028 61.912 168.492 ;
     RECT  61.912 2.418 62.104 40.782 ;
     RECT  61.912 62.898 62.104 83.982 ;
     RECT  61.912 105.936 62.104 127.182 ;
     RECT  61.912 149.298 62.104 168.222 ;
     RECT  62.104 73.92 62.741 74.088 ;
     RECT  62.104 110.352 62.741 110.52 ;
     RECT  62.741 74.064 64.508 74.088 ;
     RECT  62.104 105.936 64.508 105.96 ;
     RECT  62.741 110.352 64.508 110.376 ;
     RECT  64.508 2.148 64.612 41.052 ;
     RECT  64.508 62.628 64.612 84.252 ;
     RECT  64.508 105.828 64.612 127.452 ;
     RECT  64.508 149.028 64.612 168.492 ;
     RECT  64.612 62.898 64.645 84.252 ;
     RECT  64.612 2.418 64.804 40.782 ;
     RECT  64.645 62.898 64.804 84.36 ;
     RECT  64.612 105.84 64.804 127.182 ;
     RECT  64.612 149.298 64.804 168.222 ;
     RECT  64.804 110.352 65.009 110.616 ;
     RECT  64.804 84.192 65.027 84.36 ;
     RECT  65.009 110.496 65.027 110.616 ;
     RECT  65.027 84.336 65.603 84.36 ;
     RECT  64.804 105.84 65.629 105.864 ;
     RECT  64.804 73.824 67.208 74.088 ;
     RECT  64.804 126.144 67.208 126.168 ;
     RECT  67.208 2.148 67.312 41.052 ;
     RECT  67.208 62.628 67.312 84.252 ;
     RECT  67.208 105.828 67.312 127.452 ;
     RECT  67.208 149.028 67.312 168.492 ;
     RECT  67.312 2.418 67.504 40.782 ;
     RECT  67.312 62.898 67.504 83.982 ;
     RECT  67.312 106.098 67.504 127.182 ;
     RECT  67.312 149.298 67.504 168.222 ;
     RECT  67.504 73.824 69.908 74.088 ;
     RECT  67.504 126.144 69.908 126.168 ;
     RECT  69.908 2.148 70.012 41.052 ;
     RECT  69.908 62.628 70.012 84.252 ;
     RECT  69.908 105.828 70.012 127.452 ;
     RECT  69.908 149.028 70.012 168.492 ;
     RECT  70.012 2.418 70.204 40.782 ;
     RECT  70.012 62.898 70.204 83.982 ;
     RECT  70.012 106.098 70.204 127.182 ;
     RECT  70.012 149.298 70.204 168.222 ;
     RECT  70.204 73.824 72.608 74.088 ;
     RECT  70.204 126.144 72.608 126.168 ;
     RECT  72.608 2.148 72.712 41.052 ;
     RECT  72.608 62.628 72.712 84.252 ;
     RECT  72.608 105.828 72.712 127.452 ;
     RECT  72.608 149.028 72.712 168.492 ;
     RECT  72.712 2.418 72.904 40.782 ;
     RECT  72.712 62.898 72.904 83.982 ;
     RECT  72.712 106.098 72.904 127.182 ;
     RECT  72.712 149.298 72.904 168.222 ;
     RECT  73.933 124.8 74.545 124.824 ;
     RECT  72.904 125.904 74.545 126.168 ;
     RECT  43.331 129.6 74.725 147.24 ;
     RECT  43.272 43.2 75.12 61.032 ;
     RECT  43.272 86.4 75.12 104.328 ;
     RECT  74.725 129.504 75.12 147.24 ;
     RECT  75.12 129.504 75.305 140.184 ;
     RECT  72.904 73.824 75.308 74.088 ;
     RECT  75.085 84.96 75.308 84.984 ;
     RECT  74.545 124.8 75.308 126.168 ;
     RECT  74.941 128.256 75.308 128.28 ;
     RECT  75.12 43.968 75.377 53.784 ;
     RECT  75.308 2.148 75.412 41.052 ;
     RECT  75.308 62.628 75.412 84.984 ;
     RECT  75.308 105.828 75.412 128.28 ;
     RECT  75.308 149.028 75.412 168.492 ;
     RECT  75.412 128.256 75.413 128.28 ;
     RECT  75.305 130.32 75.413 140.184 ;
     RECT  75.412 62.898 75.449 84.984 ;
     RECT  75.377 44.064 75.485 53.784 ;
     RECT  75.12 87.168 75.485 96.984 ;
     RECT  75.412 2.418 75.604 40.782 ;
     RECT  75.449 62.898 75.604 84.024 ;
     RECT  75.412 106.098 75.604 127.182 ;
     RECT  75.412 149.298 75.604 168.222 ;
     RECT  75.604 84 75.809 84.024 ;
     RECT  75.12 60.576 76.097 61.032 ;
     RECT  75.485 87.168 76.673 96.792 ;
     RECT  76.673 87.168 76.745 96.696 ;
     RECT  75.604 125.376 76.787 126.168 ;
     RECT  75.604 73.824 76.853 74.088 ;
     RECT  75.485 44.064 78.008 53.496 ;
     RECT  76.097 60.576 78.008 60.6 ;
     RECT  77.101 73.776 78.008 73.8 ;
     RECT  76.745 87.168 78.008 96.6 ;
     RECT  75.12 103.776 78.008 104.328 ;
     RECT  76.787 126.144 78.008 126.168 ;
     RECT  75.413 130.32 78.008 139.992 ;
     RECT  75.12 147.072 78.008 147.24 ;
     RECT  78.008 2.148 78.112 168.492 ;
     RECT  78.112 2.418 78.304 168.222 ;
     RECT  78.304 130.32 79.517 133.032 ;
     RECT  78.304 44.064 80.708 47.448 ;
     RECT  78.304 73.776 80.708 73.8 ;
     RECT  78.304 87.168 80.708 90.888 ;
     RECT  78.304 103.776 80.708 103.848 ;
     RECT  78.304 126.144 80.708 126.168 ;
     RECT  79.517 130.56 80.708 133.032 ;
     RECT  78.304 147.072 80.708 147.24 ;
     RECT  80.708 2.148 80.812 168.492 ;
     RECT  80.812 2.418 81.004 168.222 ;
     RECT  81.004 44.064 83.408 47.448 ;
     RECT  81.004 73.776 83.408 73.8 ;
     RECT  81.004 87.264 83.408 90.888 ;
     RECT  81.004 103.776 83.408 103.848 ;
     RECT  81.004 126.144 83.408 126.168 ;
     RECT  81.004 130.56 83.408 133.032 ;
     RECT  81.004 147.072 83.408 147.24 ;
     RECT  83.408 2.148 83.512 168.492 ;
     RECT  83.512 2.418 83.704 168.222 ;
     RECT  83.704 88.704 83.801 90.648 ;
     RECT  83.704 130.56 83.801 131.928 ;
     RECT  83.704 44.112 84.089 45.72 ;
     RECT  84.089 44.352 84.161 45.72 ;
     RECT  83.704 133.008 84.197 133.032 ;
     RECT  83.801 89.808 84.413 89.832 ;
     RECT  83.801 88.704 84.521 88.728 ;
     RECT  84.161 44.352 84.557 44.376 ;
     RECT  84.161 45.696 84.629 45.72 ;
     RECT  83.801 131.904 84.665 131.928 ;
     RECT  83.704 73.776 86.108 73.8 ;
     RECT  83.704 103.776 86.108 103.848 ;
     RECT  83.704 126.144 86.108 126.168 ;
     RECT  83.801 130.56 86.108 130.584 ;
     RECT  83.704 147.072 86.108 147.24 ;
     RECT  86.108 2.148 86.212 168.492 ;
     RECT  86.212 2.418 86.404 168.222 ;
     RECT  86.404 73.776 88.808 73.8 ;
     RECT  86.404 103.776 88.808 103.848 ;
     RECT  86.404 126.144 88.808 126.168 ;
     RECT  86.404 130.56 88.808 130.584 ;
     RECT  86.404 147.072 88.808 147.24 ;
     RECT  88.808 2.148 88.912 168.492 ;
     RECT  88.912 2.418 89.104 168.222 ;
     RECT  89.104 138.768 89.219 141.864 ;
     RECT  89.219 138.768 89.345 141.288 ;
     RECT  89.345 138.768 89.363 140.184 ;
     RECT  89.104 52.992 89.555 54.024 ;
     RECT  89.555 53.568 89.596 54.024 ;
     RECT  89.104 99.168 89.669 100.344 ;
     RECT  89.104 56.256 89.957 56.28 ;
     RECT  89.104 125.616 89.987 126.168 ;
     RECT  89.104 134.832 89.987 135.096 ;
     RECT  89.987 135.072 90.035 135.096 ;
     RECT  89.363 138.768 90.035 139.704 ;
     RECT  89.104 43.344 90.137 43.368 ;
     RECT  89.104 55.248 90.241 55.272 ;
     RECT  89.596 53.568 90.281 53.592 ;
     RECT  89.104 143.04 90.529 143.064 ;
     RECT  90.529 142.464 90.637 143.064 ;
     RECT  89.104 40.56 90.673 40.92 ;
     RECT  89.669 99.168 90.949 100.152 ;
     RECT  90.241 55.152 91.196 55.272 ;
     RECT  91.237 44.448 91.381 44.472 ;
     RECT  90.385 84.672 91.381 84.696 ;
     RECT  91.333 87.84 91.381 87.864 ;
     RECT  90.457 42.096 91.465 42.12 ;
     RECT  91.381 84.576 91.465 84.696 ;
     RECT  89.987 125.616 91.501 125.64 ;
     RECT  90.673 40.56 91.508 40.968 ;
     RECT  91.465 42.096 91.508 42.744 ;
     RECT  91.381 44.112 91.508 44.472 ;
     RECT  90.601 53.52 91.508 53.544 ;
     RECT  91.196 55.152 91.508 55.608 ;
     RECT  89.104 73.776 91.508 73.8 ;
     RECT  91.465 82.416 91.508 82.44 ;
     RECT  91.465 84.144 91.508 84.696 ;
     RECT  90.205 86.016 91.508 86.04 ;
     RECT  91.381 87.84 91.508 88.104 ;
     RECT  91.381 98.064 91.508 98.088 ;
     RECT  90.949 99.168 91.508 100.536 ;
     RECT  89.104 103.776 91.508 103.848 ;
     RECT  91.501 125.616 91.508 126.216 ;
     RECT  89.104 127.632 91.508 127.656 ;
     RECT  89.104 130.56 91.508 130.584 ;
     RECT  90.035 139.68 91.508 139.704 ;
     RECT  89.345 141.264 91.508 141.288 ;
     RECT  90.637 142.32 91.508 143.064 ;
     RECT  89.104 147.072 91.508 147.24 ;
     RECT  91.508 2.148 91.612 168.492 ;
     RECT  91.612 2.418 91.804 168.222 ;
     RECT  91.804 39.36 91.955 41.256 ;
     RECT  91.804 100.512 91.955 101.016 ;
     RECT  91.804 138.96 91.955 139.704 ;
     RECT  91.804 55.152 92.009 55.176 ;
     RECT  91.804 81.792 92.009 84.6 ;
     RECT  92.009 81.792 92.369 83.352 ;
     RECT  91.955 39.888 92.693 41.256 ;
     RECT  91.955 100.512 92.693 100.536 ;
     RECT  91.804 42.72 92.729 42.744 ;
     RECT  91.804 130.56 92.765 130.584 ;
     RECT  91.804 125.616 92.869 127.704 ;
     RECT  91.804 96.192 92.873 96.456 ;
     RECT  91.804 87.984 92.945 88.008 ;
     RECT  92.869 125.616 93.053 128.328 ;
     RECT  91.804 52.464 93.085 52.488 ;
     RECT  92.873 96.192 93.089 96.216 ;
     RECT  92.833 97.44 93.109 97.464 ;
     RECT  91.804 98.928 93.109 99.192 ;
     RECT  91.804 44.112 93.116 44.136 ;
     RECT  93.085 52.368 93.125 52.488 ;
     RECT  91.955 139.68 93.157 139.704 ;
     RECT  93.109 97.44 93.196 99.192 ;
     RECT  93.116 42.768 93.197 44.472 ;
     RECT  93.196 98.928 93.197 99.192 ;
     RECT  93.197 42.768 93.203 43.32 ;
     RECT  93.197 44.448 93.203 44.472 ;
     RECT  93.125 52.368 93.203 52.392 ;
     RECT  92.009 84.576 93.229 84.6 ;
     RECT  92.869 55.968 93.337 55.992 ;
     RECT  92.693 40.56 93.481 41.256 ;
     RECT  93.157 139.632 93.481 139.704 ;
     RECT  93.481 139.632 93.517 139.992 ;
     RECT  91.804 141.264 93.517 141.288 ;
     RECT  92.369 83.328 93.625 83.352 ;
     RECT  93.229 84.576 93.625 85.512 ;
     RECT  93.481 40.56 93.957 41.304 ;
     RECT  93.203 42.768 93.957 42.792 ;
     RECT  93.053 126.192 94.069 128.328 ;
     RECT  93.265 39.312 94.129 39.336 ;
     RECT  93.957 40.56 94.129 42.792 ;
     RECT  94.129 39.312 94.208 42.792 ;
     RECT  93.337 55.152 94.208 55.992 ;
     RECT  92.369 81.792 94.208 81.816 ;
     RECT  93.625 83.328 94.208 85.512 ;
     RECT  93.196 97.44 94.208 97.464 ;
     RECT  93.197 98.928 94.208 98.952 ;
     RECT  91.804 103.776 94.208 103.848 ;
     RECT  94.069 125.904 94.208 128.328 ;
     RECT  93.517 139.632 94.208 141.288 ;
     RECT  91.804 142.416 94.208 143.448 ;
     RECT  91.804 147.072 94.208 147.24 ;
     RECT  94.208 2.148 94.312 168.492 ;
     RECT  94.312 2.418 94.504 168.222 ;
     RECT  94.504 39.312 94.565 42.936 ;
     RECT  94.565 39.312 94.637 40.056 ;
     RECT  94.504 103.776 94.709 103.848 ;
     RECT  94.504 125.712 94.745 128.184 ;
     RECT  94.709 103.776 94.889 103.8 ;
     RECT  94.504 147.072 95.177 147.096 ;
     RECT  94.637 39.888 95.749 40.056 ;
     RECT  94.504 53.424 95.749 54.024 ;
     RECT  94.504 55.008 95.749 55.032 ;
     RECT  94.504 56.304 95.749 56.616 ;
     RECT  94.504 83.232 95.749 85.848 ;
     RECT  94.504 97.632 95.749 99.048 ;
     RECT  94.745 125.712 95.749 126.6 ;
     RECT  95.749 96.336 95.785 96.504 ;
     RECT  95.749 97.632 95.785 99.24 ;
     RECT  95.749 125.568 95.785 126.6 ;
     RECT  94.745 128.16 95.785 128.184 ;
     RECT  94.504 142.416 95.785 142.728 ;
     RECT  94.565 41.76 95.893 42.936 ;
     RECT  95.749 52.56 95.893 55.032 ;
     RECT  95.749 56.304 95.893 56.904 ;
     RECT  95.785 125.568 95.893 128.184 ;
     RECT  94.504 139.392 95.893 141.144 ;
     RECT  95.749 38.736 96.289 40.056 ;
     RECT  95.893 41.616 96.289 42.936 ;
     RECT  94.504 81.36 96.289 81.384 ;
     RECT  95.749 82.368 96.289 85.848 ;
     RECT  95.785 96.336 96.289 99.24 ;
     RECT  95.893 139.392 96.289 141.432 ;
     RECT  95.785 142.416 96.289 143.304 ;
     RECT  96.289 38.736 96.325 42.936 ;
     RECT  96.289 96.336 96.325 99.816 ;
     RECT  96.289 139.392 96.325 143.304 ;
     RECT  95.893 52.56 96.901 56.904 ;
     RECT  96.325 96.336 96.901 100.392 ;
     RECT  96.325 139.104 96.901 143.304 ;
     RECT  96.901 138.96 97.477 143.304 ;
     RECT  96.325 38.736 98.22 43.224 ;
     RECT  96.901 52.56 98.22 57.048 ;
     RECT  96.289 81.36 98.22 85.848 ;
     RECT  96.901 96.336 98.22 100.824 ;
     RECT  95.893 125.136 98.22 128.184 ;
     RECT  97.477 138.96 98.22 143.448 ;
     RECT  98.22 83.472 98.273 83.496 ;
     RECT  98.22 99.024 98.273 99.048 ;
    LAYER M5 ;
     RECT  2.4 2.137 2.52 2.151 ;
     RECT  5.1 2.137 5.22 2.151 ;
     RECT  7.8 2.137 7.92 2.151 ;
     RECT  10.5 2.137 10.62 2.151 ;
     RECT  13.2 2.137 13.32 2.151 ;
     RECT  15.9 2.137 16.02 2.151 ;
     RECT  18.6 2.137 18.72 2.151 ;
     RECT  21.3 2.137 21.42 2.151 ;
     RECT  24 2.137 24.12 2.151 ;
     RECT  26.7 2.137 26.82 2.151 ;
     RECT  29.4 2.137 29.52 2.151 ;
     RECT  32.1 2.137 32.22 2.151 ;
     RECT  34.8 2.137 34.92 2.151 ;
     RECT  37.5 2.137 37.62 2.151 ;
     RECT  40.2 2.137 40.32 2.151 ;
     RECT  42.9 2.137 43.02 2.151 ;
     RECT  45.6 2.137 45.72 2.151 ;
     RECT  48.3 2.137 48.42 2.151 ;
     RECT  51 2.137 51.12 2.151 ;
     RECT  53.7 2.137 53.82 2.151 ;
     RECT  56.4 2.137 56.52 2.151 ;
     RECT  59.1 2.137 59.22 2.151 ;
     RECT  61.8 2.137 61.92 2.151 ;
     RECT  64.5 2.137 64.62 2.151 ;
     RECT  67.2 2.137 67.32 2.151 ;
     RECT  69.9 2.137 70.02 2.151 ;
     RECT  72.6 2.137 72.72 2.151 ;
     RECT  75.3 2.137 75.42 2.151 ;
     RECT  78 2.137 78.12 2.151 ;
     RECT  80.7 2.137 80.82 2.151 ;
     RECT  83.4 2.137 83.52 2.151 ;
     RECT  86.1 2.137 86.22 2.151 ;
     RECT  88.8 2.137 88.92 2.151 ;
     RECT  91.5 2.137 91.62 2.151 ;
     RECT  94.2 2.137 94.32 2.151 ;
     RECT  7.8 2.151 8.112 33.541 ;
     RECT  7.8 33.541 8.472 34.835 ;
     RECT  2.4 2.151 2.712 35.845 ;
     RECT  7.8 34.835 8.112 36.373 ;
     RECT  5.1 2.151 5.412 36.997 ;
     RECT  42.9 2.151 43.212 36.997 ;
     RECT  5.1 36.997 5.88 37.189 ;
     RECT  91.5 2.151 91.812 39.349 ;
     RECT  42.432 36.997 43.212 39.877 ;
     RECT  91.5 39.349 91.944 39.923 ;
     RECT  10.5 2.151 10.812 40.165 ;
     RECT  13.2 2.151 13.512 40.309 ;
     RECT  2.4 35.845 3.096 41.075 ;
     RECT  94.2 2.151 94.512 41.269 ;
     RECT  7.8 36.373 8.28 41.363 ;
     RECT  5.1 37.189 5.928 41.651 ;
     RECT  93.984 41.269 94.512 42.035 ;
     RECT  91.5 39.923 91.812 42.085 ;
     RECT  42.384 39.877 43.212 44.149 ;
     RECT  7.8 41.363 8.112 44.437 ;
     RECT  42.048 44.149 43.212 44.437 ;
     RECT  91.392 42.085 91.812 44.437 ;
     RECT  2.4 41.075 2.712 44.485 ;
     RECT  2.256 44.485 2.712 44.723 ;
     RECT  3.936 44.389 3.96 45.731 ;
     RECT  13.2 40.309 13.608 46.547 ;
     RECT  7.8 44.437 8.376 49.619 ;
     RECT  93.168 42.757 93.192 52.403 ;
     RECT  40.2 2.151 40.512 52.405 ;
     RECT  88.8 2.151 89.112 52.981 ;
     RECT  37.5 2.151 37.812 53.653 ;
     RECT  38.976 52.357 39 53.653 ;
     RECT  88.8 52.981 89.544 54.035 ;
     RECT  37.5 53.653 39 54.755 ;
     RECT  40.2 52.405 40.92 55.813 ;
     RECT  40.2 55.813 40.968 61.043 ;
     RECT  42 44.437 43.212 64.837 ;
     RECT  42 64.837 43.32 64.933 ;
     RECT  91.248 44.437 91.812 73.811 ;
     RECT  64.5 2.151 64.812 73.813 ;
     RECT  38.976 54.755 39 73.859 ;
     RECT  21.3 2.151 21.612 74.869 ;
     RECT  5.1 41.651 5.412 81.445 ;
     RECT  4.32 81.445 5.412 82.021 ;
     RECT  4.32 82.021 5.544 82.307 ;
     RECT  5.1 82.307 5.544 83.077 ;
     RECT  7.8 49.619 8.112 83.125 ;
     RECT  2.4 44.723 2.712 83.173 ;
     RECT  40.2 61.043 40.512 83.749 ;
     RECT  42 64.933 43.608 83.749 ;
     RECT  41.616 83.749 44.568 83.939 ;
     RECT  41.76 83.939 44.568 84.085 ;
     RECT  45.6 2.151 45.912 84.085 ;
     RECT  41.76 84.085 45.912 84.131 ;
     RECT  10.5 40.165 11.688 84.179 ;
     RECT  64.5 73.813 65.016 84.325 ;
     RECT  7.8 83.125 8.232 84.419 ;
     RECT  5.1 83.077 5.592 84.947 ;
     RECT  5.1 84.947 5.544 85.045 ;
     RECT  2.4 83.173 2.952 85.091 ;
     RECT  7.8 84.419 8.112 85.813 ;
     RECT  4.32 85.045 5.544 86.005 ;
     RECT  91.392 73.811 91.812 86.005 ;
     RECT  4.32 86.005 5.592 86.195 ;
     RECT  5.1 86.195 5.592 87.251 ;
     RECT  7.8 85.813 8.376 87.827 ;
     RECT  91.344 86.005 91.812 87.875 ;
     RECT  5.1 87.251 5.544 87.923 ;
     RECT  2.4 85.091 2.712 87.925 ;
     RECT  91.392 87.875 91.812 87.973 ;
     RECT  2.304 87.925 2.712 88.115 ;
     RECT  37.5 54.755 37.812 92.869 ;
     RECT  21.3 74.869 22.488 93.061 ;
     RECT  40.08 83.749 40.512 95.125 ;
     RECT  41.76 84.131 43.212 95.125 ;
     RECT  37.5 92.869 38.376 95.413 ;
     RECT  91.392 87.973 92.616 96.467 ;
     RECT  91.392 96.467 91.812 98.099 ;
     RECT  93.12 97.429 93.144 98.339 ;
     RECT  21.3 93.061 22.632 99.779 ;
     RECT  91.5 98.099 91.812 100.117 ;
     RECT  90.96 100.117 91.812 100.501 ;
     RECT  90.96 100.501 91.944 100.547 ;
     RECT  91.5 100.547 91.944 101.027 ;
     RECT  40.08 95.125 43.212 103.907 ;
     RECT  40.2 103.907 43.212 104.339 ;
     RECT  64.5 84.325 65.592 105.875 ;
     RECT  37.5 95.413 38.76 105.925 ;
     RECT  40.2 104.339 40.776 105.925 ;
     RECT  44.544 84.131 45.912 107.219 ;
     RECT  37.5 105.925 40.776 107.605 ;
     RECT  41.76 104.339 43.212 107.605 ;
     RECT  45.024 107.219 45.912 108.323 ;
     RECT  37.5 107.605 43.212 108.469 ;
     RECT  37.5 108.469 43.32 110.485 ;
     RECT  37.392 110.485 43.32 114.035 ;
     RECT  7.8 87.827 8.112 118.165 ;
     RECT  34.8 2.151 35.112 119.077 ;
     RECT  37.392 114.035 41.016 119.125 ;
     RECT  22.608 99.779 22.632 119.171 ;
     RECT  7.8 118.165 8.28 119.461 ;
     RECT  42.048 114.035 43.32 119.701 ;
     RECT  34.8 119.077 35.352 120.467 ;
     RECT  34.8 120.467 35.112 121.525 ;
     RECT  7.68 119.461 8.28 121.571 ;
     RECT  37.296 119.125 41.016 121.571 ;
     RECT  7.68 121.571 8.112 122.485 ;
     RECT  2.4 88.115 2.712 122.821 ;
     RECT  7.056 122.485 8.112 122.821 ;
     RECT  34.8 121.525 35.592 122.915 ;
     RECT  34.8 122.915 35.112 125.365 ;
     RECT  88.8 54.035 89.112 125.605 ;
     RECT  94.2 42.035 94.512 125.893 ;
     RECT  64.5 105.875 65.016 126.179 ;
     RECT  34.8 125.365 35.352 126.611 ;
     RECT  94.08 125.893 94.512 126.611 ;
     RECT  34.8 126.611 35.112 127.621 ;
     RECT  88.8 125.605 89.976 127.621 ;
     RECT  37.392 121.571 41.016 127.667 ;
     RECT  37.392 127.667 38.328 128.149 ;
     RECT  92.88 127.669 92.904 128.339 ;
     RECT  2.4 122.821 3.384 128.867 ;
     RECT  2.4 128.867 2.712 128.965 ;
     RECT  2.304 128.965 2.712 129.155 ;
     RECT  7.056 122.821 8.232 129.155 ;
     RECT  34.8 127.621 35.352 129.443 ;
     RECT  42 119.701 43.32 129.491 ;
     RECT  0.144 130.549 0.168 130.787 ;
     RECT  7.8 129.155 8.232 130.979 ;
     RECT  37.152 128.149 38.328 130.981 ;
     RECT  39.36 127.667 41.016 130.981 ;
     RECT  34.8 129.443 35.112 131.077 ;
     RECT  78 2.151 78.312 131.077 ;
     RECT  37.152 130.981 41.016 131.123 ;
     RECT  78 131.077 78.696 131.315 ;
     RECT  42 129.491 43.212 131.747 ;
     RECT  76.752 125.365 76.776 132.085 ;
     RECT  78 131.315 78.312 132.085 ;
     RECT  34.8 131.077 35.4 132.131 ;
     RECT  76.752 132.085 78.312 132.131 ;
     RECT  42.096 131.747 43.212 132.419 ;
     RECT  42.336 132.419 43.212 132.707 ;
     RECT  37.392 131.123 41.016 132.757 ;
     RECT  77.424 132.131 78.312 133.427 ;
     RECT  37.152 132.757 41.016 133.429 ;
     RECT  37.056 133.429 41.016 134.387 ;
     RECT  77.472 133.427 78.312 134.579 ;
     RECT  37.152 134.387 41.016 135.875 ;
     RECT  37.152 135.875 38.328 136.067 ;
     RECT  88.8 127.621 90.024 138.803 ;
     RECT  91.5 101.027 91.812 138.949 ;
     RECT  37.296 136.067 38.328 139.381 ;
     RECT  91.5 138.949 91.944 139.715 ;
     RECT  88.8 138.803 89.976 141.299 ;
     RECT  39.36 135.875 41.016 142.547 ;
     RECT  37.296 139.381 38.376 143.075 ;
     RECT  88.8 141.299 89.208 143.075 ;
     RECT  37.392 143.075 38.376 143.461 ;
     RECT  39.36 142.547 40.512 143.461 ;
     RECT  37.392 143.461 40.512 148.835 ;
     RECT  37.392 148.835 38.28 164.771 ;
     RECT  37.5 164.771 38.28 166.115 ;
     RECT  2.4 129.155 2.712 168.489 ;
     RECT  5.1 87.923 5.412 168.489 ;
     RECT  7.8 130.979 8.112 168.489 ;
     RECT  10.5 84.179 10.812 168.489 ;
     RECT  13.2 46.547 13.512 168.489 ;
     RECT  15.9 2.151 16.212 168.489 ;
     RECT  18.6 2.151 18.912 168.489 ;
     RECT  21.3 99.779 21.612 168.489 ;
     RECT  24 2.151 24.312 168.489 ;
     RECT  26.7 2.151 27.012 168.489 ;
     RECT  29.4 2.151 29.712 168.489 ;
     RECT  32.1 2.151 32.412 168.489 ;
     RECT  34.8 132.131 35.112 168.489 ;
     RECT  39.36 148.835 40.512 168.489 ;
     RECT  42.9 132.707 43.212 168.489 ;
     RECT  45.6 108.323 45.912 168.489 ;
     RECT  48.3 2.151 48.612 168.489 ;
     RECT  51 2.151 51.312 168.489 ;
     RECT  53.7 2.151 54.012 168.489 ;
     RECT  56.4 2.151 56.712 168.489 ;
     RECT  59.1 2.151 59.412 168.489 ;
     RECT  61.8 2.151 62.112 168.489 ;
     RECT  64.5 126.179 64.812 168.489 ;
     RECT  67.2 2.151 67.512 168.489 ;
     RECT  69.9 2.151 70.212 168.489 ;
     RECT  72.6 2.151 72.912 168.489 ;
     RECT  75.3 2.151 75.612 168.489 ;
     RECT  78 134.579 78.312 168.489 ;
     RECT  80.7 2.151 81.012 168.489 ;
     RECT  83.4 2.151 83.712 168.489 ;
     RECT  86.1 2.151 86.412 168.489 ;
     RECT  88.8 143.075 89.112 168.489 ;
     RECT  91.5 139.715 91.812 168.489 ;
     RECT  94.2 126.611 94.512 168.489 ;
     RECT  2.4 168.489 2.52 168.503 ;
     RECT  5.1 168.489 5.22 168.503 ;
     RECT  7.8 168.489 7.92 168.503 ;
     RECT  10.5 168.489 10.62 168.503 ;
     RECT  13.2 168.489 13.32 168.503 ;
     RECT  15.9 168.489 16.02 168.503 ;
     RECT  18.6 168.489 18.72 168.503 ;
     RECT  21.3 168.489 21.42 168.503 ;
     RECT  24 168.489 24.12 168.503 ;
     RECT  26.7 168.489 26.82 168.503 ;
     RECT  29.4 168.489 29.52 168.503 ;
     RECT  32.1 168.489 32.22 168.503 ;
     RECT  34.8 168.489 34.92 168.503 ;
     RECT  37.5 166.115 37.992 168.503 ;
     RECT  39.36 168.489 40.32 168.503 ;
     RECT  42.9 168.489 43.02 168.503 ;
     RECT  45.6 168.489 45.72 168.503 ;
     RECT  48.3 168.489 48.42 168.503 ;
     RECT  51 168.489 51.12 168.503 ;
     RECT  53.7 168.489 53.82 168.503 ;
     RECT  56.4 168.489 56.52 168.503 ;
     RECT  59.1 168.489 59.22 168.503 ;
     RECT  61.8 168.489 61.92 168.503 ;
     RECT  64.5 168.489 64.62 168.503 ;
     RECT  67.2 168.489 67.32 168.503 ;
     RECT  69.9 168.489 70.02 168.503 ;
     RECT  72.6 168.489 72.72 168.503 ;
     RECT  75.3 168.489 75.42 168.503 ;
     RECT  78 168.489 78.12 168.503 ;
     RECT  80.7 168.489 80.82 168.503 ;
     RECT  83.4 168.489 83.52 168.503 ;
     RECT  86.1 168.489 86.22 168.503 ;
     RECT  88.8 168.489 88.92 168.503 ;
     RECT  91.5 168.489 91.62 168.503 ;
     RECT  94.2 168.489 94.32 168.503 ;
     RECT  39.36 168.503 39.384 170.483 ;
     RECT  37.968 168.503 37.992 170.531 ;
  END
END qfd_landh0d8sn_182_EW_98x171
END LIBRARY
